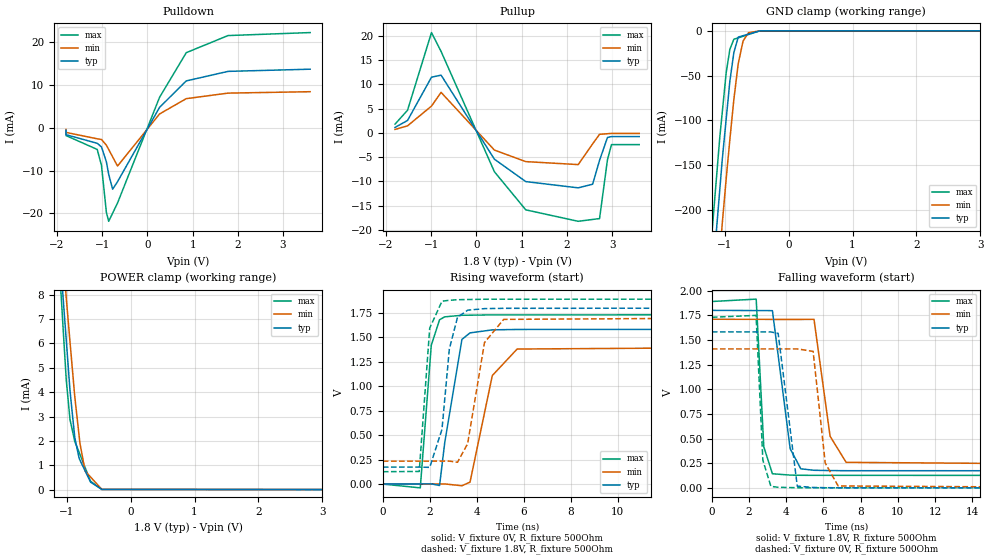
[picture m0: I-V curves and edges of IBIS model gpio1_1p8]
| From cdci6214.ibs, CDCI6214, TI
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|   gpio1_1p8 Model
[Model]   gpio1_1p8
Model_type   I/O
Polarity   Non-Inverting
Enable   Active-High
Vinl = 0.36
Vinh = 1.44
Vmeas = 0.9
Vref = 0
Cref = 2pF
Rref = 100000
|   typ   min   max
C_comp   1.252E-12   1.207E-12   1.304E-12
|  Where Nom  PVT is Nominal Process, 1.8V,   32C
|   Fast PVT is Strong Process,  1.89V, -35C
|   Slow PVT is Weak Process,   1.71V, 110C
[Model spec]
|subparameter
Vinl   0.36   0.342   0.378
Vinh   1.44   1.368   1.512
[Voltage Range]   1.8   1.71   1.89
|Junction Temperature
[Temperature Range]   32   110   -35
[Pullup Reference]   1.8   1.71   1.89
[Pulldown Reference]   0   0   0
[Power Clamp Reference]   1.8   1.71   1.89
[GND Clamp Reference]   0   0   0
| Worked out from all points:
|   slope of the pulldown table from 0 to 0.27 V, typ, clamps not added: 55.7 ohm
|   slope of the pullup table from 0 to 0.27 V, typ, clamps not added: 70.4 ohm
|   GND clamp passes 1 mA (typ) near -0.50 V on its own axis
|   POWER clamp passes 1 mA (typ) near -0.75 V on its own axis
|   falling waveform, V_fixture 1.8V, R_fixture 500Ohm: 20-80 % time 400ps typ, 631ps min, 255ps max; typ from 1.8 V to 0.173 V
|   rising waveform, V_fixture 0V, R_fixture 500Ohm: 20-80 % time 469ps typ, 763ps min, 311ps max; typ from 0 V to 1.58 V
|   rising waveform, V_fixture 1.8V, R_fixture 500Ohm: 20-80 % time 398ps typ, 588ps min, 276ps max; typ from 0.173 V to 1.8 V
|   falling waveform, V_fixture 0V, R_fixture 500Ohm: 20-80 % time 328ps typ, 464ps min, 225ps max; typ from 1.58 V to 0 V
[Pulldown]
|   Voltage   I(typ)   I(min)   I(max)
-1.8V     -534.4uA   -343.3uA   -743.5uA
-1.799V   -1.576mA   -1.043mA   -1.791mA
-1.11V    -3.594mA   -2.538mA   -5.023mA
-1.016V   -4.44mA    -2.696mA   -8.752mA
-907.8mV  -7.93mA    -4.019mA   -19.73mA
-856.5mV  -10.85mA   -5.037mA   -21.84mA
-769.6mV  -14.33mA   -6.76mA    -19.94mA
-661.2mV  -12.58mA   -8.91mA    -17.56mA
268.4mV   4.819mA    3.273mA    7.164mA
859.7mV   11.01mA    6.859mA    17.62mA
1.784V    13.24mA    8.153mA    21.62mA
3.6V      13.75mA    8.484mA    22.32mA
[GND Clamp]
|   Voltage   I(typ)   I(min)   I(max)
-1.8V     -850.2mA   -919.7mA   -794.1mA
-1.193V   -278.9mA   -350.7mA   -220.9mA
-1.076V   -177.3mA   -248.8mA   -118.9mA
-1.036V   -142.7mA   -214.1mA   -90.05mA
-975.8mV  -98.35mA   -165.2mA   -46.72mA
-918.6mV  -56.29mA   -121.4mA   -20.63mA
-855.9mV  -24.17mA   -76.52mA   -9.412mA
-787.5mV  -7.002mA   -36.62mA   -7.827mA
-711.9mV  -5.436mA   -11.36mA   -6.076mA
-626.1mV  -3.657mA   -2.091mA   -4.086mA
-449.8mV  -7.895uA   -51.08uA   -2.497uA
3.6V      0A         0A         0A
[Pullup]
|   Voltage   I(typ)   I(min)   I(max)
-1.8V     1.138mA    720.3uA    1.811mA
-1.524V   2.565mA    1.459mA    4.673mA
-994.2mV  11.48mA    5.53mA     20.67mA
-782.2mV  11.9mA     8.354mA    16.79mA
397.4mV   -5.409mA   -3.533mA   -7.995mA
1.091V    -10.02mA   -5.907mA   -15.84mA
2.251V    -11.31mA   -6.521mA   -18.2mA
2.57V     -10.56mA   -2.253mA   -17.82mA
2.723V    -5.635mA   -283.5uA   -17.64mA
2.898V    -941.7uA   -163.4uA   -5.522mA
2.987V    -754.9uA   -102.9uA   -2.403mA
3.6V      -754.9uA   -102.9uA   -2.403mA
[POWER Clamp]
|   Voltage   I(typ)   I(min)   I(max)
-1.8V     40.9mA     37.22mA    47.79mA
-1.102V   9.844mA    11.21mA    8.686mA
-1.055V   7.877mA    9.555mA    6.632mA
-1.005V   6.115mA    7.85mA     4.479mA
-947.2mV  4.068mA    6.068mA    2.877mA
-872.2mV  2.133mA    3.809mA    1.978mA
-803.1mV  1.274mA    2.173mA    1.52mA
-791.3mV  1.209mA    1.896mA    1.442mA
-710.3mV  768.4uA    759.9uA    904.6uA
-625.3mV  306.3uA    515.8uA    341uA
-449.8mV  9.837uA    11.93uA    5.418uA
3.6V      0A         0A         0A
[Ramp]
R_load = 500
|   typ   min   max
dV/dt_r   0.949422/4.66812e-10   0.845683/7.56947e-10   1.03789/3.08826e-10
dV/dt_f   0.976018/3.98838e-10   0.885426/6.29237e-10   1.05806/2.5483e-10
[Falling Waveform]
V_fixture = 1.8V
V_fixture_min = 1.71V
V_fixture_max = 1.89V
R_fixture = 500Ohm
C_fixture = 0F
|   Time   V(typ)   V(min)   V(max)
0s        1.8V       1.71V      1.89V
2.383ns   1.798V     1.709V     1.914V
2.792ns   1.798V     1.709V     416.2mV
3.255ns   1.797V     1.708V     143mV
4.21ns    396.9mV    1.708V     129.5mV
4.781ns   193.1mV    1.708V     127.6mV
5.491ns   178.3mV    1.709V     127mV
6.355ns   175.3mV    523.4mV    127mV
7.219ns   174mV      258.7mV    126.9mV
25ns      173.3mV    234.3mV    126.6mV
[Rising Waveform]
V_fixture = 0V
V_fixture_min = 0V
V_fixture_max = 0V
R_fixture = 500Ohm
C_fixture = 0F
|   Time   V(typ)   V(min)   V(max)
0s        -560nV     -3.175uV   -9.945nV
1.594ns   1.679mV    962.5uV    -38.6mV
2.063ns   2.172mV    1.247mV    1.419V
2.415ns   -14.67mV   1.46mV     1.679V
2.635ns   422.2mV    1.593mV    1.709V
3.367ns   1.478V     -17.11mV   1.725V
3.712ns   1.545V     19.72mV    1.726V
4.661ns   1.576V     1.109V     1.729V
5.718ns   1.58V      1.38V      1.729V
25ns      1.582V     1.409V     1.73V
[Rising Waveform]
V_fixture = 1.8V
V_fixture_min = 1.71V
V_fixture_max = 1.89V
R_fixture = 500Ohm
C_fixture = 0F
|   Time   V(typ)   V(min)   V(max)
0s        173.3mV    234.3mV    126.6mV
1.549ns   173.9mV    234.7mV    129.1mV
1.996ns   170.8mV    234.8mV    1.594V
2.519ns   560.1mV    235mV      1.869V
2.831ns   1.379V     235mV      1.878V
3.178ns   1.704V     222.8mV    1.884V
3.611ns   1.777V     412.6mV    1.886V
4.328ns   1.793V     1.446V     1.889V
5.144ns   1.796V     1.683V     1.889V
25ns      1.8V       1.71V      1.89V
[Falling Waveform]
|Gnd
V_fixture = 0V
V_fixture_min = 0V
V_fixture_max = 0V
R_fixture = 500Ohm
C_fixture = 0F
|   Time   V(typ)   V(min)   V(max)
0s        1.582V     1.409V     1.73V
2.377ns   1.582V     1.409V     1.749V
2.741ns   1.581V     1.409V     280.5mV
3.173ns   1.581V     1.409V     15.24mV
3.563ns   1.567V     1.409V     5.696mV
4.592ns   17.33mV    1.409V     1.272mV
5.443ns   3.899mV    1.384V     370.7uV
6.094ns   1.929mV    251.7mV    358.3uV
6.789ns   599.8uV    19.14mV    345.1uV
25ns      -2.146uV   -974.5nV   -841.8nV
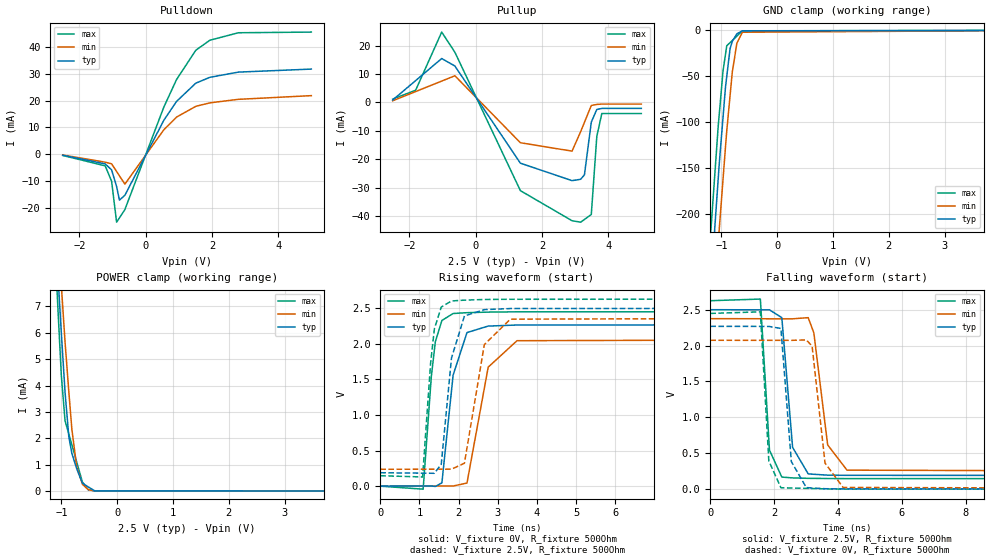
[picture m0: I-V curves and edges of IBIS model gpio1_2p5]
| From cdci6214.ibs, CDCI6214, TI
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|   gpio1_2p5 Model
[Model]   gpio1_2p5
Model_type   I/O
Polarity   Non-Inverting
Enable   Active-High
Vinl = 0.5
Vinh = 2
Vmeas = 1.25
Vref = 0
Cref = 2pF
Rref = 100000
|   typ   min   max
C_comp   1.238E-12   1.196E-12   1.283E-12
|  Where Nom  PVT is Nominal Process, 2.5V,   32C
|   Fast PVT is Strong Process,  2.625V, -35C
|   Slow PVT is Weak Process,   2.375V, 110C
[Model spec]
|subparameter
Vinl   0.5   0.475   0.525
Vinh   2   1.9   2.1
[Voltage Range]   2.5   2.375   2.625
|Junction Temperature
[Temperature Range]   32   110   -35
[Pullup Reference]   2.5   2.375   2.625
[Pulldown Reference]   0   0   0
[Power Clamp Reference]   2.5   2.375   2.625
[GND Clamp Reference]   0   0   0
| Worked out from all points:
|   slope of the pulldown table from 0 to 0.375 V, typ, clamps not added: 42.2 ohm
|   slope of the pullup table from 0 to 0.375 V, typ, clamps not added: 52.2 ohm
|   GND clamp passes 1 mA (typ) near -0.64 V on its own axis
|   POWER clamp passes 1 mA (typ) near -0.76 V on its own axis
|   falling waveform, V_fixture 2.5V, R_fixture 500Ohm: 20-80 % time 249ps typ, 353ps min, 177ps max; typ from 2.5 V to 0.189 V
|   rising waveform, V_fixture 0V, R_fixture 500Ohm: 20-80 % time 289ps typ, 418ps min, 205ps max; typ from 0 V to 2.27 V
|   rising waveform, V_fixture 2.5V, R_fixture 500Ohm: 20-80 % time 268ps typ, 372ps min, 194ps max; typ from 0.189 V to 2.5 V
|   falling waveform, V_fixture 0V, R_fixture 500Ohm: 20-80 % time 225ps typ, 304ps min, 165ps max; typ from 2.27 V to 0 V
[Pulldown]
|   Voltage   I(typ)   I(min)   I(max)
-2.5V     -377.7uA   -273.8uA   -478.9uA
-1.219V   -3.643mA   -3.006mA   -4.374mA
-1.025V   -5.883mA   -3.611mA   -10.14mA
-873.9mV  -12.11mA   -6.479mA   -25.46mA
-788.5mV  -17.2mA    -8.104mA   -23.84mA
-625mV    -15.39mA   -11.21mA   -20.75mA
551.9mV   12.71mA    9.153mA    17.66mA
934.4mV   19.76mA    13.88mA    27.94mA
1.515V    26.58mA    17.91mA    38.9mA
1.939V    28.77mA    19.21mA    42.65mA
2.799V    30.72mA    20.53mA    45.45mA
5V        31.85mA    21.91mA    45.7mA
[GND Clamp]
|   Voltage   I(typ)   I(min)   I(max)
-2.5V     -1.532A    -1.598A    -1.479A
-1.229V   -310.7mA   -383.7mA   -251.8mA
-1.058V   -161.6mA   -231.9mA   -104.4mA
-1.036V   -142.8mA   -213.9mA   -89.16mA
-971.4mV  -94.66mA   -162.1mA   -44.15mA
-927.2mV  -61.72mA   -126.6mA   -26.06mA
-904.6mV  -50.13mA   -109.4mA   -16.81mA
-845.5mV  -19.9mA    -71.15mA   -13.38mA
-806mV    -12.04mA   -45.73mA   -11.09mA
-723.5mV  -3.784mA   -13.92mA   -6.312mA
-625mV    -518.2uA   -2.081mA   -602.9uA
5V        0A         0A         0A
[Pullup]
|   Voltage   I(typ)   I(min)   I(max)
-2.5V     863.2uA    597.5uA    1.192mA
-1.808V   7.701mA    3.843mA    4.308mA
-1.022V   15.47mA    7.531mA    24.77mA
-624.5mV  12.83mA    9.398mA    17.68mA
1.352V    -21.36mA   -14.17mA   -31.03mA
2.91V     -27.51mA   -17.12mA   -41.61mA
3.17V     -27.02mA   -10.27mA   -42.13mA
3.284V    -25.47mA   -6.997mA   -41.18mA
3.491V    -6.918mA   -1.049mA   -39.42mA
3.657V    -2.462mA   -696.9uA   -11.96mA
3.808V    -2.089mA   -557.7uA   -3.894mA
5V        -2.089mA   -557.7uA   -3.894mA
[POWER Clamp]
|   Voltage   I(typ)   I(min)   I(max)
-2.5V     73.53mA    64.44mA    89.01mA
-1.085V   9.153mA    10.62mA    7.88mA
-1.055V   7.877mA    9.508mA    6.585mA
-1.002V   5.997mA    7.808mA    4.379mA
-935.4mV  3.748mA    5.651mA    2.665mA
-868mV    2.056mA    3.773mA    2.16mA
-812.7mV  1.421mA    2.33mA     1.746mA
-727.2mV  846.4uA    931.3uA    1.106mA
-624.9mV  297.1uA    253.7uA    338.8uA
-518.4mV  151.2uA    44.51uA    41.68uA
-403.7mV  2.859uA    5.5uA      1.412uA
5V        0A         0A         0A
[Ramp]
R_load = 500
|   typ   min   max
dV/dt_r   1.361/2.87747e-10   1.24438/4.1623e-10   1.46879/2.04608e-10
dV/dt_f   1.38683/2.47828e-10   1.28257/3.49891e-10   1.48709/1.76228e-10
[Falling Waveform]
V_fixture = 2.5V
V_fixture_min = 2.375V
V_fixture_max = 2.625V
R_fixture = 500Ohm
C_fixture = 0F
|   Time   V(typ)   V(min)   V(max)
0s        2.5V       2.375V     2.625V
1.568ns   2.498V     2.374V     2.648V
1.853ns   2.498V     2.373V     544mV
2.24ns    2.389V     2.373V     168.3mV
2.577ns   582.6mV    2.373V     156.8mV
3.066ns   213.2mV    2.389V     151mV
3.243ns   207.2mV    2.176V     150.2mV
3.675ns   195.3mV    616.6mV    148.3mV
4.281ns   192.7mV    264.8mV    147mV
25ns      188.6mV    237.4mV    146.5mV
[Rising Waveform]
V_fixture = 0V
V_fixture_min = 0V
V_fixture_max = 0V
R_fixture = 500Ohm
C_fixture = 0F
|   Time   V(typ)   V(min)   V(max)
0s        -1.66uV    -76.04nV   -15.21nV
1.095ns   2.18mV     1.405mV    -41.95mV
1.305ns   2.598mV    1.674mV    1.543V
1.407ns   -3.984mV   1.806mV    2.027V
1.574ns   46.33mV    2.02mV     2.325V
1.861ns   1.559V     2.388mV    2.422V
2.215ns   2.155V     43.82mV    2.434V
2.757ns   2.246V     1.67V      2.442V
3.493ns   2.261V     2.041V     2.446V
25ns      2.268V     2.074V     2.448V
[Rising Waveform]
V_fixture = 2.5V
V_fixture_min = 2.375V
V_fixture_max = 2.625V
R_fixture = 500Ohm
C_fixture = 0F
|   Time   V(typ)   V(min)   V(max)
0s        188.6mV    237.4mV    146.5mV
1.081ns   182.5mV    238mV      129.3mV
1.286ns   181.4mV    238.1mV    1.729V
1.382ns   180.8mV    238.1mV    2.207V
1.558ns   307.5mV    238.2mV    2.513V
1.819ns   1.797V     238.3mV    2.598V
2.15ns    2.388V     322mV      2.61V
2.657ns   2.477V     1.986V     2.619V
3.323ns   2.492V     2.343V     2.622V
25ns      2.5V       2.375V     2.625V
[Falling Waveform]
|Gnd
V_fixture = 0V
V_fixture_min = 0V
V_fixture_max = 0V
R_fixture = 500Ohm
C_fixture = 0F
|   Time   V(typ)   V(min)   V(max)
0s        2.268V     2.074V     2.448V
1.567ns   2.267V     2.073V     2.47V
1.833ns   2.267V     2.073V     393.2mV
2.212ns   2.238V     2.073V     19.93mV
2.537ns   385.2mV    2.073V     16.22mV
3.007ns   22.05mV    2.079V     10.98mV
3.188ns   16.29mV    1.992V     8.96mV
3.593ns   6.128mV    363.2mV    4.444mV
4.159ns   3.939mV    23.86mV    444.4uV
25ns      -1.33uV    -518.7nV   21.16nV
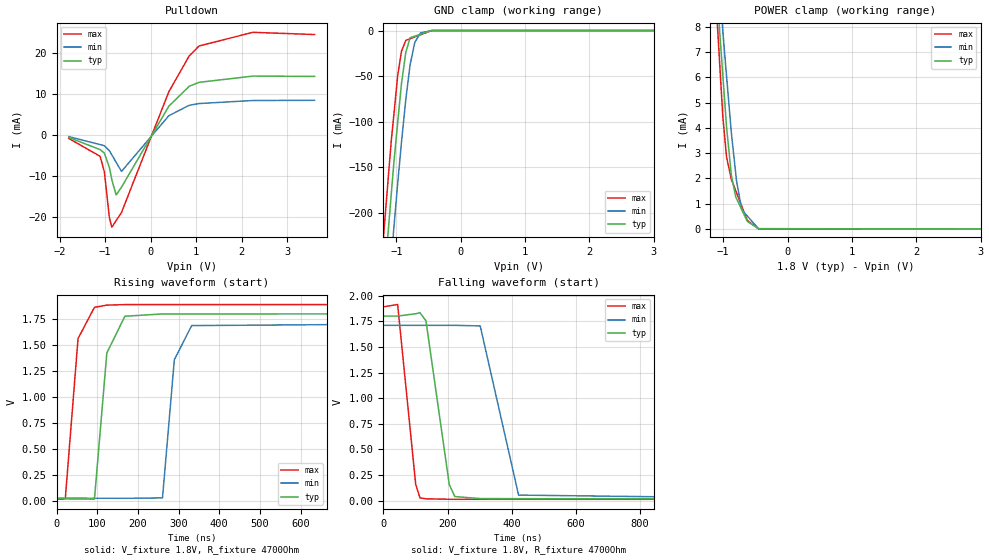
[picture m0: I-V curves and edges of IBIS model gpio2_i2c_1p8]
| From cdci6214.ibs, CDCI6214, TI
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|   gpio2_i2c_1p8 Model
[Model]   gpio2_i2c_1p8
Model_type   I/O_open_drain
Polarity   Inverting
Enable   Active-High
Vinl = 0.36
Vinh = 1.44
Vmeas = 0.9
Vref = 1.8
Cref = 1pF
Rref = 4700
|   typ   min   max
C_comp   1.654E-12   1.599E-12   1.724E-12
|  Where Nom  PVT is Nominal Process, 1.8V,   32C
|   Fast PVT is Strong Process,  1.89V, -35C
|   Slow PVT is Weak Process,   1.71V, 110C
[Model spec]
|subparameter
Vinl   0.36   0.342   0.378
Vinh   1.44   1.368   1.512
[Voltage Range]   1.8   1.71   1.89
|Junction Temperature
[Temperature Range]   32   110   -35
[Pullup Reference]   1.8   1.71   1.89
[Pulldown Reference]   0   0   -0
[Power Clamp Reference]   1.8   1.71   1.89
[GND Clamp Reference]   0   0   0
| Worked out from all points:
|   slope of the pulldown table from 0 to 0.27 V, typ, clamps not added: 53.8 ohm
|   GND clamp passes 1 mA (typ) near -0.49 V on its own axis
|   POWER clamp passes 1 mA (typ) near -0.75 V on its own axis
|   falling waveform, V_fixture 1.8V, R_fixture 4700Ohm: 20-80 % time 47ns typ, 59.8ns min, 35ns max; typ from 1.8 V to 0.019 V
|   rising waveform, V_fixture 1.8V, R_fixture 4700Ohm: 20-80 % time 23.4ns typ, 23.2ns min, 24.1ns max; typ from 0.019 V to 1.8 V
[Pulldown]
|   Voltage   I(typ)   I(min)   I(max)
-1.8V     -529.7uA   -319uA     -765.4uA
-1.113V   -3.481mA   -2.265mA   -5.111mA
-1.019V   -4.334mA   -2.531mA   -8.878mA
-907.6mV  -7.882mA   -3.763mA   -20.16mA
-853.6mV  -10.9mA    -4.789mA   -22.37mA
-759.2mV  -14.52mA   -6.582mA   -20.78mA
-642.8mV  -12.64mA   -8.795mA   -18.81mA
397.6mV   7.091mA    4.775mA    10.61mA
844.7mV   11.93mA    7.309mA    19.32mA
1.061V    12.9mA     7.735mA    21.76mA
2.247V    14.42mA    8.478mA    25.08mA
3.6V      14.34mA    8.522mA    24.54mA
[GND Clamp]
|   Voltage   I(typ)   I(min)   I(max)
-1.8V     -850.4mA   -920mA     -794.3mA
-1.195V   -281.4mA   -353.2mA   -223.4mA
-1.078V   -179.7mA   -251.2mA   -121.3mA
-1.038V   -145.7mA   -217.1mA   -93.09mA
-977.8mV  -100.9mA   -167.7mA   -49.4mA
-919.4mV  -58.33mA   -123.1mA   -22.82mA
-852.7mV  -24.16mA   -76.14mA   -10.82mA
-785.2mV  -7.96mA    -37.67mA   -9.006mA
-711.4mV  -6.211mA   -12.78mA   -7.027mA
-621.2mV  -4.073mA   -2.524mA   -4.607mA
-449.5mV  -9.741uA   -65.93uA   -3.053uA
3.6V      0A         0A         0A
[POWER Clamp]
|   Voltage   I(typ)   I(min)   I(max)
-1.8V     40.78mA    37.11mA    47.66mA
-1.102V   9.792mA    11.17mA    8.628mA
-1.055V   7.836mA    9.518mA    6.587mA
-1.005V   6.075mA    7.815mA    4.436mA
-947mV    4.034mA    6.038mA    2.843mA
-872.1mV  2.111mA    3.79mA     1.956mA
-803.5mV  1.264mA    2.173mA    1.507mA
-791.3mV  1.197mA    1.885mA    1.427mA
-710.3mV  761uA      754.3uA    896.6uA
-624.6mV  299.7uA    509.9uA    335uA
-449.6mV  9.478uA    10.99uA    5.168uA
3.6V      0A         0A         0A
[Ramp]
R_load = 4700
|   typ   min   max
dV/dt_r   1.06865/2.34279e-08   1.01076/2.31746e-08   1.12574/2.41307e-08
dV/dt_f   1.06865/4.70057e-08   1.01076/5.97479e-08   1.12574/3.50203e-08
[Falling Waveform]
V_fixture = 1.8V
V_fixture_min = 1.71V
V_fixture_max = 1.89V
R_fixture = 4700Ohm
C_fixture = 0F
|   Time   V(typ)   V(min)   V(max)
0s        1.8V       1.71V      1.89V
44.34ns   1.8V       1.71V      1.913V
100.7ns   1.823V     1.71V      158.3mV
113.9ns   1.833V     1.71V      28.66mV
132.7ns   1.754V     1.71V      18.69mV
205.3ns   157.9mV    1.71V      14.27mV
222.6ns   40.74mV    1.71V      14.26mV
301.7ns   21.25mV    1.704V     14.22mV
421.3ns   19.91mV    55.14mV    14.15mV
1.2us     18.86mV    25.33mV    13.74mV
[Rising Waveform]
V_fixture = 1.8V
V_fixture_min = 1.71V
V_fixture_max = 1.89V
R_fixture = 4700Ohm
C_fixture = 0F
|   Time   V(typ)   V(min)   V(max)
0s        18.86mV    25.33mV    13.74mV
21.56ns   18.05mV    25.12mV    19.68mV
52.9ns    16.86mV    24.82mV    1.562V
93.28ns   15.33mV    24.43mV    1.863V
123.7ns   1.423V     24.13mV    1.884V
168.1ns   1.777V     23.7mV     1.889V
260.6ns   1.799V     27.37mV    1.889V
289.7ns   1.799V     1.358V     1.889V
332.4ns   1.799V     1.687V     1.889V
1.2us     1.8V       1.71V      1.89V
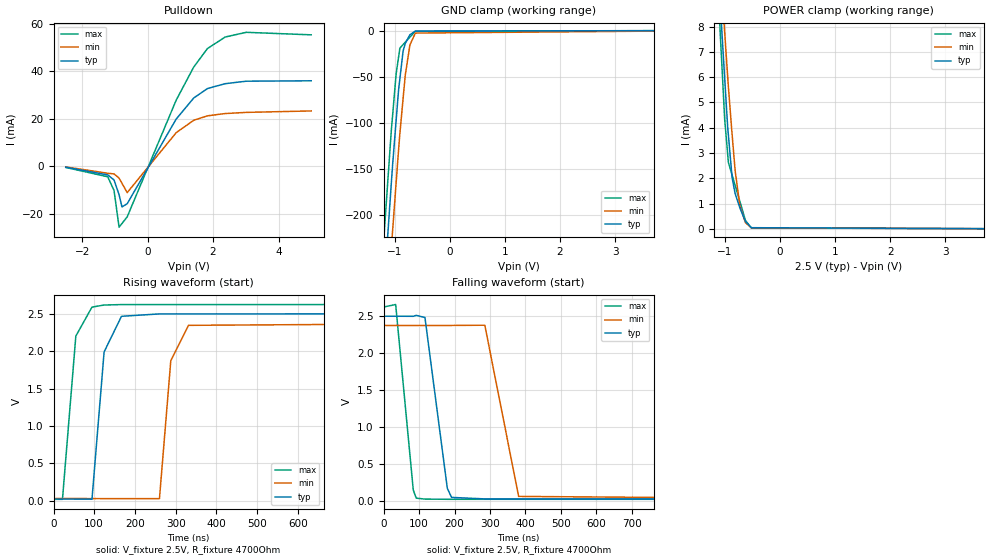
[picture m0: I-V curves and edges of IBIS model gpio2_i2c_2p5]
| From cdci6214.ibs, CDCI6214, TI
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|   gpio2_i2c_2p5 Model
[Model]   gpio2_i2c_2p5
Model_type   I/O_open_drain
Polarity   Inverting
Enable   Active-High
Vinl = 0.5
Vinh = 2
Vmeas = 1.25
Vref = 2.5
Cref = 1pF
Rref = 4700
|   typ   min   max
C_comp   1.718E-12   1.615E-12   1.829E-12
|  Where Nom  PVT is Nominal Process, 2.5V,   32C
|   Fast PVT is Strong Process,  2.625V, -35C
|   Slow PVT is Weak Process,   2.375V, 110C
[Model spec]
|subparameter
Vinl   0.5   0.475   0.525
Vinh   2   1.9   2.1
[Voltage Range]   2.5   2.375   2.625
|Junction Temperature
[Temperature Range]   32   110   -35
[Pullup Reference]   2.5   2.375   2.625
[Pulldown Reference]   0   -0   0
[Power Clamp Reference]   2.5   2.375   2.625
[GND Clamp Reference]   0   0   0
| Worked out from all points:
|   slope of the pulldown table from 0 to 0.375 V, typ, clamps not added: 41.1 ohm
|   GND clamp passes 1 mA (typ) near -0.63 V on its own axis
|   POWER clamp passes 1 mA (typ) near -0.76 V on its own axis
|   falling waveform, V_fixture 2.5V, R_fixture 4700Ohm: 20-80 % time 40.2ns typ, 49.3ns min, 31ns max; typ from 2.5 V to 0.021 V
|   rising waveform, V_fixture 2.5V, R_fixture 4700Ohm: 20-80 % time 24ns typ, 23.3ns min, 24.9ns max; typ from 0.021 V to 2.5 V
[Pulldown]
|   Voltage   I(typ)   I(min)   I(max)
-2.5V     -367.7uA   -253.3uA   -481.2uA
-1.218V   -3.636mA   -2.932mA   -4.418mA
-1.026V   -5.763mA   -3.216mA   -10.19mA
-872mV    -11.96mA   -4.964mA   -25.65mA
-783.7mV  -17.12mA   -7.15mA    -24.11mA
-624.2mV  -15.78mA   -11.1mA    -21.31mA
873mV     19.91mA    14.17mA    27.87mA
1.408V    28.78mA    19.4mA     41.81mA
1.827V    32.77mA    21.27mA    49.63mA
2.371V    34.83mA    22.24mA    54.5mA
3.013V    35.88mA    22.73mA    56.48mA
5V        36.05mA    23.34mA    55.42mA
[GND Clamp]
|   Voltage   I(typ)   I(min)   I(max)
-2.5V     -1.532A    -1.598A    -1.479A
-1.232V   -314.3mA   -387.3mA   -255.3mA
-1.061V   -165.2mA   -235.5mA   -108mA
-1.039V   -146.6mA   -217.7mA   -92.9mA
-974mV    -97.68mA   -165.1mA   -47.23mA
-930mV    -64.83mA   -129.8mA   -29.04mA
-905.7mV  -52.33mA   -111.5mA   -19.02mA
-846.7mV  -22.01mA   -73.35mA   -15.18mA
-808mV    -14.03mA   -48.41mA   -12.66mA
-724mV    -4.548mA   -15.69mA   -7.195mA
-624.7mV  -640.1uA   -2.747mA   -737.7uA
5V        0A         0A         0A
[POWER Clamp]
|   Voltage   I(typ)   I(min)   I(max)
-2.5V     73.33mA    64.26mA    88.79mA
-1.085V   9.096mA    10.57mA    7.816mA
-1.054V   7.83mA     9.466mA    6.533mA
-1.002V   5.951mA    7.767mA    4.33mA
-948mV    4.035mA    6.035mA    2.961mA
-935mV    3.711mA    5.617mA    2.63mA
-867.7mV  2.032mA    3.75mA     2.133mA
-812.5mV  1.401mA    2.313mA    1.724mA
-727mV    837.2uA    922.4uA    1.092mA
-624.2mV  292.6uA    247.7uA    333.4uA
-518mV    49.58uA    44.54uA    40.45uA
5V        0A         0A         0A
[Ramp]
R_load = 4700
|   typ   min   max
dV/dt_r   1.48749/2.39695e-08   1.40913/2.3343e-08   1.56538/2.48163e-08
dV/dt_f   1.48749/4.0161e-08   1.40913/4.93591e-08   1.56538/3.09874e-08
[Falling Waveform]
V_fixture = 2.5V
V_fixture_min = 2.375V
V_fixture_max = 2.625V
R_fixture = 4700Ohm
C_fixture = 0F
|   Time   V(typ)   V(min)   V(max)
0s        2.5V       2.375V     2.625V
33.87ns   2.5V       2.375V     2.659V
83.53ns   2.499V     2.375V     142.6mV
91.83ns   2.512V     2.375V     32.09mV
116.5ns   2.482V     2.375V     19.19mV
179.6ns   163.7mV    2.375V     16.56mV
191.7ns   42.14mV    2.375V     16.55mV
285.3ns   21.86mV    2.378V     16.5mV
380.7ns   21.75mV    55.66mV    16.45mV
1.2us     20.81mV    26.37mV    16mV
[Rising Waveform]
V_fixture = 2.5V
V_fixture_min = 2.375V
V_fixture_max = 2.625V
R_fixture = 4700Ohm
C_fixture = 0F
|   Time   V(typ)   V(min)   V(max)
0s        20.81mV    26.37mV    16mV
21.95ns   20.05mV    26.27mV    15.86mV
54.81ns   18.92mV    26.13mV    2.202V
94.5ns    17.56mV    25.95mV    2.59V
124.3ns   1.99V      25.81mV    2.618V
167ns     2.467V     25.62mV    2.624V
260.3ns   2.499V     25.19mV    2.624V
288.2ns   2.499V     1.874V     2.624V
331.7ns   2.499V     2.346V     2.624V
1.2us     2.5V       2.375V     2.625V
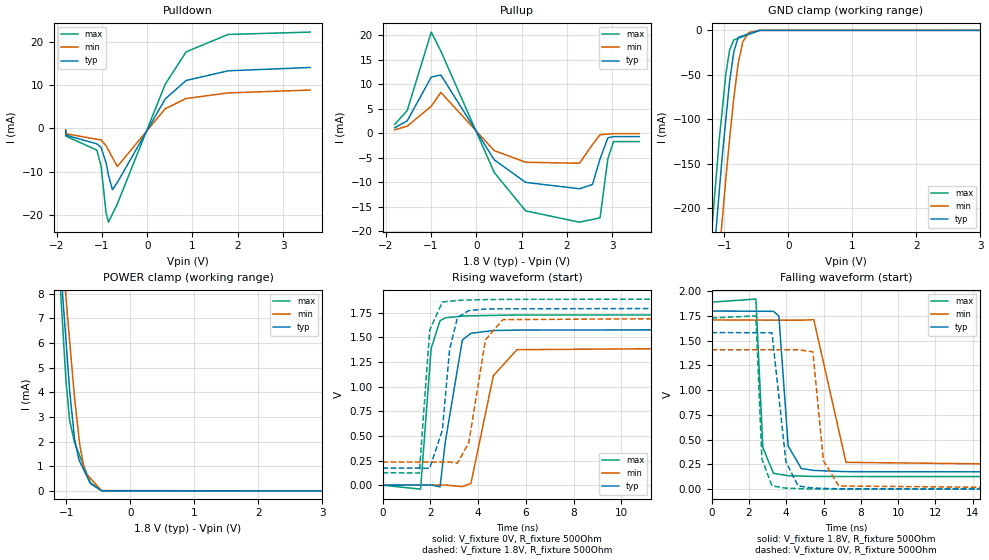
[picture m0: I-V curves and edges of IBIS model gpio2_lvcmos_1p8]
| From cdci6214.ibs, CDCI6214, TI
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|   gpio2_lvcmos_1p8 Model
[Model]   gpio2_lvcmos_1p8
Model_type   I/O
Polarity   Non-Inverting
Enable   Active-High
Vinl = 0.36
Vinh = 1.44
Vmeas = 0.9
Vref = 0
Cref = 1pF
Rref = 100000
|   typ   min   max
C_comp   1.654E-12   1.599E-12   1.724E-12
|  Where Nom  PVT is Nominal Process, 1.8V,   32C
|   Fast PVT is Strong Process,  1.89V, -35C
|   Slow PVT is Weak Process,   1.71V, 110C
[Model spec]
|subparameter
Vinl   0.36   0.342   0.378
Vinh   1.44   1.368   1.512
[Voltage Range]   1.8   1.71   1.89
|Junction Temperature
[Temperature Range]   32   110   -35
[Pullup Reference]   1.8   1.71   1.89
[Pulldown Reference]   0   0   0
[Power Clamp Reference]   1.8   1.71   1.89
[GND Clamp Reference]   0   0   0
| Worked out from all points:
|   slope of the pulldown table from 0 to 0.27 V, typ, clamps not added: 55.7 ohm
|   slope of the pullup table from 0 to 0.27 V, typ, clamps not added: 70.4 ohm
|   GND clamp passes 1 mA (typ) near -0.49 V on its own axis
|   POWER clamp passes 1 mA (typ) near -0.75 V on its own axis
|   falling waveform, V_fixture 1.8V, R_fixture 500Ohm: 20-80 % time 351ps typ, 554ps min, 225ps max; typ from 1.8 V to 0.173 V
|   rising waveform, V_fixture 0V, R_fixture 500Ohm: 20-80 % time 463ps typ, 752ps min, 307ps max; typ from 0 V to 1.58 V
|   rising waveform, V_fixture 1.8V, R_fixture 500Ohm: 20-80 % time 385ps typ, 553ps min, 272ps max; typ from 0.173 V to 1.8 V
|   falling waveform, V_fixture 0V, R_fixture 500Ohm: 20-80 % time 296ps typ, 424ps min, 204ps max; typ from 1.58 V to 0 V
[Pulldown]
|   Voltage   I(typ)   I(min)   I(max)
-1.8V     -537.8uA   -345.4uA   -748.9uA
-1.799V   -1.58mA    -1.247mA   -1.797mA
-1.114V   -3.583mA   -2.531mA   -5.014mA
-1.02V    -4.414mA   -2.689mA   -8.661mA
-909.2mV  -7.942mA   -4.03mA    -19.5mA
-856.3mV  -10.83mA   -5.049mA   -21.64mA
-768.4mV  -14.16mA   -6.738mA   -19.76mA
-660.6mV  -12.48mA   -8.812mA   -17.45mA
397.6mV   6.769mA    4.507mA    10.15mA
859.9mV   11.02mA    6.86mA     17.62mA
1.784V    13.24mA    8.153mA    21.62mA
3.6V      14.01mA    8.814mA    22.17mA
[GND Clamp]
|   Voltage   I(typ)   I(min)   I(max)
-1.8V     -850.4mA   -920mA     -794.3mA
-1.195V   -281.4mA   -353.2mA   -223.4mA
-1.078V   -179.7mA   -251.2mA   -121.3mA
-1.038V   -145.7mA   -217.1mA   -93.09mA
-977.8mV  -100.9mA   -167.7mA   -49.4mA
-919.4mV  -58.33mA   -123.1mA   -22.82mA
-852.7mV  -24.16mA   -76.14mA   -10.82mA
-785.2mV  -7.96mA    -37.67mA   -9.006mA
-711.4mV  -6.211mA   -12.78mA   -7.027mA
-621.2mV  -4.073mA   -2.524mA   -4.607mA
-449.5mV  -9.741uA   -65.94uA   -3.053uA
3.6V      0A         0A         0A
[Pullup]
|   Voltage   I(typ)   I(min)   I(max)
-1.8V     1.137mA    720.3uA    1.81mA
-1.524V   2.566mA    1.459mA    4.675mA
-994mV    11.48mA    5.533mA    20.67mA
-782.1mV  11.91mA    8.354mA    16.79mA
397.6mV   -5.411mA   -3.536mA   -7.998mA
1.091V    -10.02mA   -5.907mA   -15.84mA
2.28V     -11.32mA   -6.117mA   -18.15mA
2.567V    -10.46mA   -2.311mA   -17.59mA
2.736V    -5.206mA   -277.7uA   -17.25mA
2.908V    -916uA     -160.6uA   -5.155mA
3.033V    -667.4uA   -74.97uA   -1.7mA
3.6V      -667.4uA   -74.97uA   -1.7mA
[POWER Clamp]
|   Voltage   I(typ)   I(min)   I(max)
-1.8V     40.78mA    37.11mA    47.66mA
-1.102V   9.792mA    11.17mA    8.629mA
-1.055V   7.836mA    9.518mA    6.587mA
-1.005V   6.075mA    7.815mA    4.436mA
-947mV    4.034mA    6.038mA    2.843mA
-872.1mV  2.111mA    3.79mA     1.956mA
-803.5mV  1.264mA    2.173mA    1.507mA
-791.3mV  1.197mA    1.885mA    1.427mA
-710.3mV  761uA      754.3uA    896.6uA
-624.6mV  299.7uA    509.9uA    335uA
-449.6mV  9.478uA    11uA       5.169uA
3.6V      0A         0A         0A
[Ramp]
R_load = 500
|   typ   min   max
dV/dt_r   0.949391/4.63195e-10   0.845609/7.4815e-10   1.03788/3.06585e-10
dV/dt_f   0.975999/3.50184e-10   0.885366/5.52919e-10   1.05805/2.24752e-10
[Falling Waveform]
V_fixture = 1.8V
V_fixture_min = 1.71V
V_fixture_max = 1.89V
R_fixture = 500Ohm
C_fixture = 0F
|   Time   V(typ)   V(min)   V(max)
0s        1.8V       1.71V      1.89V
2.376ns   1.798V     1.709V     1.921V
2.748ns   1.798V     1.708V     420.8mV
3.316ns   1.797V     1.708V     160.4mV
3.608ns   1.749V     1.708V     150.9mV
4.107ns   436.4mV    1.708V     136.1mV
4.807ns   208.6mV    1.707V     132.4mV
5.479ns   189.5mV    1.713V     128.9mV
7.206ns   176.7mV    271.1mV    127.8mV
25ns      173.3mV    234.3mV    126.6mV
[Rising Waveform]
V_fixture = 0V
V_fixture_min = 0V
V_fixture_max = 0V
R_fixture = 500Ohm
C_fixture = 0F
|   Time   V(typ)   V(min)   V(max)
0s        -1.103uV   4.756uV    -245.1nV
1.592ns   1.736mV    958.5uV    -40.45mV
2.034ns   2.218mV    1.223mV    1.387V
2.407ns   -17.88mV   1.447mV    1.67V
2.63ns    444.3mV    1.58mV     1.7V
3.342ns   1.475V     -14.95mV   1.717V
3.7ns     1.542V     17.53mV    1.72V
4.64ns    1.571V     1.112V     1.724V
5.629ns   1.575V     1.376V     1.728V
25ns      1.582V     1.409V     1.73V
[Rising Waveform]
V_fixture = 1.8V
V_fixture_min = 1.71V
V_fixture_max = 1.89V
R_fixture = 500Ohm
C_fixture = 0F
|   Time   V(typ)   V(min)   V(max)
0s        173.3mV    234.3mV    126.6mV
1.539ns   173.9mV    234.7mV    123.8mV
1.974ns   171.6mV    234.8mV    1.575V
2.507ns   561.5mV    235mV      1.861V
2.806ns   1.376V     235.1mV    1.868V
3.136ns   1.702V     223.8mV    1.876V
3.61ns    1.773V     430.7mV    1.881V
4.31ns    1.789V     1.477V     1.884V
5.04ns    1.791V     1.681V     1.887V
25ns      1.8V       1.71V      1.89V
[Falling Waveform]
|Gnd
V_fixture = 0V
V_fixture_min = 0V
V_fixture_max = 0V
R_fixture = 500Ohm
C_fixture = 0F
|   Time   V(typ)   V(min)   V(max)
0s        1.582V     1.409V     1.73V
2.376ns   1.581V     1.409V     1.751V
2.698ns   1.581V     1.409V     304.5mV
3.236ns   1.581V     1.409V     33.37mV
3.987ns   275.6mV    1.409V     9.995mV
4.637ns   33.45mV    1.409V     6.084mV
5.43ns    11.74mV    1.388V     1.869mV
5.996ns   7.954mV    287.1mV    1.224mV
6.816ns   3.961mV    32.5mV     1.171mV
25ns      -958.9nV   4.906uV    -11.63nV
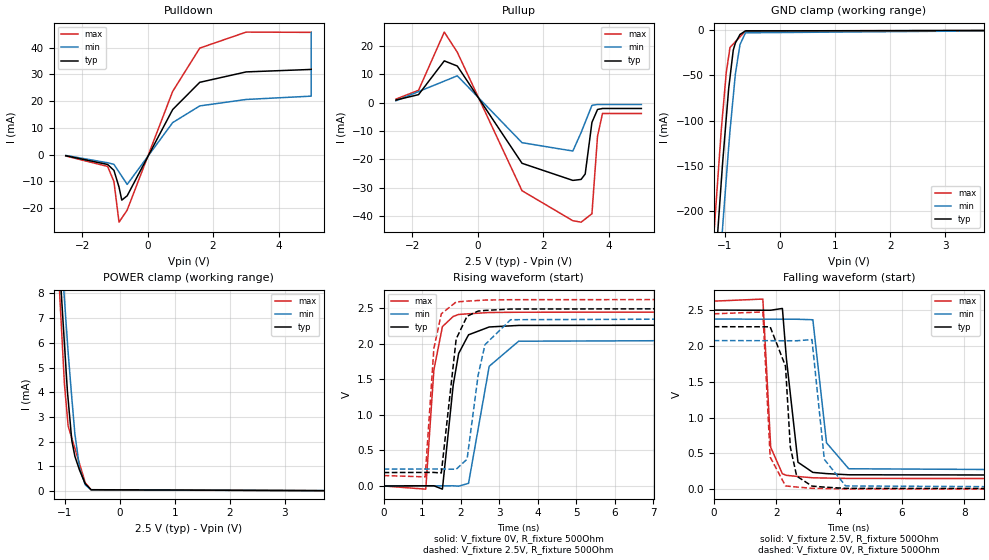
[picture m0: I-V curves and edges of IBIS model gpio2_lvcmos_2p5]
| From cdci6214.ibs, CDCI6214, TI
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|   gpio2_lvcmos_2p5 Model
[Model]   gpio2_lvcmos_2p5
Model_type   I/O
Polarity   Non-Inverting
Enable   Active-High
Vinl = 0.5
Vinh = 2
Vmeas = 1.25
Vref = 0
Cref = 1pF
Rref = 100000
|   typ   min   max
C_comp   1.718E-12   1.615E-12   1.829E-12
|  Where Nom  PVT is Nominal Process, 2.5V,   32C
|   Fast PVT is Strong Process,  2.625V, -35C
|   Slow PVT is Weak Process,   2.375V, 110C
[Model spec]
|subparameter
Vinl   0.5   0.475   0.525
Vinh   2   1.9   2.1
[Voltage Range]   2.5   2.375   2.625
|Junction Temperature
[Temperature Range]   32   110   -35
[Pullup Reference]   2.5   2.375   2.625
[Pulldown Reference]   0   0   0
[Power Clamp Reference]   2.5   2.375   2.625
[GND Clamp Reference]   0   0   0
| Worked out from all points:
|   slope of the pulldown table from 0 to 0.375 V, typ, clamps not added: 42.2 ohm
|   slope of the pullup table from 0 to 0.375 V, typ, clamps not added: 52.3 ohm
|   GND clamp passes 1 mA (typ) near -0.63 V on its own axis
|   POWER clamp passes 1 mA (typ) near -0.76 V on its own axis
|   falling waveform, V_fixture 2.5V, R_fixture 500Ohm: 20-80 % time 219ps typ, 308ps min, 157ps max; typ from 2.5 V to 0.189 V
|   rising waveform, V_fixture 0V, R_fixture 500Ohm: 20-80 % time 281ps typ, 407ps min, 199ps max; typ from 0 V to 2.27 V
|   rising waveform, V_fixture 2.5V, R_fixture 500Ohm: 20-80 % time 259ps typ, 358ps min, 188ps max; typ from 0.189 V to 2.5 V
|   falling waveform, V_fixture 0V, R_fixture 500Ohm: 20-80 % time 206ps typ, 277ps min, 152ps max; typ from 2.27 V to 0 V
[Pulldown]
|   Voltage   I(typ)   I(min)   I(max)
-2.5V     -379.2uA   -274.9uA   -481uA
-1.222V   -3.646mA   -3.005mA   -4.385mA
-1.029V   -5.848mA   -3.601mA   -10.04mA
-873.5mV  -12.11mA   -6.487mA   -25.22mA
-789mV    -16.97mA   -8.058mA   -23.68mA
-624.7mV  -15.35mA   -11.11mA   -20.7mA
766mV     16.88mA    12mA       23.66mA
1.594V    27.06mA    18.24mA    39.85mA
3.013V    30.95mA    20.65mA    45.83mA
4.999V    31.87mA    21.89mA    45.73mA
4.999V    31.87mA    45.75mA    45.73mA
5V        31.87mA    45.75mA    45.73mA
[GND Clamp]
|   Voltage   I(typ)   I(min)   I(max)
-2.5V     -1.532A    -1.598A    -1.479A
-1.232V   -314.3mA   -387.3mA   -255.3mA
-1.061V   -165.2mA   -235.5mA   -108mA
-1.039V   -146.6mA   -217.7mA   -92.9mA
-974mV    -97.68mA   -165.1mA   -47.23mA
-930mV    -64.83mA   -129.8mA   -29.04mA
-905.7mV  -52.33mA   -111.5mA   -19.02mA
-846.7mV  -22.01mA   -73.35mA   -15.18mA
-808mV    -14.03mA   -48.41mA   -12.66mA
-724mV    -4.548mA   -15.69mA   -7.195mA
-624.7mV  -640.1uA   -2.747mA   -737.7uA
5V        0A         0A         0A
[Pullup]
|   Voltage   I(typ)   I(min)   I(max)
-2.5V     863.1uA    597.5uA    1.192mA
-1.809V   2.764mA    3.84mA     4.3mA
-1.022V   14.65mA    7.53mA     24.78mA
-624.2mV  12.83mA    9.395mA    17.68mA
1.353V    -21.39mA   -14.13mA   -31.04mA
2.906V    -27.41mA   -17.08mA   -41.6mA
3.158V    -27.07mA   -10.6mA    -42.12mA
3.284V    -25.16mA   -6.969mA   -41mA
3.49V     -7.003mA   -1.014mA   -39.14mA
3.661V    -2.454mA   -681.6uA   -11.82mA
3.813V    -2.104mA   -681.6uA   -3.859mA
5V        -2.104mA   -681.6uA   -3.859mA
[POWER Clamp]
|   Voltage   I(typ)   I(min)   I(max)
-2.5V     73.33mA    64.26mA    88.79mA
-1.085V   9.096mA    10.57mA    7.816mA
-1.054V   7.83mA     9.466mA    6.534mA
-1.002V   5.951mA    7.767mA    4.33mA
-948mV    4.035mA    6.035mA    2.961mA
-935mV    3.711mA    5.617mA    2.63mA
-867.7mV  2.032mA    3.75mA     2.133mA
-812.5mV  1.402mA    2.313mA    1.724mA
-727mV    837.2uA    922.4uA    1.092mA
-624.2mV  292.6uA    247.7uA    333.4uA
-518mV    49.58uA    44.54uA    40.45uA
5V        0A         0A         0A
[Ramp]
R_load = 500
|   typ   min   max
dV/dt_r   1.36099/2.8001e-10   1.24435/4.06445e-10   1.46878/1.98834e-10
dV/dt_f   1.38681/2.18262e-10   1.28254/3.07327e-10   1.48709/1.57126e-10
[Falling Waveform]
V_fixture = 2.5V
V_fixture_min = 2.375V
V_fixture_max = 2.625V
R_fixture = 500Ohm
C_fixture = 0F
|   Time   V(typ)   V(min)   V(max)
0s        2.5V       2.375V     2.625V
1.566ns   2.498V     2.373V     2.654V
1.817ns   2.498V     2.373V     584.4mV
2.19ns    2.523V     2.373V     214.4mV
2.319ns   1.816V     2.373V     193.4mV
2.687ns   375.8mV    2.372V     176.6mV
3.162ns   234.1mV    2.365V     158.6mV
3.598ns   217.3mV    647.2mV    155.2mV
4.308ns   200.7mV    285mV      149.7mV
25ns      188.6mV    237.4mV    146.5mV
[Rising Waveform]
V_fixture = 0V
V_fixture_min = 0V
V_fixture_max = 0V
R_fixture = 500Ohm
C_fixture = 0F
|   Time   V(typ)   V(min)   V(max)
0s        137nV      825.4nV    -1.742uV
1.094ns   2.347mV    1.454mV    -44.99mV
1.305ns   2.801mV    1.735mV    1.628V
1.527ns   -44.9mV    2.03mV     2.238V
1.808ns   1.419V     2.403mV    2.381V
1.949ns   1.861V     -2.824mV   2.409V
2.206ns   2.123V     36.77mV    2.418V
2.743ns   2.233V     1.681V     2.436V
3.508ns   2.255V     2.033V     2.44V
25ns      2.268V     2.074V     2.448V
[Rising Waveform]
V_fixture = 2.5V
V_fixture_min = 2.375V
V_fixture_max = 2.625V
R_fixture = 500Ohm
C_fixture = 0F
|   Time   V(typ)   V(min)   V(max)
0s        188.6mV    237.4mV    146.5mV
1.079ns   190mV      238mV      127.8mV
1.305ns   190.3mV    238.1mV    1.931V
1.498ns   181.8mV    238.2mV    2.417V
1.885ns   2.065V     234.3mV    2.585V
2.168ns   2.384V     376.8mV    2.596V
2.455ns   2.456V     1.554V     2.605V
2.633ns   2.465V     1.984V     2.611V
3.299ns   2.485V     2.335V     2.616V
25ns      2.5V       2.375V     2.625V
[Falling Waveform]
|Gnd
V_fixture = 0V
V_fixture_min = 0V
V_fixture_max = 0V
R_fixture = 500Ohm
C_fixture = 0F
|   Time   V(typ)   V(min)   V(max)
0s        2.268V     2.074V     2.448V
1.566ns   2.267V     2.073V     2.474V
1.8ns     2.266V     2.073V     447.3mV
2.289ns   1.717V     2.072V     46.15mV
2.443ns   587.3mV    2.072V     38.52mV
2.646ns   182.1mV    2.072V     29.79mV
3.133ns   43.02mV    2.088V     11.9mV
3.528ns   28.28mV    415.9mV    8.795mV
4.208ns   11.74mV    44.76mV    3.459mV
25ns      261.2nV    547.7nV    -1.667uV
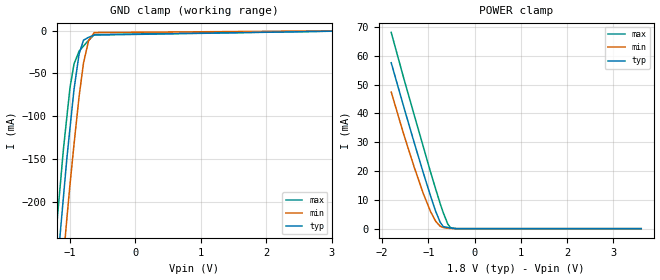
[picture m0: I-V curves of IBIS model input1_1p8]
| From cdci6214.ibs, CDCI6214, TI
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|   input1_1p8 Model
[Model]   input1_1p8
Model_type   Input
Vinl = 0.36
Vinh = 1.44
|   typ   min   max
C_comp   1.140E-12   1.127E-12   1.145E-12
|  Where Nom  PVT is Nominal Process, 1.8V,   32C
|   Fast PVT is Strong Process,  1.89V, -35C
|   Slow PVT is Weak Process,   1.71V, 110C
[Model spec]
|subparameter
Vinl   0.36   0.342   0.378
Vinh   1.44   1.368   1.512
[Voltage Range]   1.8   1.71   1.89
|Junction Temperature
[Temperature Range]   32   110   -35
[Power Clamp Reference]   1.8   1.71   1.89
[GND Clamp Reference]   0   0   0
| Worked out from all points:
|   GND clamp passes 1 mA (typ) near -0.48 V on its own axis
|   POWER clamp passes 1 mA (typ) near -0.69 V on its own axis
[GND Clamp]
|   Voltage   I(typ)   I(min)   I(max)
-1.8V     -850.6mA   -919.8mA   -794.9mA
-1.211V   -295.9mA   -368.1mA   -239.8mA
-1.194V   -281.1mA   -352.1mA   -225mA
-1.094V   -194.4mA   -265.2mA   -138.3mA
-1.042V   -149.3mA   -219.9mA   -100.9mA
-994.2mV  -114mA     -179.9mA   -66.73mA
-932.8mV  -68.64mA   -132.9mA   -39.03mA
-855.1mV  -27.32mA   -77mA      -24.04mA
-788.7mV  -11.29mA   -38.18mA   -18.21mA
-711.5mV  -7.93mA    -12.17mA   -11.43mA
-622.9mV  -5.252mA   -2.282mA   -4.702mA
3.6V      0A         0A         0A
[POWER Clamp]
|   Voltage   I(typ)   I(min)   I(max)
-1.8V     57.63mA    47.47mA    68.17mA
-1.53V    42.35mA    32.77mA    52.28mA
-1.304V   29.9mA     21.38mA    39.51mA
-1.107V   19.39mA    12.18mA    28.44mA
-950.2mV  11.34mA    5.937mA    19.65mA
-841.1mV  6.087mA    2.594mA    13.84mA
-742.8mV  2.214mA    832.3uA    8.709mA
-676.4mV  713.4uA    407.8uA    5.548mA
-579.1mV  409.4uA    146uA      1.625mA
-522.4mV  232.3uA    85.77uA    383.9uA
-397.1mV  3.3uA      2.805uA    3.026uA
3.6V      0A         0A         0A
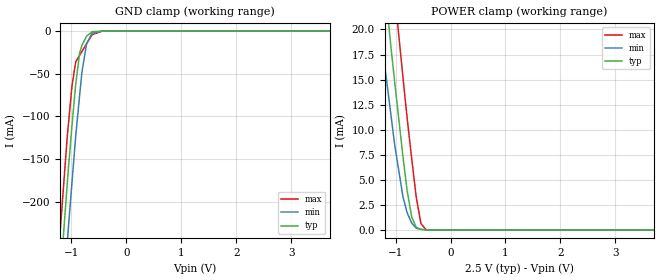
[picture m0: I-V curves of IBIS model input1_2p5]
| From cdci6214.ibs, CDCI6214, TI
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|   input1_2p5 Model
[Model]   input1_2p5
Model_type   Input
Vinl = 0.5
Vinh = 2
|   typ   min   max
C_comp   1.121E-12   1.110E-12   1.122E-12
|  Where Nom  PVT is Nominal Process, 2.5V,   32C
|   Fast PVT is Strong Process,  2.625V, -35C
|   Slow PVT is Weak Process,   2.375V, 110C
[Model spec]
|subparameter
Vinl   0.5   0.475   0.525
Vinh   2   1.9   2.1
[Voltage Range]   2.5   2.375   2.625
|Junction Temperature
[Temperature Range]   32   110   -35
[Power Clamp Reference]   2.5   2.375   2.625
[GND Clamp Reference]   0   0   0
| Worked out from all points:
|   GND clamp passes 1 mA (typ) near -0.63 V on its own axis
|   POWER clamp passes 1 mA (typ) near -0.68 V on its own axis
[GND Clamp]
|   Voltage   I(typ)   I(min)   I(max)
-2.5V     -1.532A    -1.598A    -1.479A
-1.239V   -321.1mA   -393.5mA   -264.1mA
-1.077V   -179.6mA   -249.4mA   -124.6mA
-1.054V   -159.9mA   -229.3mA   -108.8mA
-992.2mV  -112.3mA   -179.4mA   -65.54mA
-922.4mV  -62.71mA   -123.4mA   -36.03mA
-850.7mV  -25.69mA   -75.36mA   -28.38mA
-807.5mV  -16.42mA   -47.53mA   -23.78mA
-724.3mV  -6.007mA   -15.09mA   -14.9mA
-625mV    -777.4uA   -2.413mA   -4.32mA
-439.8mV  -8.3uA     -66.34uA   -28.2uA
5V        0A         0A         0A
[POWER Clamp]
|   Voltage   I(typ)   I(min)   I(max)
-2.5V     100mA      87.72mA    113.8mA
-1.434V   37.46mA    28.05mA    47.66mA
-1.195V   24.29mA    16.24mA    33.82mA
-1.086V   18.29mA    11.5mA     27.51mA
-1.016V   14.7mA     8.452mA    23.44mA
-866.8mV  7.343mA    3.322mA    15.26mA
-790mV    3.911mA    1.707mA    11.14mA
-706.7mV  1.283mA    686uA      7.096mA
-624.5mV  263.3uA    175.1uA    3.262mA
-538.8mV  74.48uA    52.1uA     635.2uA
-445mV    8.928uA    14.83uA    21.05uA
5V        0A         0A         0A
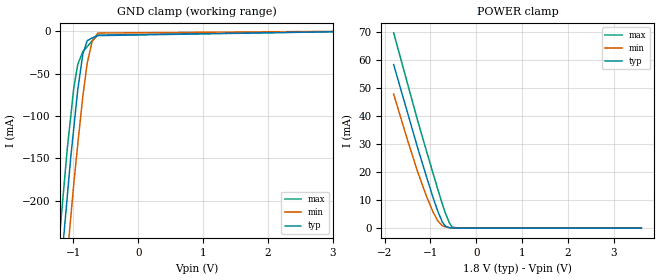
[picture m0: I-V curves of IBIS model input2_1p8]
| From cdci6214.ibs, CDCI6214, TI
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|   input2_1p8 Model
[Model]   input2_1p8
Model_type   Input
Vinl = 0.36
Vinh = 1.44
|   typ   min   max
C_comp   1.144E-12   1.136E-12   1.156E-12
|  Where Nom  PVT is Nominal Process, 1.8V,   32C
|   Fast PVT is Strong Process,  1.89V, -35C
|   Slow PVT is Weak Process,   1.71V, 110C
[Model spec]
|subparameter
Vinl   0.36   0.342   0.378
Vinh   1.44   1.368   1.512
[Voltage Range]   1.8   1.71   1.89
|Junction Temperature
[Temperature Range]   32   110   -35
[Power Clamp Reference]   1.8   1.71   1.89
[GND Clamp Reference]   0   0   0
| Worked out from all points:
|   GND clamp passes 1 mA (typ) near -0.48 V on its own axis
|   POWER clamp passes 1 mA (typ) near -0.69 V on its own axis
[GND Clamp]
|   Voltage   I(typ)   I(min)   I(max)
-1.8V     -850.6mA   -919.9mA   -794.9mA
-1.211V   -295.8mA   -368mA     -239.6mA
-1.194V   -280.9mA   -351.9mA   -224.8mA
-1.095V   -194.8mA   -265.6mA   -138.6mA
-1.042V   -149.5mA   -220.2mA   -101mA
-994.5mV  -114.3mA   -180.2mA   -66.94mA
-933mV    -68.82mA   -133.1mA   -39.2mA
-855.2mV  -27.45mA   -77.08mA   -24.26mA
-788.5mV  -11.34mA   -38.12mA   -18.34mA
-711.3mV  -8.021mA   -12.18mA   -11.5mA
-622.7mV  -5.309mA   -2.299mA   -4.735mA
3.6V      0A         0A         0A
[POWER Clamp]
|   Voltage   I(typ)   I(min)   I(max)
-1.8V     58.22mA    47.72mA    69.52mA
-1.492V   40.75mA    31.03mA    51.09mA
-1.28V    28.76mA    20.19mA    38.45mA
-1.091V   18.66mA    11.62mA    27.81mA
-949.4mV  11.31mA    6.012mA    19.97mA
-840.9mV  6.152mA    2.669mA    13.97mA
-743.4mV  2.298mA    892.5uA    8.824mA
-676.5mV  756.2uA    456.1uA    5.564mA
-583.1mV  153.4uA    168.1uA    1.762mA
-524.2mV  88.37uA    98.54uA    412.1uA
-397.8mV  2.505uA    3.408uA    3.145uA
3.6V      0A         0A         0A
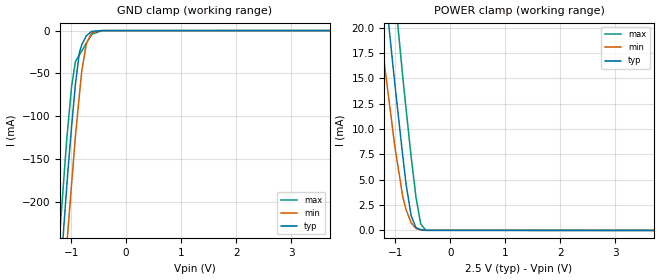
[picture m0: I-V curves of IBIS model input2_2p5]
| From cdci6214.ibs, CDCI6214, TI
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|   input2_2p5 Model
[Model]   input2_2p5
Model_type   Input
Vinl = 0.5
Vinh = 2
|   typ   min   max
C_comp   1.126E-12   1.120E-12   1.135E-12
|  Where Nom  PVT is Nominal Process, 2.5V,   32C
|   Fast PVT is Strong Process,  2.625V, -35C
|   Slow PVT is Weak Process,   2.375V, 110C
[Model spec]
|subparameter
Vinl   0.5   0.475   0.525
Vinh   2   1.9   2.1
[Voltage Range]   2.5   2.375   2.625
|Junction Temperature
[Temperature Range]   32   110   -35
[Power Clamp Reference]   2.5   2.375   2.625
[GND Clamp Reference]   0   0   0
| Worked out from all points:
|   GND clamp passes 1 mA (typ) near -0.63 V on its own axis
|   POWER clamp passes 1 mA (typ) near -0.68 V on its own axis
[GND Clamp]
|   Voltage   I(typ)   I(min)   I(max)
-2.5V     -1.532A    -1.598A    -1.479A
-1.239V   -321.3mA   -393.7mA   -264.3mA
-1.077V   -179.6mA   -249.3mA   -124.6mA
-1.054V   -160mA     -229.4mA   -108.9mA
-992.2mV  -112.3mA   -179.4mA   -65.56mA
-922.4mV  -62.83mA   -123.4mA   -36.15mA
-851.5mV  -26.07mA   -75.91mA   -28.57mA
-807.3mV  -16.5mA    -47.49mA   -23.85mA
-724.1mV  -6.114mA   -15.1mA    -14.95mA
-625mV    -806uA     -2.46mA    -4.354mA
-440.2mV  -9.242uA   -68.69uA   -28.71uA
5V        0A         0A         0A
[POWER Clamp]
|   Voltage   I(typ)   I(min)   I(max)
-2.5V     100mA      87.67mA    113.9mA
-1.408V   36.25mA    26.79mA    46.42mA
-1.241V   26.82mA    18.52mA    36.33mA
-1.195V   24.24mA    16.25mA    33.76mA
-1.009V   14.44mA    8.272mA    23.29mA
-865.1mV  7.358mA    3.332mA    15.16mA
-804.2mV  4.543mA    2.056mA    11.95mA
-712mV    1.443mA    750.5uA    7.242mA
-624.3mV  282.1uA    192.7uA    3.273mA
-539.2mV  83.31uA    59.41uA    647.8uA
-444.7mV  10.98uA    19.71uA    21.27uA
5V        0A         0A         0A
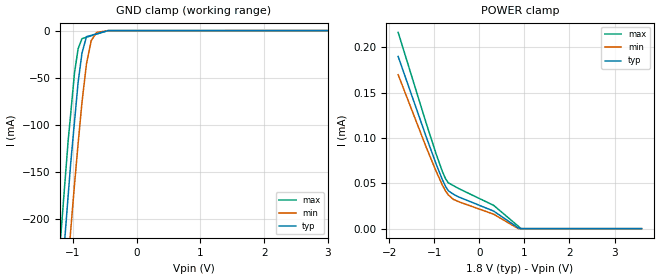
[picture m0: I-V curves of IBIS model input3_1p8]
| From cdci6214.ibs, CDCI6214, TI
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|   input3_1p8 Model
[Model]   input3_1p8
Model_type   Input
Vinl = 0.36
Vinh = 1.44
|   typ   min   max
C_comp   7.077E-13   6.859E-13   7.315E-13
|  Where Nom  PVT is Nominal Process, 1.8V,   32C
|   Fast PVT is Strong Process,  1.89V, -35C
|   Slow PVT is Weak Process,   1.71V, 110C
[Model spec]
|subparameter
Vinl   0.36   0.342   0.378
Vinh   1.44   1.368   1.512
[Voltage Range]   1.8   1.71   1.89
|Junction Temperature
[Temperature Range]   32   110   -35
[Power Clamp Reference]   1.8   1.71   1.89
[GND Clamp Reference]   0   0   0
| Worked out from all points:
|   GND clamp passes 1 mA (typ) near -0.50 V on its own axis
[GND Clamp]
|   Voltage   I(typ)   I(min)   I(max)
-1.8V     -850mA     -919.4mA   -793.9mA
-1.191V   -277.1mA   -348.8mA   -219mA
-1.074V   -175.3mA   -246.8mA   -116.9mA
-1.035V   -141.6mA   -213.1mA   -88.81mA
-974.7mV  -96.79mA   -163.6mA   -45.02mA
-918.6mV  -55.32mA   -120.6mA   -19.39mA
-857.6mV  -23.95mA   -76.41mA   -8.572mA
-787mV    -6.496mA   -35.31mA   -7.097mA
-712.5mV  -5.069mA   -10.66mA   -5.539mA
-628.3mV  -3.457mA   -1.946mA   -3.777mA
-449.9mV  -41.88uA   -73.76uA   -47.05uA
3.6V      0A         0A         0A
[POWER Clamp]
|   Voltage   I(typ)   I(min)   I(max)
-1.8V     190uA      169.9uA    216.6uA
-1.177V   101.2uA    89.74uA    116.2uA
-953.1mV  70.74uA    62.77uA    81.77uA
-821.9mV  54.38uA    48.37uA    63.4uA
-749.6mV  46.71uA    41.55uA    55.18uA
-688mV    41.83uA    37.28uA    50.6uA
-578mV    38.07uA    32.39uA    47.58uA
-449.5mV  34.79uA    29.57uA    44.06uA
318mV     19.42uA    15.97uA    25.72uA
865.4mV   806.9nA    0A         2.677uA
925.8mV   9.721nA    0A         0A
3.6V      0A         0A         0A
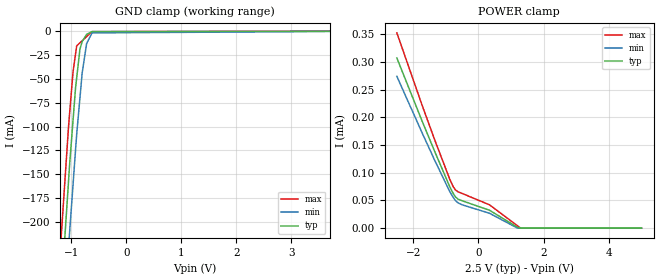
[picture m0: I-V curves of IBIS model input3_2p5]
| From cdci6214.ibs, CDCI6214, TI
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|   input3_2p5 Model
[Model]   input3_2p5
Model_type   Input
Vinl = 0.5
Vinh = 2
|   typ   min   max
C_comp   7.012E-13   6.818E-13   7.189E-13
|  Where Nom  PVT is Nominal Process, 2.5V,   32C
|   Fast PVT is Strong Process,  2.625V, -35C
|   Slow PVT is Weak Process,   2.375V, 110C
[Model spec]
|subparameter
Vinl   0.5   0.475   0.525
Vinh   2   1.9   2.1
[Voltage Range]   2.5   2.375   2.625
|Junction Temperature
[Temperature Range]   32   110   -35
[Power Clamp Reference]   2.5   2.375   2.625
[GND Clamp Reference]   0   0   0
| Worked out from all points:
|   GND clamp passes 1 mA (typ) near -0.64 V on its own axis
[GND Clamp]
|   Voltage   I(typ)   I(min)   I(max)
-2.5V     -1.532A    -1.598A    -1.479A
-1.226V   -308.3mA   -381.2mA   -249.3mA
-1.055V   -159.2mA   -229.4mA   -101.9mA
-1.034V   -140.4mA   -211.4mA   -86.68mA
-969.9mV  -92.79mA   -160.2mA   -42.22mA
-925.7mV  -59.87mA   -124.7mA   -24.3mA
-903.9mV  -48.73mA   -107.9mA   -15.44mA
-845.5mV  -18.94mA   -70.23mA   -12.33mA
-804.5mV  -10.92mA   -43.91mA   -10.15mA
-723.5mV  -3.448mA   -13.06mA   -5.833mA
-625mV    -502.3uA   -1.866mA   -589.3uA
5V        0A         0A         0A
[POWER Clamp]
|   Voltage   I(typ)   I(min)   I(max)
-2.5V     307.1uA    274uA      352.5uA
-1.724V   192.9uA    171.8uA    221.5uA
-1.337V   138uA      122.1uA    158.9uA
-880.6mV  75.19uA    66.32uA    88.67uA
-779.4mV  63.26uA    55.97uA    75.65uA
-705.1mV  56.51uA    49.87uA    68.96uA
-625mV    52.32uA    45.64uA    65.63uA
-485mV    49.14uA    41.89uA    62.3uA
336.4mV   32.43uA    26.98uA    42.26uA
1.2V      1.483uA    6.202nA    4.244uA
1.293V    5.759nA    459.9pA    19.82nA
5V        0A         0A         0A
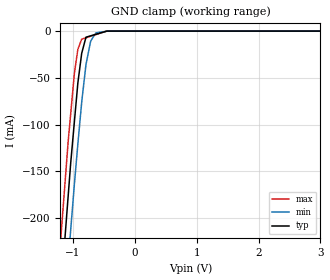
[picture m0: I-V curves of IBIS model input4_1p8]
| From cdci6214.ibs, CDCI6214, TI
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|   input4_1p8 Model
[Model]   input4_1p8
Model_type   Input
Vinl = 0.36
Vinh = 1.44
|   typ   min   max
C_comp   7.810E-13   7.465E-13   8.216E-13
|  Where Nom  PVT is Nominal Process, 1.8V,   32C
|   Fast PVT is Strong Process,  1.89V, -35C
|   Slow PVT is Weak Process,   1.71V, 110C
[Model spec]
|subparameter
Vinl   0.36   0.342   0.378
Vinh   1.44   1.368   1.512
[Voltage Range]   1.8   1.71   1.89
|Junction Temperature
[Temperature Range]   32   110   -35
[Power Clamp Reference]   1.8   1.71   1.89
[GND Clamp Reference]   0   0   0
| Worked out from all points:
|   GND clamp passes 1 mA (typ) near -0.50 V on its own axis
[GND Clamp]
|   Voltage   I(typ)   I(min)   I(max)
-1.8V     -850mA     -919.5mA   -793.9mA
-1.192V   -277.6mA   -349.3mA   -219.5mA
-1.074V   -175.4mA   -246.9mA   -117mA
-1.035V   -141.7mA   -213.2mA   -88.9mA
-974.7mV  -96.89mA   -163.7mA   -45.15mA
-918.6mV  -55.44mA   -120.7mA   -19.54mA
-857mV    -23.87mA   -76.24mA   -8.629mA
-787.6mV  -6.536mA   -35.7mA    -7.157mA
-712.5mV  -5.084mA   -10.78mA   -5.567mA
-627.7mV  -3.445mA   -1.949mA   -3.771mA
-449.9mV  -6.983uA   -45.43uA   -2.207uA
3.6V      0A         0A         0A
[POWER Clamp]
|   Voltage   I(typ)   I(min)   I(max)
-1.8V     0A         0A         0A
0V        0A         0A         0A
3.6V      0A         0A         0A
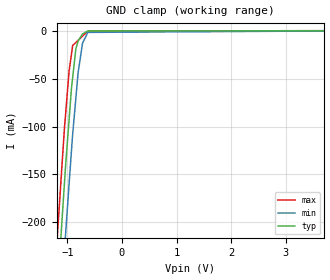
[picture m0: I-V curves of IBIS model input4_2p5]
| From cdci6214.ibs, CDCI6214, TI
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|   input4_2p5 Model
[Model]   input4_2p5
Model_type   Input
Vinl = 0.5
Vinh = 2
|   typ   min   max
C_comp   7.692E-13   7.376E-13   8.107E-13
|  Where Nom  PVT is Nominal Process, 2.5V,   32C
|   Fast PVT is Strong Process,  2.625V, -35C
|   Slow PVT is Weak Process,   2.375V, 110C
[Model spec]
|subparameter
Vinl   0.5   0.475   0.525
Vinh   2   1.9   2.1
[Voltage Range]   2.5   2.375   2.625
|Junction Temperature
[Temperature Range]   32   110   -35
[Power Clamp Reference]   2.5   2.375   2.625
[GND Clamp Reference]   0   0   0
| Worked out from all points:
|   GND clamp passes 1 mA (typ) near -0.64 V on its own axis
[GND Clamp]
|   Voltage   I(typ)   I(min)   I(max)
-2.5V     -1.532A    -1.598A    -1.479A
-1.226V   -308.3mA   -381.3mA   -249.4mA
-1.055V   -159.2mA   -229.4mA   -102mA
-1.034V   -141.1mA   -212.1mA   -87.29mA
-969.9mV  -92.91mA   -160.3mA   -42.34mA
-925.7mV  -59.98mA   -124.8mA   -24.42mA
-903.9mV  -48.84mA   -108mA     -15.57mA
-845.5mV  -19.06mA   -70.35mA   -12.42mA
-804.5mV  -11mA      -44.05mA   -10.21mA
-723.5mV  -3.469mA   -13.18mA   -5.844mA
-625mV    -460.6uA   -1.877mA   -535.5uA
5V        0A         0A         0A
[POWER Clamp]
|   Voltage   I(typ)   I(min)   I(max)
-2.5V     0A         0A         0A
0V        0A         0A         0A
5V        0A         0A         0A
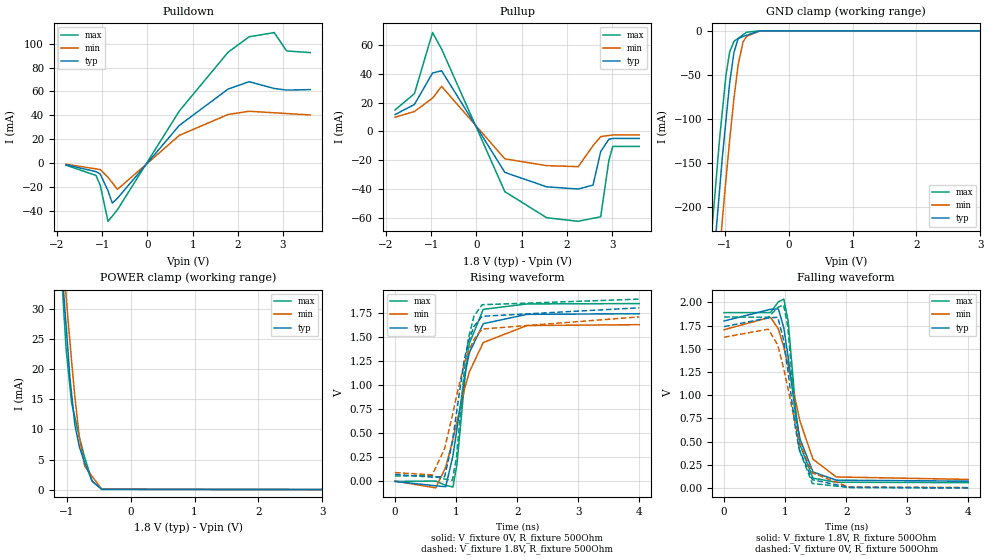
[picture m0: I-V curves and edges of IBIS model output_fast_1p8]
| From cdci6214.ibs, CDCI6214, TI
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|   output_fast_1p8 Model
[Model]   output_fast_1p8
Model_type   3-state
Polarity   Non-Inverting
Vmeas = 0.9
Vref = 0
Cref = 1pF
Rref = 100000
|   typ   min   max
C_comp   5.378E-12   5.266E-12   5.486E-12
|  Where Nom  PVT is Nominal Process, 1.8V,   32C
|   Fast PVT is Strong Process,  1.89V, -35C
|   Slow PVT is Weak Process,   1.71V, 110C
[Voltage Range]   1.8   1.71   1.89
|Junction Temperature
[Temperature Range]   32   110   -35
[Pullup Reference]   1.8   1.71   1.89
[Pulldown Reference]   0   0   0
[Power Clamp Reference]   1.8   1.71   1.89
[GND Clamp Reference]   0   0   0
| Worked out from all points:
|   slope of the pulldown table from 0 to 0.27 V, typ, clamps not added: 21.2 ohm
|   slope of the pullup table from 0 to 0.27 V, typ, clamps not added: 18.8 ohm
|   GND clamp passes 1 mA (typ) near -0.49 V on its own axis
|   POWER clamp passes 1 mA (typ) near -0.56 V on its own axis
|   falling waveform, V_fixture 1.8V, R_fixture 500Ohm: 20-80 % time 243ps typ, 353ps min, 166ps max; typ from 1.8 V to 0.072 V
|   rising waveform, V_fixture 0V, R_fixture 500Ohm: 20-80 % time 274ps typ, 408ps min, 185ps max; typ from 0 V to 1.74 V
|   rising waveform, V_fixture 1.8V, R_fixture 500Ohm: 20-80 % time 263ps typ, 382ps min, 180ps max; typ from 0.072 V to 1.8 V
|   falling waveform, V_fixture 0V, R_fixture 500Ohm: 20-80 % time 237ps typ, 345ps min, 164ps max; typ from 1.74 V to 0 V
[Pulldown]
|   Voltage   I(typ)   I(min)   I(max)
-1.8V     -1.429mA   -1.041mA   -1.873mA
-1.138V   -7.255mA   -4.932mA   -10.39mA
-1.043V   -9.203mA   -5.49mA    -18.75mA
-871.6mV  -23.26mA   -11.94mA   -48.89mA
-777.3mV  -33.66mA   -16.58mA   -44.53mA
-663.8mV  -29.58mA   -22.16mA   -39.27mA
705.6mV   31.53mA    23.17mA    43.61mA
1.784V    62.02mA    40.69mA    92.92mA
2.251V    68.2mA     43.4mA     105.9mA
2.806V    62.47mA    42.12mA    109.4mA
3.078V    61.16mA    41.49mA    93.99mA
3.6V      61.56mA    40.29mA    92.62mA
[GND Clamp]
|   Voltage   I(typ)   I(min)   I(max)
-1.8V     -850.3mA   -919.8mA   -794.3mA
-1.195V   -280.7mA   -352.5mA   -222.8mA
-1.078V   -180mA     -251.5mA   -121.9mA
-1.038V   -145.2mA   -216.6mA   -92.87mA
-979mV    -101.5mA   -168.3mA   -50.25mA
-921.2mV  -58.95mA   -124.1mA   -23.93mA
-854mV    -24.43mA   -76.46mA   -11.96mA
-789.1mV  -8.774mA   -38.54mA   -8.56mA
-711.9mV  -6.435mA   -12.56mA   -4.516mA
-656.6mV  -5.082mA   -6.334mA   -1.622mA
-449.5mV  -11.58uA   -68.88uA   -5.057uA
3.6V      0A         0A         0A
[Pullup]
|   Voltage   I(typ)   I(min)   I(max)
-1.8V     11.74mA    9.975mA    15.03mA
-1.371V   18.85mA    13.88mA    26.38mA
-970.4mV  40.76mA    23.23mA    68.93mA
-770.8mV  42.29mA    31.43mA    57.46mA
628.6mV   -28.53mA   -19.08mA   -41.94mA
1.553V    -38.57mA   -23.8mA    -60.12mA
2.251V    -40.11mA   -24.52mA   -62.6mA
2.579V    -37.37mA   -9.875mA   -60.52mA
2.748V    -14.06mA   -3.582mA   -59.46mA
2.928V    -5.429mA   -2.807mA   -20.34mA
3.014V    -4.849mA   -2.438mA   -10.45mA
3.6V      -4.849mA   -2.438mA   -10.45mA
[POWER Clamp]
|   Voltage   I(typ)   I(min)   I(max)
-1.8V     167.4mA    150.6mA    195.5mA
-1.068V   35.93mA    40.34mA    33.91mA
-1.024V   29.53mA    34.06mA    26.15mA
-1.007V   27.08mA    31.95mA    23.21mA
-948mV    18.56mA    24.56mA    17.08mA
-922.3mV  15.94mA    21.35mA    14.43mA
-871.8mV  10.83mA    15.52mA    12.06mA
-799.4mV  7.041mA    8.597mA    8.654mA
-715.7mV  4.424mA    3.843mA    5.27mA
-599.9mV  1.388mA    2.202mA    1.381mA
-449.3mV  60.13uA    68.13uA    32.65uA
3.6V      0A         0A         0A
[Ramp]
R_load = 500
|   typ   min   max
dV/dt_r   1.04327/2.7072e-10   0.972875/4.04951e-10   1.10651/1.8406e-10
dV/dt_f   1.03673/2.40063e-10   0.968624/3.50605e-10   1.10012/1.6435e-10
[Falling Waveform]
V_fixture = 1.8V
V_fixture_min = 1.71V
V_fixture_max = 1.89V
R_fixture = 500Ohm
C_fixture = 0F
|   Time   V(typ)   V(min)   V(max)
0s        1.8V       1.706V     1.89V
758.6ps   1.926V     1.841V     1.891V
889.6ps   1.931V     1.715V     2.007V
978.8ps   1.725V     1.519V     2.036V
1.049ns   1.414V     1.321V     1.803V
1.177ns   774.8mV    921.5mV    822.5mV
1.243ns   529.2mV    720.1mV    465mV
1.457ns   170.9mV    308.4mV    104.4mV
1.838ns   83.32mV    117.7mV    60.95mV
4ns       71.96mV    91.16mV    56.37mV
[Rising Waveform]
V_fixture = 0V
V_fixture_min = 0V
V_fixture_max = 0V
R_fixture = 500Ohm
C_fixture = 0F
|   Time   V(typ)   V(min)   V(max)
0s        67.37uV    3.546mV    45.41uV
666.6ps   -45.58mV   -66.82mV   3.956mV
829.6ps   -54.62mV   146.5mV    -40.81mV
947.8ps   263.9mV    435.2mV    -57.82mV
1.013ns   540.4mV    614.1mV    170.2mV
1.147ns   1.121V     979.9mV    1.091V
1.216ns   1.332V     1.134V     1.429V
1.445ns   1.635V     1.44V      1.784V
2.16ns    1.732V     1.616V     1.84V
4ns       1.739V     1.625V     1.844V
[Rising Waveform]
V_fixture = 1.8V
V_fixture_min = 1.71V
V_fixture_max = 1.89V
R_fixture = 500Ohm
C_fixture = 0F
|   Time   V(typ)   V(min)   V(max)
0s        71.96mV    91.16mV    56.37mV
610.6ps   44.48mV    67.63mV    59.83mV
811.6ps   48.32mV    339.5mV    24.76mV
938.8ps   404.9mV    684mV      11.25mV
1.006ns   708.7mV    881.5mV    246.3mV
1.133ns   1.26V      1.219V     1.142V
1.201ns   1.446V     1.346V     1.482V
1.293ns   1.608V     1.471V     1.714V
1.426ns   1.712V     1.58V      1.832V
4ns       1.8V       1.706V     1.89V
[Falling Waveform]
|Gnd
V_fixture = 0V
V_fixture_min = 0V
V_fixture_max = 0V
R_fixture = 500Ohm
C_fixture = 0F
|   Time   V(typ)   V(min)   V(max)
0s        1.739V     1.625V     1.844V
725.6ps   1.834V     1.712V     1.84V
880.6ps   1.84V      1.539V     1.947V
975.8ps   1.594V     1.29V      1.974V
1.044ns   1.268V     1.081V     1.74V
1.167ns   651.1mV    686.3mV    775mV
1.233ns   410.4mV    500.3mV    409.9mV
1.446ns   87.74mV    161.3mV    47.27mV
2.047ns   5.618mV    7.862mV    4.06mV
4ns       67.31uV    3.545mV    45.35uV
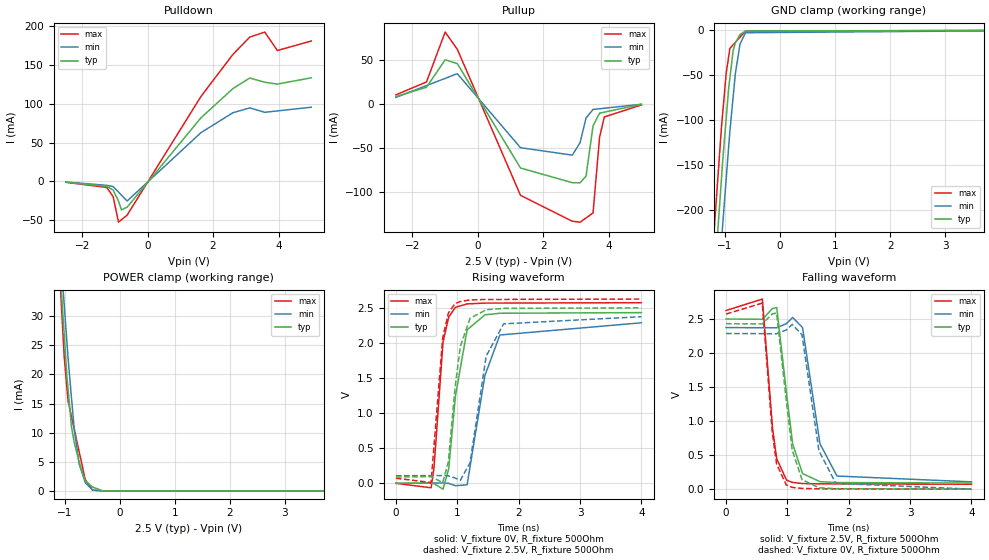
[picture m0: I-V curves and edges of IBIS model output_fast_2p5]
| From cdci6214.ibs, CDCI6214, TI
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|   output_fast_2p5 Model
[Model]   output_fast_2p5
Model_type   3-state
Polarity   Non-Inverting
Vmeas = 1.25
Vref = 1.25
Cref = 1pF
Rref = 100000
|   typ   min   max
C_comp   5.356E-12   5.258E-12   5.446E-12
|  Where Nom  PVT is Nominal Process, 2.5V,   32C
|   Fast PVT is Strong Process,  2.625V, -35C
|   Slow PVT is Weak Process,   2.375V, 110C
[Voltage Range]   2.5   2.375   2.625
|Junction Temperature
[Temperature Range]   32   110   -35
[Pullup Reference]   2.5   2.375   2.625
[Pulldown Reference]   0   0   0
[Power Clamp Reference]   2.5   2.375   2.625
[GND Clamp Reference]   0   0   0
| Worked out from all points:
|   slope of the pulldown table from 0 to 0.375 V, typ, clamps not added: 18.8 ohm
|   slope of the pullup table from 0 to 0.375 V, typ, clamps not added: 14.6 ohm
|   GND clamp passes 1 mA (typ) near -0.63 V on its own axis
|   POWER clamp passes 1 mA (typ) near -0.53 V on its own axis
|   falling waveform, V_fixture 2.5V, R_fixture 500Ohm: 20-80 % time 178ps typ, 236ps min, 131ps max; typ from 2.5 V to 0.09 V
|   rising waveform, V_fixture 0V, R_fixture 500Ohm: 20-80 % time 185ps typ, 260ps min, 131ps max; typ from 0 V to 2.43 V
|   rising waveform, V_fixture 2.5V, R_fixture 500Ohm: 20-80 % time 181ps typ, 251ps min, 129ps max; typ from 0.09 V to 2.5 V
|   falling waveform, V_fixture 0V, R_fixture 500Ohm: 20-80 % time 176ps typ, 232ps min, 130ps max; typ from 2.43 V to 0 V
[Pulldown]
|   Voltage   I(typ)   I(min)   I(max)
-2.5V     -895.1uA   -709uA     -1.088mA
-1.25V    -6.261mA   -5.001mA   -7.751mA
-1.054V   -11.08mA   -6.58mA    -19.46mA
-889.5mV  -25.19mA   -13.67mA   -52.41mA
-798.9mV  -36.66mA   -17.58mA   -49.29mA
-624.4mV  -33.04mA   -25.12mA   -43.25mA
1.631V    81.88mA    62.78mA    109.4mA
2.609V    119.5mA    88.42mA    163.5mA
3.12V     133mA      94.58mA    185.6mA
3.58V     127.6mA    88.95mA    192.1mA
3.965V    125.2mA    90.71mA    168.4mA
5V        133.3mA    95.46mA    180.6mA
[GND Clamp]
|   Voltage   I(typ)   I(min)   I(max)
-2.5V     -1.532A    -1.598A    -1.479A
-1.232V   -314.3mA   -387.3mA   -255.5mA
-1.061V   -165.3mA   -235.5mA   -108.2mA
-1.039V   -145.8mA   -216.9mA   -92.46mA
-975mV    -98.18mA   -165.6mA   -47.95mA
-929.4mV  -64.13mA   -129mA     -29.15mA
-907.5mV  -52.89mA   -112.1mA   -20.14mA
-847.7mV  -22.11mA   -73.5mA    -16.05mA
-807.4mV  -13.78mA   -47.61mA   -13.31mA
-724.1mV  -4.732mA   -15.34mA   -7.629mA
-624.9mV  -740.7uA   -2.664mA   -860.4uA
5V        0A         0A         0A
[Pullup]
|   Voltage   I(typ)   I(min)   I(max)
-2.5V     8.218mA    7.3mA      10.19mA
-1.566V   18.82mA    20.68mA    24.8mA
-995.3mV  49.93mA    28.85mA    81.37mA
-624.4mV  45.59mA    34.17mA    61.85mA
1.307V    -72.83mA   -49.79mA   -103.8mA
2.889V    -89.47mA   -58.24mA   -133.2mA
3.127V    -89.61mA   -44.13mA   -134.3mA
3.309V    -82.03mA   -16.11mA   -129.5mA
3.524V    -24.9mA    -6.412mA   -123.8mA
3.724V    -10.62mA   -5.61mA    -37.71mA
3.869V    -9.468mA   -5.024mA   -14.9mA
5V        -510.5uA   -478.4uA   -1.307mA
[POWER Clamp]
|   Voltage   I(typ)   I(min)   I(max)
-2.5V     298.9mA    261.5mA    358.6mA
-1.068V   35.89mA    40.1mA     33.64mA
-1.006V   26.8mA     31.93mA    23.03mA
-957.2mV  19.71mA    25.56mA    17.7mA
-936.8mV  17.58mA    22.89mA    15.47mA
-873.2mV  10.93mA    15.88mA    12.71mA
-821.6mV  8.215mA    10.42mA    10.49mA
-733.9mV  4.912mA    4.612mA    6.692mA
-624.8mV  1.737mA    1.418mA    1.975mA
-492mV    674.7uA    169.6uA    123.9uA
-303.9mV  867.5nA    9.329uA    5.86uA
5V        0A         0A         0A
[Ramp]
R_load = 500
|   typ   min   max
dV/dt_r   1.45904/1.82989e-10   1.37164/2.56905e-10   1.54371/1.30987e-10
dV/dt_f   1.4459/1.7538e-10   1.3599/2.33199e-10   1.53154/1.30508e-10
[Falling Waveform]
V_fixture = 2.5V
V_fixture_min = 2.375V
V_fixture_max = 2.625V
R_fixture = 500Ohm
C_fixture = 0F
|   Time   V(typ)   V(min)   V(max)
0s        2.5V       2.374V     2.625V
591.7ps   2.496V     2.372V     2.793V
757.9ps   2.655V     2.371V     893mV
825.9ps   2.667V     2.371V     445.4mV
986.9ps   1.397V     2.433V     132.2mV
1.086ns   659.4mV    2.523V     98.15mV
1.247ns   229.6mV    2.373V     82.9mV
1.531ns   109.9mV    667mV      77.67mV
1.808ns   96.92mV    193mV      77.08mV
4ns       89.92mV    107.5mV    72.4mV
[Rising Waveform]
V_fixture = 0V
V_fixture_min = 0V
V_fixture_max = 0V
R_fixture = 500Ohm
C_fixture = 0F
|   Time   V(typ)   V(min)   V(max)
0s        153.7uV    741.7uV    20.04uV
573.7ps   5.562mV    3.714mV    -63.49mV
620.7ps   -4.247mV   3.958mV    222.5mV
767.9ps   -83.28mV   4.72mV     2.014V
860.9ps   209.2mV    -646.1uV   2.37V
968.9ps   1.238V     -33.92mV   2.507V
1.16ns    2.186V     -21.6mV    2.556V
1.45ns    2.4V       1.535V     2.568V
1.694ns   2.423V     2.113V     2.568V
4ns       2.432V     2.287V     2.573V
[Rising Waveform]
V_fixture = 2.5V
V_fixture_min = 2.375V
V_fixture_max = 2.625V
R_fixture = 500Ohm
C_fixture = 0F
|   Time   V(typ)   V(min)   V(max)
0s        89.92mV    107.5mV    72.4mV
572.7ps   95.16mV    110.3mV    11.76mV
761.9ps   9.865mV    111.2mV    2.07V
853.9ps   299.7mV    106.7mV    2.424V
961.9ps   1.346V     76.22mV    2.56V
1.049ns   1.95V      41.8mV     2.59V
1.208ns   2.35V      293.4mV    2.612V
1.471ns   2.473V     1.813V     2.62V
1.755ns   2.492V     2.272V     2.62V
4ns       2.5V       2.374V     2.625V
[Falling Waveform]
|Gnd
V_fixture = 0V
V_fixture_min = 0V
V_fixture_max = 0V
R_fixture = 500Ohm
C_fixture = 0F
|   Time   V(typ)   V(min)   V(max)
0s        2.432V     2.287V     2.573V
590.7ps   2.428V     2.285V     2.734V
753.9ps   2.576V     2.284V     831.5mV
823.9ps   2.587V     2.284V     369.5mV
982.9ps   1.291V     2.339V     59.89mV
1.078ns   575.4mV    2.42V      26.82mV
1.238ns   140.8mV    2.268V     10.55mV
1.514ns   20.5mV     564.3mV    5.191mV
1.789ns   6.971mV    85.64mV    4.619mV
4ns       153.5uV    741.5uV    20.07uV
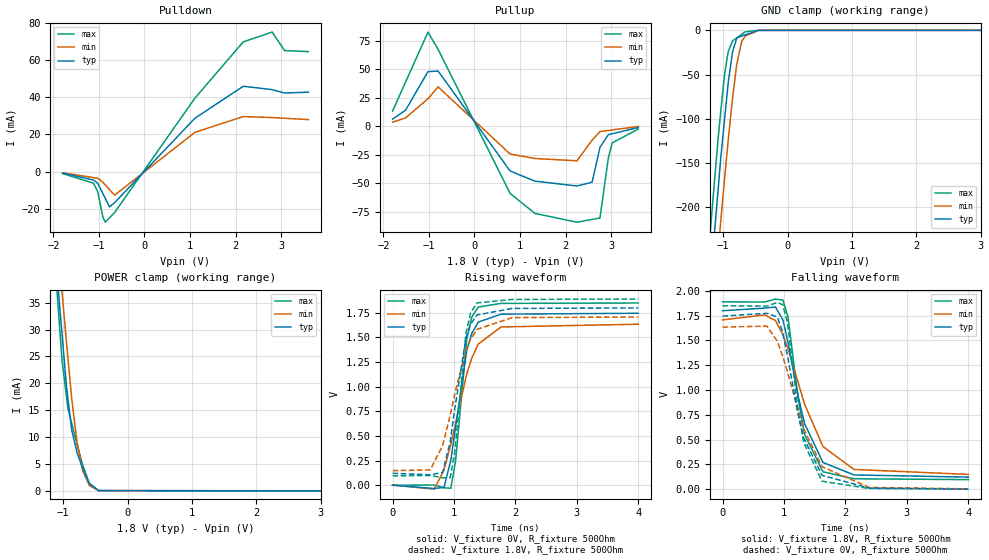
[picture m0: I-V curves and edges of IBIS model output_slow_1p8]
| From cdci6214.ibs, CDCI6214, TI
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|   output_slow_1p8 Model
[Model]   output_slow_1p8
Model_type   3-state
Polarity   Non-Inverting
Vmeas = 0.9
Vref = 0
Cref = 1pF
Rref = 100000
|   typ   min   max
C_comp   5.423E-12   5.344E-12   5.509E-12
|  Where Nom  PVT is Nominal Process, 1.8V,   32C
|   Fast PVT is Strong Process,  1.89V, -35C
|   Slow PVT is Weak Process,   1.71V, 110C
[Voltage Range]   1.8   1.71   1.89
|Junction Temperature
[Temperature Range]   32   110   -35
[Pullup Reference]   1.8   1.71   1.89
[Pulldown Reference]   0   0   0
[Power Clamp Reference]   1.8   1.71   1.89
[GND Clamp Reference]   0   0   0
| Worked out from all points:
|   slope of the pulldown table from 0 to 0.27 V, typ, clamps not added: 36.4 ohm
|   slope of the pullup table from 0 to 0.27 V, typ, clamps not added: 16.4 ohm
|   GND clamp passes 1 mA (typ) near -0.49 V on its own axis
|   POWER clamp passes 1 mA (typ) near -0.55 V on its own axis
|   falling waveform, V_fixture 1.8V, R_fixture 500Ohm: 20-80 % time 374ps typ, 527ps min, 267ps max; typ from 1.8 V to 0.122 V
|   rising waveform, V_fixture 0V, R_fixture 500Ohm: 20-80 % time 247ps typ, 385ps min, 163ps max; typ from 0 V to 1.75 V
|   rising waveform, V_fixture 1.8V, R_fixture 500Ohm: 20-80 % time 240ps typ, 368ps min, 159ps max; typ from 0.122 V to 1.8 V
|   falling waveform, V_fixture 0V, R_fixture 500Ohm: 20-80 % time 368ps typ, 512ps min, 264ps max; typ from 1.75 V to 0 V
[Pulldown]
|   Voltage   I(typ)   I(min)   I(max)
-1.8V     -798.5uA   -598.9uA   -1.02mA
-1.122V   -4.493mA   -3.197mA   -6.184mA
-1.027V   -6.266mA   -3.561mA   -10.8mA
-914.2mV  -11.79mA   -5.684mA   -24.5mA
-860.8mV  -14.43mA   -7.136mA   -27.17mA
-769mV    -18.94mA   -9.628mA   -24.85mA
-657.9mV  -16.72mA   -12.65mA   -22.04mA
1.107V    28.68mA    21.1mA     39.49mA
2.169V    45.9mA     29.61mA    69.73mA
2.805V    44.09mA    29.08mA    75.02mA
3.077V    42.25mA    28.7mA     65.07mA
3.6V      42.75mA    27.98mA    64.52mA
[GND Clamp]
|   Voltage   I(typ)   I(min)   I(max)
-1.8V     -850.3mA   -919.8mA   -794.3mA
-1.195V   -280.7mA   -352.5mA   -222.8mA
-1.078V   -180mA     -251.5mA   -121.9mA
-1.038V   -145mA     -216.4mA   -92.72mA
-979mV    -101.5mA   -168.3mA   -50.25mA
-921.2mV  -58.93mA   -124.1mA   -23.93mA
-853.8mV  -24.35mA   -76.34mA   -11.95mA
-789.1mV  -8.796mA   -38.54mA   -8.56mA
-711.9mV  -6.416mA   -12.56mA   -4.516mA
-656.6mV  -5.066mA   -6.335mA   -1.622mA
-449.5mV  -11.66uA   -68.88uA   -3.663uA
3.6V      0A         0A         0A
[Pullup]
|   Voltage   I(typ)   I(min)   I(max)
-1.8V     6.344mA    3.636mA    13.35mA
-1.515V   14.15mA    7.33mA     38.85mA
-1.022V   48.07mA    24.23mA    82.87mA
-798.3mV  48.6mA     34.69mA    67.58mA
782.5mV   -39.32mA   -24.38mA   -59.01mA
1.327V    -48.23mA   -28.31mA   -76.6mA
2.25V     -52.48mA   -30.35mA   -84.34mA
2.584V    -49.19mA   -12.25mA   -81.9mA
2.757V    -18.48mA   -4.627mA   -80.64mA
2.942V    -7.341mA   -3.641mA   -27.64mA
3.026V    -6.541mA   -3.196mA   -14.62mA
3.6V      -1.069mA   -154.4uA   -2.333mA
[POWER Clamp]
|   Voltage   I(typ)   I(min)   I(max)
-1.8V     164.6mA    152mA      188.4mA
-1.122V   45.18mA    50.88mA    41.63mA
-1.064V   35.72mA    43.16mA    31.98mA
-1.019V   29.39mA    37.15mA    24.5mA
-948.3mV  19.43mA    27.69mA    17.48mA
-927.2mV  17.32mA    24.86mA    15.38mA
-866.8mV  11.34mA    17.14mA    12.57mA
-783.2mV  7.085mA    8.98mA     8.668mA
-697.3mV  4.254mA    3.781mA    4.834mA
-593.6mV  1.368mA    1.009mA    1.43mA
-449.8mV  61.34uA    71.23uA    33.34uA
3.6V      0A         0A         0A
[Ramp]
R_load = 500
|   typ   min   max
dV/dt_r   1.04729/2.45673e-10   0.978992/3.81781e-10   1.10983/1.62638e-10
dV/dt_f   1.00694/3.725e-10   0.935443/5.23127e-10   1.07604/2.64801e-10
[Falling Waveform]
V_fixture = 1.8V
V_fixture_min = 1.71V
V_fixture_max = 1.89V
R_fixture = 500Ohm
C_fixture = 0F
|   Time   V(typ)   V(min)   V(max)
0s        1.8V       1.708V     1.89V
686.1ps   1.827V     1.758V     1.888V
861ps     1.838V     1.701V     1.918V
983.3ps   1.705V     1.558V     1.907V
1.067ns   1.477V     1.411V     1.73V
1.232ns   933.2mV    1.073V     909.8mV
1.334ns   662.7mV    858.7mV    552.6mV
1.634ns   269.1mV    429.8mV    175.3mV
2.14ns    143.6mV    198.8mV    104.8mV
4ns       121.6mV    149mV      96.52mV
[Rising Waveform]
V_fixture = 0V
V_fixture_min = 0V
V_fixture_max = 0V
R_fixture = 500Ohm
C_fixture = 0F
|   Time   V(typ)   V(min)   V(max)
0s        361.2uV    3.365mV    111.5uV
677.1ps   -32.61mV   -39.36mV   3.246mV
837ps     -21.55mV   154.1mV    -25.86mV
948.8ps   256.1mV    417.1mV    -29.85mV
1.025ns   590.2mV    628mV      246.5mV
1.208ns   1.369V     1.133V     1.483V
1.287ns   1.537V     1.287V     1.705V
1.394ns   1.656V     1.433V     1.809V
1.766ns   1.737V     1.607V     1.846V
4ns       1.746V     1.635V     1.85V
[Rising Waveform]
V_fixture = 1.8V
V_fixture_min = 1.71V
V_fixture_max = 1.89V
R_fixture = 500Ohm
C_fixture = 0F
|   Time   V(typ)   V(min)   V(max)
0s        121.6mV    149mV      96.52mV
612.1ps   106.3mV    155.9mV    98.98mV
815ps     130.5mV    402.6mV    76.36mV
937.4ps   439.6mV    708.8mV    76.98mV
1.015ns   787.4mV    933.4mV    347.5mV
1.194ns   1.492V     1.371V     1.541V
1.271ns   1.636V     1.483V     1.752V
1.376ns   1.729V     1.583V     1.851V
1.945ns   1.795V     1.702V     1.886V
4ns       1.8V       1.708V     1.89V
[Falling Waveform]
|Gnd
V_fixture = 0V
V_fixture_min = 0V
V_fixture_max = 0V
R_fixture = 500Ohm
C_fixture = 0F
|   Time   V(typ)   V(min)   V(max)
0s        1.746V     1.635V     1.85V
721.8ps   1.774V     1.645V     1.848V
892ps     1.737V     1.492V     1.883V
977.3ps   1.585V     1.344V     1.861V
1.056ns   1.349V     1.184V     1.685V
1.22ns    779.6mV    819.5mV    836.5mV
1.32ns    517.3mV    610.4mV    471.4mV
1.619ns   139.3mV    226.7mV    80.24mV
2.384ns   11.51mV    17.84mV    7.279mV
4ns       361.1uV    3.365mV    112.3uV
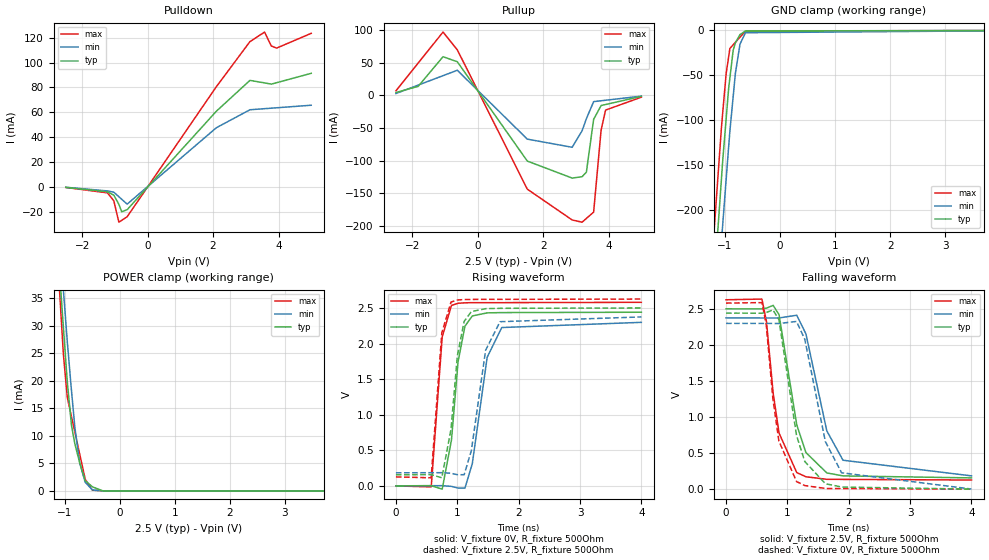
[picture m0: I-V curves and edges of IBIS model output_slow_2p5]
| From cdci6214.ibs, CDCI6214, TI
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|   output_slow_2p5 Model
[Model]   output_slow_2p5
Model_type   3-state
Polarity   Non-Inverting
Vmeas = 1.25
Vref = 0
Cref = 1pF
Rref = 100000
|   typ   min   max
C_comp   5.393E-12   5.319E-12   5.466E-12
|  Where Nom  PVT is Nominal Process, 2.5V,   32C
|   Fast PVT is Strong Process,  2.625V, -35C
|   Slow PVT is Weak Process,   2.375V, 110C
[Voltage Range]   2.5   2.375   2.625
|Junction Temperature
[Temperature Range]   32   110   -35
[Pullup Reference]   2.5   2.375   2.625
[Pulldown Reference]   0   0   0
[Power Clamp Reference]   2.5   2.375   2.625
[GND Clamp Reference]   0   0   0
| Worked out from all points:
|   slope of the pulldown table from 0 to 0.375 V, typ, clamps not added: 33.4 ohm
|   slope of the pullup table from 0 to 0.375 V, typ, clamps not added: 12.6 ohm
|   GND clamp passes 1 mA (typ) near -0.63 V on its own axis
|   POWER clamp passes 1 mA (typ) near -0.52 V on its own axis
|   falling waveform, V_fixture 2.5V, R_fixture 500Ohm: 20-80 % time 295ps typ, 380ps min, 225ps max; typ from 2.5 V to 0.156 V
|   rising waveform, V_fixture 0V, R_fixture 500Ohm: 20-80 % time 156ps typ, 228ps min, 111ps max; typ from 0 V to 2.44 V
|   rising waveform, V_fixture 2.5V, R_fixture 500Ohm: 20-80 % time 154ps typ, 221ps min, 109ps max; typ from 0.156 V to 2.5 V
|   falling waveform, V_fixture 0V, R_fixture 500Ohm: 20-80 % time 292ps typ, 374ps min, 224ps max; typ from 2.44 V to 0 V
[Pulldown]
|   Voltage   I(typ)   I(min)   I(max)
-2.5V     -488uA     -394.6uA   -583.2uA
-1.226V   -4.075mA   -3.352mA   -4.901mA
-1.032V   -6.799mA   -4.398mA   -11.4mA
-878.3mV  -14.13mA   -8.021mA   -28.54mA
-790.7mV  -20.13mA   -10.09mA   -27.02mA
-624.9mV  -18.46mA   -13.99mA   -24.14mA
2.102V    60.88mA    47.57mA    80.65mA
3.127V    85.68mA    62.03mA    116.9mA
3.574V    83.69mA    62.9mA     124.6mA
3.78V     82.67mA    63.3mA     113.4mA
3.942V    83.83mA    63.62mA    111.7mA
5V        91.39mA    65.68mA    123.6mA
[GND Clamp]
|   Voltage   I(typ)   I(min)   I(max)
-2.5V     -1.532A    -1.598A    -1.479A
-1.232V   -314.3mA   -387.3mA   -255.5mA
-1.061V   -165.3mA   -235.5mA   -108.2mA
-1.039V   -145.8mA   -216.9mA   -92.46mA
-975.1mV  -98.18mA   -165.6mA   -47.95mA
-929.4mV  -64.13mA   -129mA     -29.15mA
-907.6mV  -52.89mA   -112.1mA   -20.14mA
-847.7mV  -22.11mA   -73.5mA    -16.05mA
-807.4mV  -13.78mA   -47.61mA   -13.31mA
-724.1mV  -4.732mA   -15.34mA   -7.629mA
-624.9mV  -740.7uA   -2.664mA   -860.2uA
5V        0A         0A         0A
[Pullup]
|   Voltage   I(typ)   I(min)   I(max)
-2.5V     4.567mA    2.964mA    7.103mA
-1.82V    13.94mA    15.92mA    49.75mA
-1.061V   59.47mA    30.37mA    97.28mA
-624.4mV  51.77mA    38.69mA    70.07mA
1.515V    -100.7mA   -67.02mA   -143.8mA
2.886V    -126.8mA   -79.54mA   -191.1mA
3.189V    -124.7mA   -54.25mA   -194.5mA
3.32V     -117.7mA   -35.68mA   -188.7mA
3.542V    -36.57mA   -9.457mA   -179mA
3.77V     -15.45mA   -8.133mA   -53.23mA
3.907V    -13.88mA   -7.335mA   -22.42mA
5V        -1.374mA   -998.4uA   -2.598mA
[POWER Clamp]
|   Voltage   I(typ)   I(min)   I(max)
-2.5V     293.6mA    261.2mA    348.1mA
-1.112V   43.55mA    49.08mA    39.77mA
-1.07V    36.74mA    43mA       32.95mA
-1.022V   29.83mA    36.62mA    24.97mA
-949.6mV  19.77mA    27.06mA    16.95mA
-873.9mV  11.88mA    18.18mA    13.49mA
-812.6mV  8.542mA    11.52mA    10.7mA
-724.1mV  5.082mA    5.054mA    6.655mA
-624.8mV  1.867mA    1.572mA    2.12mA
-495.1mV  749.9uA    184.3uA    136.7uA
-303.9mV  867.6nA    10.12uA    5.866uA
5V        0A         0A         0A
[Ramp]
R_load = 500
|   typ   min   max
dV/dt_r   1.46405/1.56024e-10   1.37759/2.24938e-10   1.54754/1.09999e-10
dV/dt_f   1.40616/2.94488e-10   1.31391/3.77975e-10   1.49896/2.23098e-10
[Falling Waveform]
V_fixture = 2.5V
V_fixture_min = 2.375V
V_fixture_max = 2.625V
R_fixture = 500Ohm
C_fixture = 0F
|   Time   V(typ)   V(min)   V(max)
0s        2.5V       2.374V     2.625V
584.2ps   2.498V     2.373V     2.635V
658.2ps   2.509V     2.373V     2.326V
768.2ps   2.547V     2.373V     1.33V
864.1ps   2.418V     2.373V     776.9mV
1.152ns   892.6mV    2.411V     230.1mV
1.302ns   507.4mV    2.152V     172.1mV
1.642ns   225.5mV    808.4mV    136.5mV
1.906ns   183.9mV    401.1mV    135.4mV
4ns       156.2mV    184.4mV    126.7mV
[Rising Waveform]
V_fixture = 0V
V_fixture_min = 0V
V_fixture_max = 0V
R_fixture = 500Ohm
C_fixture = 0F
|   Time   V(typ)   V(min)   V(max)
0s        372.8uV    1.696mV    49.63uV
575.2ps   3.478mV    3.049mV    -13.78mV
754.2ps   -45.58mV   3.47mV     2.093V
905.2ps   645.9mV    -6.292mV   2.535V
1.013ns   1.746V     -30.47mV   2.566V
1.125ns   2.244V     -30.06mV   2.572V
1.245ns   2.388V     314.1mV    2.575V
1.487ns   2.431V     1.807V     2.575V
1.725ns   2.435V     2.225V     2.575V
4ns       2.44V      2.298V     2.579V
[Rising Waveform]
V_fixture = 2.5V
V_fixture_min = 2.375V
V_fixture_max = 2.625V
R_fixture = 500Ohm
C_fixture = 0F
|   Time   V(typ)   V(min)   V(max)
0s        156.2mV    184.4mV    126.7mV
574.2ps   159.2mV    185.6mV    114.3mV
748.2ps   114.3mV    186mV      2.152V
898.2ps   799.1mV    177.8mV    2.583V
1.001ns   1.827V     157.5mV    2.612V
1.112ns   2.311V     157.4mV    2.618V
1.229ns   2.449V     494.8mV    2.62V
1.462ns   2.49V      1.907V     2.621V
1.697ns   2.495V     2.307V     2.621V
4ns       2.5V       2.374V     2.625V
[Falling Waveform]
|Gnd
V_fixture = 0V
V_fixture_min = 0V
V_fixture_max = 0V
R_fixture = 500Ohm
C_fixture = 0F
|   Time   V(typ)   V(min)   V(max)
0s        2.44V      2.298V     2.579V
584.2ps   2.439V     2.297V     2.586V
654.2ps   2.448V     2.297V     2.285V
764.2ps   2.485V     2.297V     1.247V
861.1ps   2.351V     2.296V     667.4mV
1.149ns   743.2mV    2.325V     105.5mV
1.283ns   384mV      2.077V     50.27mV
1.619ns   75.34mV    659.1mV    10.02mV
1.883ns   29.79mV    227.3mV    8.911mV
4ns       372.1uV    1.696mV    49.63uV
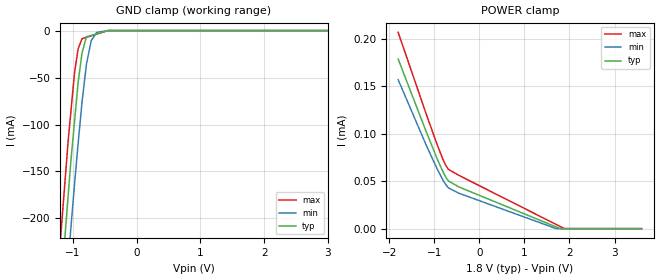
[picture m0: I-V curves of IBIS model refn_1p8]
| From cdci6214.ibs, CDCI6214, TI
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|   refn_1p8 Model
[Model]   refn_1p8
Model_type   Input
Vinl = 0.36
Vinh = 1.44
|   typ   min   max
C_comp   7.622E-13   7.126E-13   8.185E-13
|  Where Nom  PVT is Nominal Process, 1.8V,   32C
|   Fast PVT is Strong Process,  1.89V, -35C
|   Slow PVT is Weak Process,   1.71V, 110C
[Model spec]
|subparameter
Vinl   0.36   0.342   0.378
Vinh   1.44   1.368   1.512
[Voltage Range]   1.8   1.71   1.89
|Junction Temperature
[Temperature Range]   32   110   -35
[Power Clamp Reference]   1.8   1.71   1.89
[GND Clamp Reference]   0   0   0
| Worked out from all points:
|   GND clamp passes 1 mA (typ) near -0.50 V on its own axis
[GND Clamp]
|   Voltage   I(typ)   I(min)   I(max)
-1.8V     -850mA     -919.5mA   -793.9mA
-1.192V   -277.7mA   -349.4mA   -219.6mA
-1.074V   -175.5mA   -247mA     -117.1mA
-1.035V   -141.5mA   -213mA     -88.77mA
-974.7mV  -96.89mA   -163.7mA   -45.17mA
-918.9mV  -55.72mA   -120.9mA   -19.68mA
-857.2mV  -23.92mA   -76.38mA   -8.687mA
-787.8mV  -6.567mA   -35.79mA   -7.209mA
-712.8mV  -5.114mA   -10.83mA   -5.612mA
-628.1mV  -3.47mA    -1.964mA   -3.807mA
-450mV    -15.78uA   -50.43uA   -13.01uA
3.6V      0A         0A         0A
[POWER Clamp]
|   Voltage   I(typ)   I(min)   I(max)
-1.8V     178.7uA    156.9uA    206.8uA
-1.178V   102.2uA    88uA       120.8uA
-941.9mV  74.39uA    63.61uA    89.42uA
-807.3mV  60.02uA    51.26uA    73.05uA
-738.3mV  53.81uA    46.05uA    66.14uA
-681.7mV  50.14uA    42.87uA    62.37uA
-450mV    43.88uA    37.28uA    56.09uA
1.71V     1.76uA     31.69pA    4.323uA
1.8V      845.5pA    13.21pA    2.163uA
1.89V     0A         0A         1.147nA
3.6V      0A         0A         0A
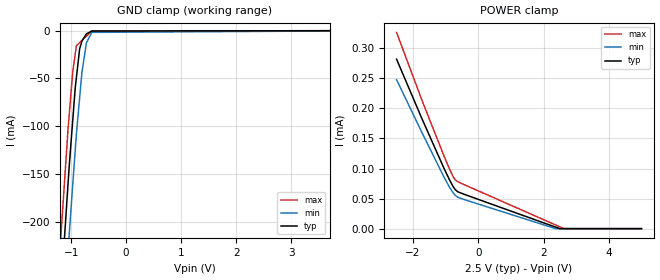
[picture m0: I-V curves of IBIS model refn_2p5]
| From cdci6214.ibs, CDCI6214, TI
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|   refn_2p5 Model
[Model]   refn_2p5
Model_type   Input
Vinl = 0.5
Vinh = 2
|   typ   min   max
C_comp   7.555E-13   7.087E-13   8.040E-13
|  Where Nom  PVT is Nominal Process, 2.5V,   32C
|   Fast PVT is Strong Process,  2.625, -35C
|   Slow PVT is Weak Process,   2.375V, 110C
[Model spec]
|subparameter
Vinl   0.5   0.475   0.525
Vinh   2   1.9   2.1
[Voltage Range]   2.5   2.375   2.625
|Junction Temperature
[Temperature Range]   32   110   -35
[Power Clamp Reference]   2.5   2.375   2.625
[GND Clamp Reference]   0   0   0
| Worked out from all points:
|   GND clamp passes 1 mA (typ) near -0.64 V on its own axis
[GND Clamp]
|   Voltage   I(typ)   I(min)   I(max)
-2.5V     -1.532A    -1.598A    -1.479A
-1.227V   -309mA     -381.9mA   -250.1mA
-1.056V   -159.9mA   -230.1mA   -102.6mA
-1.034V   -141.1mA   -212.1mA   -87.34mA
-970.6mV  -93.47mA   -160.9mA   -42.8mA
-925.7mV  -59.98mA   -124.8mA   -24.41mA
-904.6mV  -49.24mA   -108.4mA   -15.78mA
-845.5mV  -19.07mA   -70.33mA   -12.56mA
-804.5mV  -11.02mA   -44.03mA   -10.33mA
-723.5mV  -3.484mA   -13.16mA   -5.916mA
-625mV    -472.4uA   -1.879mA   -549.8uA
5V        0A         0A         0A
[POWER Clamp]
|   Voltage   I(typ)   I(min)   I(max)
-2.5V     281.7uA    247.7uA    326.3uA
-1.738V   184.6uA    161.4uA    215.5uA
-1.049V   100.4uA    85.77uA    121uA
-881.4mV  81.33uA    69.15uA    99.39uA
-773.4mV  70.42uA    59.95uA    87.01uA
-702.1mV  64.78uA    55.25uA    81.06uA
-625mV    61.26uA    52.17uA    77.96uA
-410.5mV  56.72uA    48.02uA    72.73uA
2.374V    2.451uA    5.962nA    6.013uA
2.499V    13.2nA     3.623nA    3.019uA
2.624V    0A         1.273nA    10.91nA
5V        0A         0A         0A
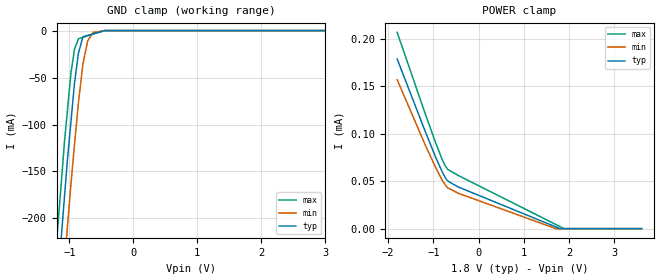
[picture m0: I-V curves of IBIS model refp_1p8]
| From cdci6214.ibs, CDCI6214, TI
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|   refp_1p8 Model
[Model]   refp_1p8
Model_type   Input
Vinl = 0.36
Vinh = 1.44
|   typ   min   max
C_comp   7.548E-13   7.100E-13   8.069E-13
|  Where Nom  PVT is Nominal Process, 1.8V,   32C
|   Fast PVT is Strong Process,  1.89V, -35C
|   Slow PVT is Weak Process,   1.71V, 110C
[Model spec]
|subparameter
Vinl   0.36   0.342   0.378
Vinh   1.44   1.368   1.512
[Voltage Range]   1.8   1.71   1.89
|Junction Temperature
[Temperature Range]   32   110   -35
[Power Clamp Reference]   1.8   1.71   1.89
[GND Clamp Reference]   0   0   0
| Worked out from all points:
|   GND clamp passes 1 mA (typ) near -0.50 V on its own axis
[GND Clamp]
|   Voltage   I(typ)   I(min)   I(max)
-1.8V     -850mA     -919.5mA   -793.9mA
-1.192V   -277.6mA   -349.3mA   -219.5mA
-1.074V   -175.4mA   -246.9mA   -117mA
-1.035V   -141.7mA   -213.2mA   -88.92mA
-974.7mV  -96.89mA   -163.7mA   -45.17mA
-918.6mV  -55.48mA   -120.7mA   -19.61mA
-857mV    -23.88mA   -76.23mA   -8.674mA
-787.6mV  -6.555mA   -35.68mA   -7.196mA
-713mV    -5.112mA   -10.88mA   -5.611mA
-628.3mV  -3.47mA    -1.974mA   -3.808mA
-449.9mV  -15.77uA   -53.14uA   -13uA
3.6V      0A         0A         0A
[POWER Clamp]
|   Voltage   I(typ)   I(min)   I(max)
-1.8V     178.7uA    156.9uA    206.8uA
-1.178V   102.2uA    87.98uA    120.8uA
-941.8mV  74.41uA    63.62uA    89.41uA
-806.3mV  59.95uA    51.19uA    72.94uA
-738.2mV  53.81uA    46.07uA    66.12uA
-681.5mV  50.14uA    42.87uA    62.36uA
-449.9mV  43.9uA     37.3uA     56.09uA
1.709V    1.763uA    2.033nA    4.326uA
1.799V    7.689nA    1.236nA    2.172uA
1.889V    0A         434.5pA    5.717nA
3.6V      0A         0A         0A
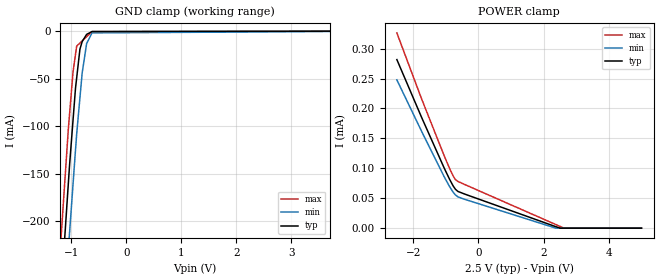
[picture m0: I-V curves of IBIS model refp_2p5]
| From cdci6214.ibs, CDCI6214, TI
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|   refp_2p5 Model
[Model]   refp_2p5
Model_type   Input
Vinl = 0.5
Vinh = 2
|   typ   min   max
C_comp   7.475E-13   7.057E-13   7.918E-13
|  Where Nom  PVT is Nominal Process, 2.5V,   32C
|   Fast PVT is Strong Process,  2.625, -35C
|   Slow PVT is Weak Process,   2.375V, 110C
[Model spec]
|subparameter
Vinl   0.5   0.475   0.525
Vinh   2   1.9   2.1
[Voltage Range]   2.5   2.375   2.625
|Junction Temperature
[Temperature Range]   32   110   -35
[Power Clamp Reference]   2.5   2.375   2.625
[GND Clamp Reference]   0   0   0
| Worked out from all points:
|   GND clamp passes 1 mA (typ) near -0.64 V on its own axis
[GND Clamp]
|   Voltage   I(typ)   I(min)   I(max)
-2.5V     -1.532A    -1.598A    -1.479A
-1.227V   -309mA     -381.9mA   -250.1mA
-1.056V   -159.9mA   -230.1mA   -102.6mA
-1.034V   -141.1mA   -212.1mA   -87.34mA
-970.6mV  -93.47mA   -160.9mA   -42.8mA
-925.7mV  -59.99mA   -124.8mA   -24.41mA
-904.6mV  -49.24mA   -108.4mA   -15.79mA
-845.5mV  -19.08mA   -70.33mA   -12.56mA
-804.5mV  -11.02mA   -44.03mA   -10.33mA
-723.5mV  -3.485mA   -13.16mA   -5.917mA
-625mV    -472.5uA   -1.881mA   -549.8uA
5V        0A         0A         0A
[POWER Clamp]
|   Voltage   I(typ)   I(min)   I(max)
-2.5V     281.7uA    247.8uA    326.3uA
-1.738V   184.6uA    161.4uA    215.5uA
-1.049V   100.4uA    85.81uA    121uA
-881.4mV  81.36uA    69.19uA    99.39uA
-773.4mV  70.45uA    59.99uA    87.01uA
-702.1mV  64.81uA    55.29uA    81.05uA
-625mV    61.28uA    52.2uA     77.96uA
-410.5mV  56.75uA    48.04uA    72.73uA
2.374V    2.451uA    5.211nA    6.012uA
2.499V    12.42nA    3.167nA    3.018uA
2.624V    0A         1.113nA    10.07nA
5V        0A         0A         0A
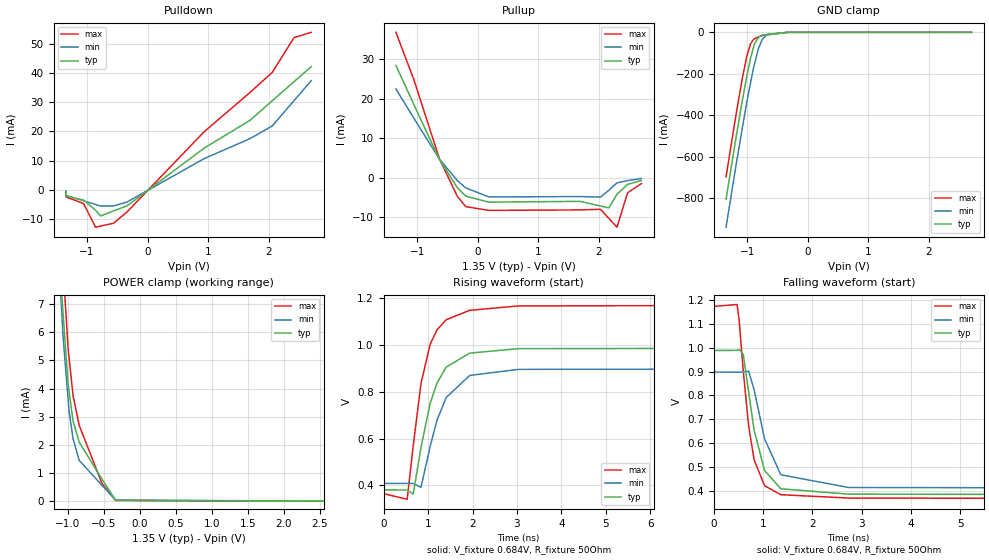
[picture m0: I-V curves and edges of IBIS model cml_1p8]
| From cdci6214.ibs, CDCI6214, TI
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|   cml_1p8 Model
[Model]   cml_1p8
Model_type   3-state
Polarity   Non-Inverting
Vmeas = 0.7
Vref = 0.684
Cref = 2pF
Rref = 50
|   typ   min   max
C_comp   7.009E-12   6.881E-12   7.205E-12
|  Where Nom  PVT is Nominal Process, 1.35V,   32C
|   Fast PVT is Strong Process,  1.4V,   -35C
|   Slow PVT is Weak Process,   1.35V,  110C
[Voltage Range]   1.35   1.35   1.4
|Junction Temperature
[Temperature Range]   32   110   -35
[Pullup Reference]   1.35   1.33   1.4
[Pulldown Reference]   0   0   -0
[Power Clamp Reference]   1.35   1.33   1.4
[GND Clamp Reference]   0   0   0
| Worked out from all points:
|   slope of the pulldown table from 0 to 0.203 V, typ, clamps not added: 62.5 ohm
|   slope of the pullup table from 0 to 0.203 V, typ, clamps not added: 2.24 kohm
|   falling waveform, V_fixture 0.684V, R_fixture 50Ohm: 20-80 % time 325ps typ, 386ps min, 268ps max; typ from 0.988 V to 0.381 V
|   rising waveform, V_fixture 0.684V, R_fixture 50Ohm: 20-80 % time 485ps typ, 508ps min, 421ps max; typ from 0.381 V to 0.988 V
[Pulldown]
|   Voltage   I(typ)   I(min)   I(max)
-1.35V    -746.9uA   -528.8uA   -1.016mA
-1.349V   -2.248mA   -2.023mA   -2.525mA
-1.057V   -3.627mA   -3.883mA   -4.83mA
-859.4mV  -7.115mA   -5.145mA   -12.96mA
-776.8mV  -9.097mA   -5.671mA   -12.59mA
-563.8mV  -7.395mA   -5.675mA   -11.63mA
-337.4mV  -5.586mA   -4.273mA   -7.67mA
933.5mV   14.27mA    10.65mA    19.91mA
1.688V    23.82mA    17.52mA    33.42mA
2.057V    30.58mA    21.91mA    40.36mA
2.416V    37.15mA    30.63mA    52.33mA
2.7V      42.32mA    37.5mA     54.16mA
[GND Clamp]
|   Voltage   I(typ)   I(min)   I(max)
-1.35V    -805.3mA   -939mA     -696.6mA
-1.196V   -525mA     -659.8mA   -415mA
-1.085V   -334.4mA   -467.2mA   -226.8mA
-1.008V   -212.7mA   -337mA     -115.6mA
-946.9mV  -126.2mA   -245.9mA   -55.95mA
-901.2mV  -77.35mA   -177.3mA   -36.05mA
-881.7mV  -56.78mA   -154.7mA   -31.18mA
-816.1mV  -24.58mA   -78.69mA   -22.09mA
-753.7mV  -13.1mA    -34.67mA   -16.49mA
-681.2mV  -10.83mA   -12.6mA    -11.02mA
-337mV    -75.55uA   -89.34uA   -56.62uA
2.7V      0A         0A         0A
[Pullup]
|   Voltage   I(typ)   I(min)   I(max)
-1.35V    28.42mA    22.45mA    36.78mA
-1.051V   18.41mA    14.99mA    24.68mA
-633.4mV  4.662mA    4.76mA     4.871mA
-337.4mV  -2.494mA   -700.4uA   -4.673mA
-199.3mV  -4.637mA   -2.538mA   -7.277mA
182.6mV   -6.153mA   -4.83mA    -8.24mA
1.688V    -5.96mA    -4.748mA   -8.122mA
2.025V    -7.128mA   -4.876mA   -7.964mA
2.162V    -7.598mA   -3.195mA   -10.23mA
2.298V    -4.175mA   -1.273mA   -12.48mA
2.473V    -1.672mA   -714uA     -3.803mA
2.7V      -667.3uA   -195.3uA   -1.463mA
[POWER Clamp]
|   Voltage   I(typ)   I(min)   I(max)
-1.35V    26.61mA    23.72mA    33.56mA
-1.154V   11.24mA    10.04mA    13.89mA
-1.089V   7.631mA    6.861mA    9.282mA
-1.078V   7.053mA    6.352mA    8.808mA
-1.068V   6.69mA     5.863mA    8.352mA
-997.5mV  4.156mA    3.62mA     5.426mA
-983.8mV  3.89mA     3.186mA    5.092mA
-928.3mV  2.839mA    2.21mA     3.746mA
-842.8mV  2.093mA    1.447mA    2.691mA
-528.1mV  786.7uA    566.6uA    635.4uA
-337.4mV  29.85uA    33.16uA    23.02uA
2.7V      0A         0A         0A
[Ramp]
R_load = 50
|   typ   min   max
dV/dt_r   0.364449/4.85101e-10   0.293625/5.08422e-10   0.485208/4.21703e-10
dV/dt_f   0.364418/3.24288e-10   0.293609/3.85955e-10   0.485196/2.67319e-10
[Falling Waveform]
V_fixture = 0.684V
V_fixture_min = 0.653V
V_fixture_max = 0.768V
R_fixture = 50Ohm
C_fixture = 0F
|   Time   V(typ)   V(min)   V(max)
0s        988.4mV    898.1mV    1.173V
472.6ps   988.8mV    897.8mV    1.181V
514.1ps   992.2mV    897.7mV    1.116V
598.2ps   971.7mV    898.3mV    902.1mV
707ps     813.1mV    901.7mV    672mV
819ps     653.9mV    823.7mV    530.2mV
1.03ns    485.8mV    618.1mV    421.9mV
1.36ns    409mV      467.6mV    384.2mV
2.738ns   386.5mV    414.3mV    370.1mV
20ns      381.1mV    408.7mV    364.8mV
[Rising Waveform]
V_fixture = 0.684V
V_fixture_min = 0.653V
V_fixture_max = 0.768V
R_fixture = 50Ohm
C_fixture = 0F
|   Time   V(typ)   V(min)   V(max)
0s        381.1mV    408.7mV    364.8mV
529.4ps   380.3mV    408.5mV    340.5mV
665.1ps   362.8mV    408.4mV    568.6mV
840.4ps   561.9mV    391.7mV    835.3mV
1.046ns   750.4mV    566mV      1.003V
1.203ns   838.5mV    680mV      1.065V
1.409ns   905.5mV    775.8mV    1.108V
1.936ns   965.2mV    869.8mV    1.148V
3.038ns   984.4mV    895.9mV    1.167V
20ns      988.5mV    898.1mV    1.173V
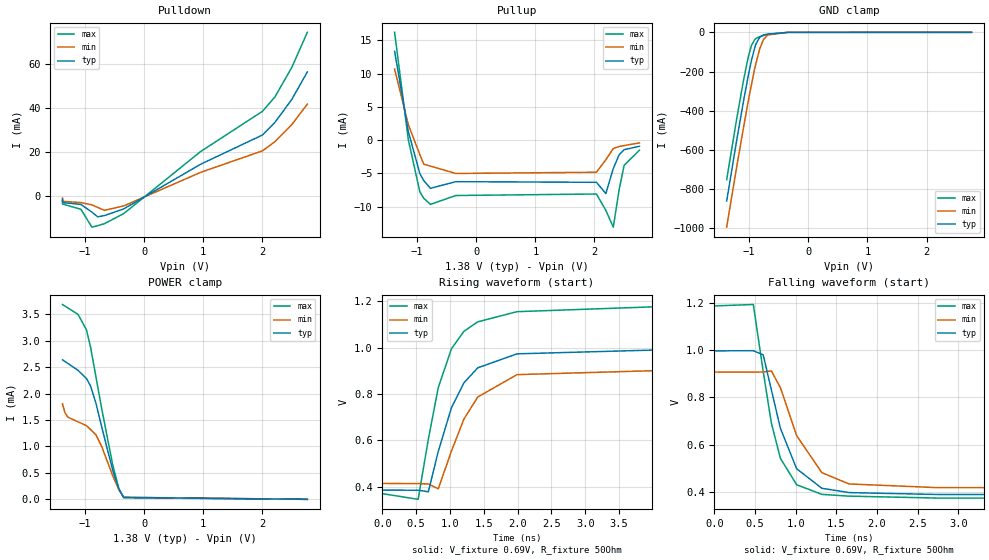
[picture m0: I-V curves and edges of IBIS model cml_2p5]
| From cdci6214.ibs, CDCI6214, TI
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|   cml_2p5 Model
[Model]   cml_2p5
Model_type   3-state
Polarity   Non-Inverting
Vmeas = 0.7
Vref = 0.69
Cref = 2pF
Rref = 50
|   typ   min   max
C_comp   7.009E-12   6.881E-12   7.139E-12
|  Where Nom  PVT is Nominal Process, 1.38V,   32C
|   Fast PVT is Strong Process,  1.42V,   -35C
|   Slow PVT is Weak Process,   1.34V,   110C
[Voltage Range]   1.38   1.34   1.42
|Junction Temperature
[Temperature Range]   32   110   -35
[Pullup Reference]   1.38   1.34   1.42
[Pulldown Reference]   0   -0   0
[Power Clamp Reference]   1.38   1.34   1.42
[GND Clamp Reference]   0   0   0
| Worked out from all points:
|   slope of the pulldown table from 0 to 0.207 V, typ, clamps not added: 62.5 ohm
|   POWER clamp passes 1 mA (typ) near -0.64 V on its own axis
|   falling waveform, V_fixture 0.69V, R_fixture 50Ohm: 20-80 % time 323ps typ, 384ps min, 266ps max; typ from 0.997 V to 0.384 V
|   rising waveform, V_fixture 0.69V, R_fixture 50Ohm: 20-80 % time 483ps typ, 501ps min, 433ps max; typ from 0.384 V to 0.997 V
[Pulldown]
|   Voltage   I(typ)   I(min)   I(max)
-1.38V    -1.296mA   -762.1uA   -1.952mA
-1.379V   -2.838mA   -2.296mA   -3.503mA
-1.069V   -3.676mA   -2.835mA   -5.899mA
-883.1mV  -7.185mA   -3.884mA   -14.02mA
-786.2mV  -9.302mA   -5.023mA   -13.36mA
-672.4mV  -8.785mA   -6.363mA   -12.45mA
-344.9mV  -5.715mA   -4.37mA    -7.849mA
953mV     14.54mA    10.86mA    20.3mA
2.002V    27.89mA    20.68mA    38.65mA
2.212V    33.58mA    24.83mA    45.17mA
2.499V    44.13mA    32.65mA    58.7mA
2.76V     56.55mA    41.91mA    74.54mA
[GND Clamp]
|   Voltage   I(typ)   I(min)   I(max)
-1.38V    -861mA     -994.4mA   -752.6mA
-1.214V   -556.7mA   -692.4mA   -447.5mA
-1.095V   -350.3mA   -485.8mA   -244.2mA
-1.013V   -218.3mA   -347.1mA   -123mA
-960.9mV  -142.9mA   -267mA     -66.49mA
-909.2mV  -82.98mA   -188.2mA   -38.9mA
-886.8mV  -60.9mA    -161.5mA   -31.22mA
-821.4mV  -24.79mA   -83.65mA   -22.01mA
-757.6mV  -13.4mA    -36.64mA   -16.21mA
-685.2mV  -9mA       -13.27mA   -10.92mA
-344.5mV  -93.17uA   -106.8uA   -73.37uA
2.76V     0A         0A         0A
[Pullup]
|   Voltage   I(typ)   I(min)   I(max)
-1.38V    13.38mA    10.71mA    16.22mA
-1.148V   1.297mA    2.339mA    81.32uA
-953mV    -5.013mA   -2.167mA   -7.76mA
-886.8mV  -6.069mA   -3.602mA   -8.735mA
-774.2mV  -7.229mA   -3.892mA   -9.648mA
-344.9mV  -6.232mA   -5mA       -8.314mA
2.033V    -6.328mA   -4.814mA   -8.084mA
2.192V    -8.023mA   -2.932mA   -10.54mA
2.318V    -4.247mA   -1.246mA   -13.07mA
2.418V    -2.169mA   -933.5uA   -7.383mA
2.501V    -1.424mA   -806.2uA   -3.785mA
2.76V     -905.9uA   -406.5uA   -1.494mA
[POWER Clamp]
|   Voltage   I(typ)   I(min)   I(max)
-1.38V    2.636mA    1.805mA    3.682mA
-1.341V   2.606mA    1.643mA    3.653mA
-1.289V   2.568mA    1.552mA    3.617mA
-1.117V   2.437mA    1.464mA    3.494mA
-975.8mV  2.284mA    1.393mA    3.206mA
-905.8mV  2.142mA    1.319mA    2.876mA
-814.4mV  1.814mA    1.218mA    2.311mA
-715.4mV  1.359mA    993uA      1.702mA
-530.7mV  547.5uA    445.3uA    648.6uA
-428.5mV  194.3uA    183uA      209.3uA
-344.9mV  36.49uA    38.56uA    29.5uA
2.76V     0A         0A         0A
[Ramp]
R_load = 50
|   typ   min   max
dV/dt_r   0.367476/4.82815e-10   0.296611/5.0133e-10   0.49087/4.33908e-10
dV/dt_f   0.367468/3.22344e-10   0.296599/3.83213e-10   0.490868/2.65582e-10
[Falling Waveform]
V_fixture = 0.69V
V_fixture_min = 0.66V
V_fixture_max = 0.777V
R_fixture = 50Ohm
C_fixture = 0F
|   Time   V(typ)   V(min)   V(max)
0s        996.9mV    907.5mV    1.187V
478.5ps   997.7mV    907.1mV    1.193V
600.3ps   979.9mV    907.7mV    909.1mV
701.1ps   831.3mV    912.1mV    690.3mV
812.3ps   668.5mV    840.6mV    542.1mV
1.012ns   498.3mV    638.3mV    430.8mV
1.322ns   415.9mV    481.8mV    390.1mV
1.657ns   397.7mV    434.2mV    382.7mV
2.74ns    389.7mV    418.7mV    374.6mV
20ns      384.5mV    413.1mV    369.2mV
[Rising Waveform]
V_fixture = 0.69V
V_fixture_min = 0.66V
V_fixture_max = 0.777V
R_fixture = 50Ohm
C_fixture = 0F
|   Time   V(typ)   V(min)   V(max)
0s        384.5mV    413.1mV    369.2mV
529.3ps   383.9mV    412.9mV    344.6mV
679.9ps   377.4mV    411.1mV    604.4mV
826.7ps   551.7mV    390.1mV    827.9mV
1.022ns   741.2mV    553.8mV    995.7mV
1.206ns   848.4mV    691.7mV    1.071V
1.41ns    913.1mV    786.9mV    1.112V
1.991ns   973.7mV    883.8mV    1.156V
4.791ns   996.3mV    907.4mV    1.185V
20ns      996.9mV    907.5mV    1.187V
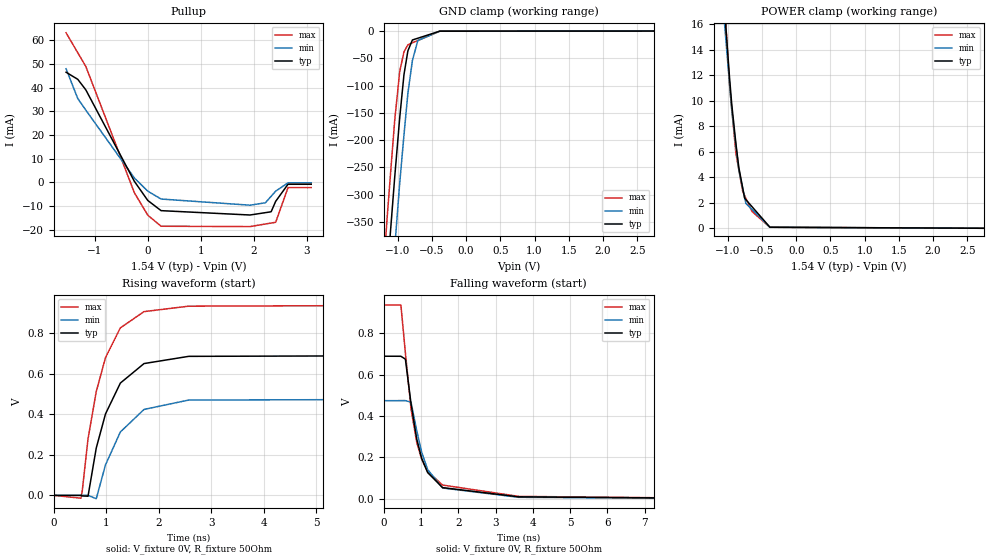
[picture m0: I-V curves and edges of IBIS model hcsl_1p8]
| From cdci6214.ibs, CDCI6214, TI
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|   hcsl_1p8 Model
[Model]   hcsl_1p8
Model_type   Open_source
Polarity   Non-Inverting
Vmeas = 0.3
Vref = 0
Cref = 2pF
Rref = 50
|   typ   min   max
C_comp   7.009E-12   6.881E-12   7.172E-12
|  Where Nom  PVT is Nominal Process, 1.54V,  32C
|   Fast PVT is Strong Process,  1.55V, -35C
|   Slow PVT is Weak Process,   1.53V, 110C
[Voltage Range]   1.54   1.53   1.55
|Junction Temperature
[Temperature Range]   32   110   -35
[Pullup Reference]   1.54   1.53   1.55
[Pulldown Reference]   0   0   0
[Power Clamp Reference]   1.54   1.53   1.55
[GND Clamp Reference]   0   0   0
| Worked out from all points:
|   slope of the pullup table from 0 to 0.231 V, typ, clamps not added: 56.8 ohm
|   GND clamp passes 1 mA (typ) near -0.40 V on its own axis
|   falling waveform, V_fixture 0V, R_fixture 50Ohm: 20-80 % time 474ps typ, 489ps min, 465ps max; typ from 0.69 V to 0 V
|   rising waveform, V_fixture 0V, R_fixture 50Ohm: 20-80 % time 524ps typ, 563ps min, 485ps max; typ from 0 V to 0.69 V
[GND Clamp]
|   Voltage   I(typ)   I(min)   I(max)
-1.54V    -1.162A    -1.294A    -1.055A
-1.283V   -682.4mA   -815.9mA   -573.9mA
-1.151V   -447.9mA   -582.5mA   -337.8mA
-1.119V   -390.7mA   -525.5mA   -286mA
-1.044V   -269.7mA   -399.5mA   -165.2mA
-969.3mV  -158.3mA   -278.2mA   -73.82mA
-907.2mV  -79.57mA   -190.1mA   -38.17mA
-850.3mV  -36.36mA   -114.1mA   -25.32mA
-784.3mV  -16.41mA   -54.09mA   -21.59mA
-705.4mV  -13.23mA   -17.46mA   -17.38mA
-384.3mV  -261.4uA   -258.6uA   -244.1uA
3.08V     0A         0A         0A
[Pullup]
|   Voltage   I(typ)   I(min)   I(max)
-1.54V    46.54mA    48.01mA    63.19mA
-1.32V    43.56mA    35.45mA    54.79mA
-1.168V   39.11mA    30.56mA    48.98mA
-252.8mV  472uA      1.893mA    -4.324mA
-38.19uV  -7.598mA   -3.681mA   -13.82mA
250.4mV   -11.89mA   -6.988mA   -18.47mA
1.926V    -13.73mA   -9.587mA   -18.62mA
2.215V    -12.74mA   -8.571mA   -17.53mA
2.324V    -12.36mA   -5.83mA    -17.13mA
2.41V     -7.95mA    -3.648mA   -16.8mA
2.642V    -747.5uA   -171.5uA   -2.161mA
3.08V     -747.5uA   -171.5uA   -2.161mA
[POWER Clamp]
|   Voltage   I(typ)   I(min)   I(max)
-1.54V    71.06mA    62.69mA    83.36mA
-1.075V   19.21mA    17.86mA    20.1mA
-975.3mV  11.9mA     11.4mA     11.33mA
-941.5mV  9.704mA    9.226mA    9.364mA
-880.6mV  6.626mA    6.485mA    5.855mA
-838.4mV  4.77mA     4.586mA    4.598mA
-781.3mV  3.154mA    3.126mA    2.892mA
-753.3mV  2.363mA    2.411mA    2.567mA
-735.9mV  2.256mA    1.966mA    2.364mA
-647.8mV  1.713mA    1.494mA    1.338mA
-384.3mV  91.96uA    83.98uA    88.65uA
3.08V     0A         0A         0A
[Ramp]
R_load = 50
|   typ   min   max
dV/dt_r   0.413785/5.22858e-10   0.284564/5.58493e-10   0.562613/4.85057e-10
dV/dt_f   0.413719/4.74251e-10   0.284558/4.89098e-10   0.562561/4.65081e-10
[Falling Waveform]
V_fixture = 0V
V_fixture_min = 0V
V_fixture_max = 0V
R_fixture = 50Ohm
C_fixture = 0F
|   Time   V(typ)   V(min)   V(max)
0s        689.9mV    474.7mV    937.8mV
455.1ps   689.6mV    475mV      938.2mV
575.8ps   675.8mV    475.1mV    706mV
727.2ps   460.7mV    467.3mV    434.7mV
880.8ps   288.8mV    329.4mV    272.9mV
1.013ns   195.5mV    225.7mV    191.2mV
1.173ns   126.9mV    141.2mV    131.7mV
1.575ns   53.77mV    51.93mV    66.21mV
3.622ns   9.114mV    6.804mV    11.39mV
10ns      321.5uV    401.1uV    205.9uV
[Rising Waveform]
V_fixture = 0V
V_fixture_min = 0V
V_fixture_max = 0V
R_fixture = 50Ohm
C_fixture = 0F
|   Time   V(typ)   V(min)   V(max)
0s        331.7uV    416.6uV    213.4uV
516.7ps   223.7uV    294.2uV    -13.72mV
543.1ps   -2.382mV   288uV      25.04mV
651.4ps   -3.867mV   262.3uV    278.4mV
807.9ps   233.3mV    -16.08mV   511mV
984ps     401.1mV    150.5mV    678.5mV
1.267ns   553.1mV    312.4mV    824.9mV
1.718ns   649.2mV    423.4mV    904.9mV
2.568ns   684.7mV    469.5mV    931.8mV
10ns      690mV      474.7mV    937.9mV
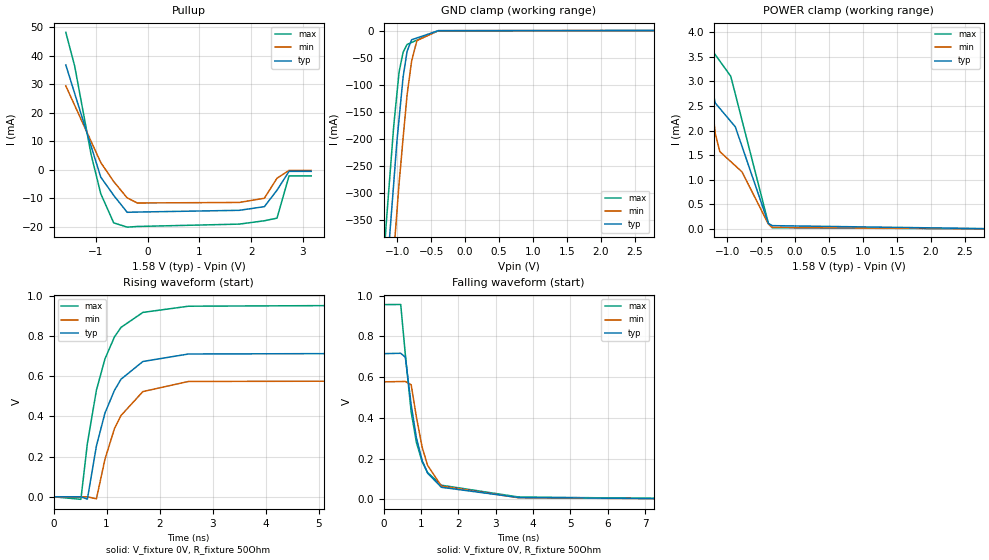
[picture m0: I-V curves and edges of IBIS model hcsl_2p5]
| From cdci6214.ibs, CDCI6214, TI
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|   hcsl_2p5 Model
[Model]   hcsl_2p5
Model_type   Open_source
Polarity   Non-Inverting
Vmeas = 0.3
Vref = 0
Cref = 2pF
Rref = 50
|   typ   min   max
C_comp   7.009E-12   6.874E-12   7.139E-12
|  Where Nom  PVT is Nominal Process, 1.58V,   32C
|   Fast PVT is Strong Process,  1.64V,  -35C
|   Slow PVT is Weak Process,   1.57V,  110C
[Voltage Range]   1.58   1.57   1.64
|Junction Temperature
[Temperature Range]   32   110   -35
[Pullup Reference]   1.58   1.57   1.64
[Pulldown Reference]   0   0   0
[Power Clamp Reference]   1.58   1.57   1.64
[GND Clamp Reference]   0   0   0
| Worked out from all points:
|   GND clamp passes 1 mA (typ) near -0.41 V on its own axis
|   falling waveform, V_fixture 0V, R_fixture 50Ohm: 20-80 % time 469ps typ, 483ps min, 460ps max; typ from 0.715 V to 0 V
|   rising waveform, V_fixture 0V, R_fixture 50Ohm: 20-80 % time 506ps typ, 511ps min, 483ps max; typ from 0 V to 0.716 V
[GND Clamp]
|   Voltage   I(typ)   I(min)   I(max)
-1.58V    -1.238A    -1.369A    -1.132A
-1.165V   -471.8mA   -606.7mA   -361.6mA
-1.108V   -373.6mA   -504.6mA   -268.2mA
-1.051V   -281.2mA   -411.7mA   -175.7mA
-1.005V   -205.5mA   -335.6mA   -117.4mA
-972.2mV  -162.7mA   -281.9mA   -76.47mA
-913mV    -85.55mA   -198.3mA   -40mA
-854.2mV  -38.44mA   -118.4mA   -25.71mA
-788.3mV  -17.06mA   -56.84mA   -22.07mA
-709.9mV  -13.72mA   -18.59mA   -17.74mA
-394.7mV  -329.2uA   -318.6uA   -327.2uA
3.16V     0A         0A         0A
[Pullup]
|   Voltage   I(typ)   I(min)   I(max)
-1.58V    36.83mA    29.47mA    48.3mA
-1.409V   26.83mA    22.64mA    36.46mA
-1.093V   8.351mA    10.01mA    5.469mA
-904.9mV  -2.617mA   2.519mA    -8.453mA
-655.2mV  -9.042mA   -4.174mA   -18.69mA
-394.9mV  -15mA      -9.92mA    -20.22mA
-198.9mV  -14.91mA   -11.72mA   -19.98mA
1.77V     -14.3mA    -11.53mA   -19.15mA
2.255V    -13.01mA   -10.05mA   -17.97mA
2.499V    -7.22mA    -3.01mA    -17.05mA
2.732V    -583.6uA   -262uA     -2.181mA
3.16V     -583.6uA   -262uA     -2.181mA
[POWER Clamp]
|   Voltage   I(typ)   I(min)   I(max)
-1.58V    17.59mA    19.03mA    18.24mA
-1.311V   4.083mA    4.344mA    4.199mA
-1.273V   3.241mA    3.483mA    3.897mA
-1.236V   2.936mA    2.655mA    3.652mA
-1.178V   2.558mA    1.938mA    3.539mA
-1.111V   2.449mA    1.572mA    3.412mA
-949.4mV  2.184mA    1.368mA    3.101mA
-882.2mV  2.074mA    1.284mA    2.739mA
-784.3mV  1.68mA     1.16mA     2.211mA
-394.5mV  112uA      98.83uA    111.5uA
-339.5mV  67.47uA    34.25uA    24.71uA
3.16V     0A         0A         0A
[Ramp]
R_load = 50
|   typ   min   max
dV/dt_r   0.429148/5.04853e-10   0.346032/5.08238e-10   0.573793/4.8258e-10
dV/dt_f   0.429086/4.6898e-10   0.345945/4.80774e-10   0.57375/4.60777e-10
[Falling Waveform]
V_fixture = 0V
V_fixture_min = 0V
V_fixture_max = 0V
R_fixture = 50Ohm
C_fixture = 0F
|   Time   V(typ)   V(min)   V(max)
0s        715.5mV    577mV      956.4mV
457.1ps   717.4mV    578.6mV    956.9mV
580.2ps   698.4mV    579mV      711.7mV
736.7ps   464.8mV    562.6mV    429.7mV
875.9ps   302.7mV    405.6mV    280.5mV
1.031ns   191mV      255.8mV    184.4mV
1.176ns   129mV      167.3mV    132.1mV
1.545ns   59.41mV    65.28mV    69.6mV
3.614ns   9.116mV    7.8mV      11.58mV
10ns      326.7uV    459.2uV    197.1uV
[Rising Waveform]
V_fixture = 0V
V_fixture_min = 0V
V_fixture_max = 0V
R_fixture = 50Ohm
C_fixture = 0F
|   Time   V(typ)   V(min)   V(max)
0s        335.9uV    471.8uV    203.6uV
515.5ps   231.9uV    360.7uV    -12.35mV
637.9ps   -11.49mV   334.4uV    265.8mV
807.9ps   253mV      -9.845mV   530.4mV
968.7ps   416.5mV    186.9mV    685.9mV
1.148ns   529.8mV    339.6mV    795.4mV
1.272ns   585.1mV    404.8mV    842.8mV
1.684ns   673.2mV    523.6mV    917.2mV
2.543ns   710.4mV    573.8mV    948mV
10ns      715.6mV    577.2mV    956.5mV
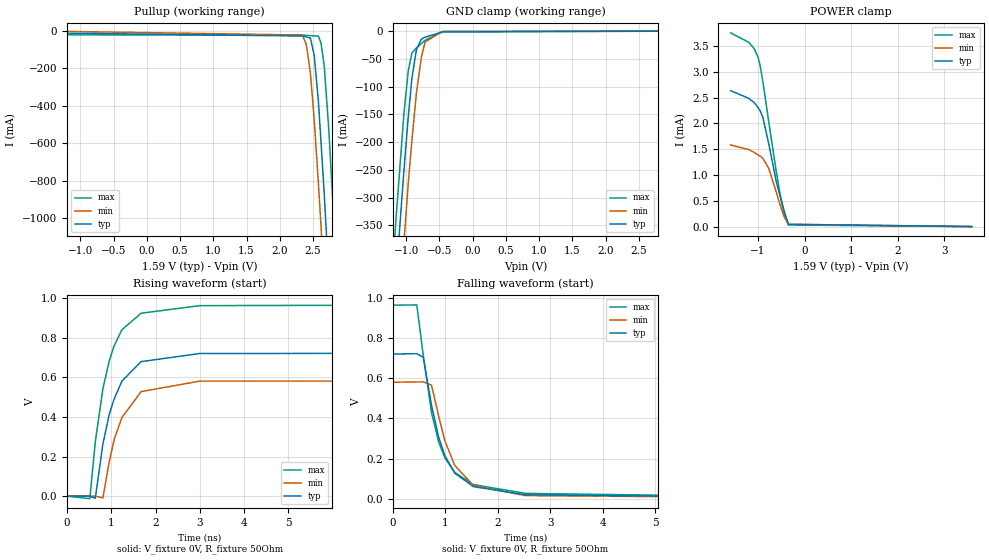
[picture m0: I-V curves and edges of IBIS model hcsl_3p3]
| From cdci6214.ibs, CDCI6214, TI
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|   hcsl_2p5 Model
[Model]   hcsl_3p3
Model_type   Open_source
Polarity   Non-Inverting
Vmeas = 0.3
Vref = 0
Cref = 2pF
Rref = 50
|   typ   min   max
C_comp   6.977E-12   6.849E-12   7.106E-12
|  Where Nom  PVT is Nominal Process, 1.59V,   32C
|   Fast PVT is Strong Process,  1.66V,  -35C
|   Slow PVT is Weak Process,   1.58V,  110C
[Voltage Range]   1.59   1.58   1.66
|Junction Temperature
[Temperature Range]   32   110   -35
[Pullup Reference]   1.59   1.58   1.66
[Pulldown Reference]   0   0   0
[Power Clamp Reference]   1.59   1.58   1.66
[GND Clamp Reference]   0   0   0
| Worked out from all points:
|   GND clamp passes 1 mA (typ) near -0.41 V on its own axis
|   POWER clamp passes 1 mA (typ) near -0.64 V on its own axis
|   falling waveform, V_fixture 0V, R_fixture 50Ohm: 20-80 % time 466ps typ, 479ps min, 458ps max; typ from 0.721 V to 0 V
|   rising waveform, V_fixture 0V, R_fixture 50Ohm: 20-80 % time 499ps typ, 499ps min, 482ps max; typ from 0 V to 0.721 V
[GND Clamp]
|   Voltage   I(typ)   I(min)   I(max)
-2V       -2.046A    -2.173A    -1.945A
-1.329V   -766.8mA   -901.2mA   -658.2mA
-1.15V    -445.2mA   -579mA     -335.6mA
-1.13V    -409.6mA   -543.3mA   -304.1mA
-1.031V   -249.1mA   -378.3mA   -146.5mA
-966.7mV  -154.2mA   -273.3mA   -71.47mA
-912.8mV  -85.3mA    -197.1mA   -39.7mA
-845.1mV  -33.79mA   -112.4mA   -30.36mA
-770.2mV  -14.49mA   -47.33mA   -22.58mA
-714.5mV  -11.07mA   -19.83mA   -16.79mA
-453.5mV  -1.68mA    -863uA     -1.022mA
3.59V     0A         0A         0A
[Pullup]
|   Voltage   I(typ)   I(min)   I(max)
-1.59V    -9.946mA   75.29uA    -20.27mA
2.339V    -26.68mA   -21.34mA   -21.96mA
2.399V    -31.89mA   -72.42mA   -23.28mA
2.46V     -37.19mA   -224.4mA   -24.62mA
2.517V    -129mA     -471.6mA   -25.88mA
2.58V     -374.2mA   -811.5mA   -27.25mA
2.621V    -601.4mA   -1.049A    -65.88mA
2.668V    -868.7mA   -1.354A    -186.1mA
2.736V    -1.316A    -1.802A    -522.2mA
2.772V    -1.548A    -2.052A    -749.2mA
2.834V    -1.999A    -2.496A    -1.145A
3.18V     -4.523A    -4.982A    -3.684A
[POWER Clamp]
|   Voltage   I(typ)   I(min)   I(max)
-1.59V    2.635mA    1.583mA    3.755mA
-1.198V   2.485mA    1.491mA    3.571mA
-1.083V   2.403mA    1.438mA    3.449mA
-1.001V   2.31mA     1.392mA    3.285mA
-956.1mV  2.249mA    1.366mA    3.13mA
-894.9mV  2.111mA    1.321mA    2.805mA
-768.8mV  1.601mA    1.127mA    2.025mA
-602mV    845uA      650uA      1.03mA
-522.3mV  583uA      410.9uA    606.4uA
-436.2mV  299.8uA    184.8uA    235.7uA
-346.8mV  44.85uA    43.55uA    31.34uA
3.59V     0A         0A         0A
[Ramp]
R_load = 50
|   typ   min   max
dV/dt_r   0.432515/4.98189e-10   0.348265/4.98019e-10   0.578872/4.81645e-10
dV/dt_f   0.432456/4.65505e-10   0.348183/4.76953e-10   0.578836/4.5751e-10
[Falling Waveform]
V_fixture = 0V
V_fixture_min = 0V
V_fixture_max = 0V
R_fixture = 50Ohm
C_fixture = 0F
|   Time   V(typ)   V(min)   V(max)
0s        721.1mV    580.8mV    964.9mV
457.5ps   723mV      582.3mV    966.1mV
580.5ps   705.1mV    582.7mV    716.3mV
738.7ps   466.1mV    566.1mV    429mV
874.7ps   305.9mV    411.4mV    282.5mV
991.7ps   215.2mV    290.1mV    205mV
1.181ns   127.6mV    165.8mV    131.4mV
1.537ns   60.21mV    66.17mV    70.5mV
2.528ns   19.82mV    15.6mV     26.63mV
10ns      323.7uV    458.8uV    187.2uV
[Rising Waveform]
V_fixture = 0V
V_fixture_min = 0V
V_fixture_max = 0V
R_fixture = 50Ohm
C_fixture = 0F
|   Time   V(typ)   V(min)   V(max)
0s        331.6uV    469.1uV    192.8uV
513.6ps   252.5uV    350.4uV    -12.63mV
637.9ps   -10.85mV   321.7uV    273.3mV
809.3ps   262.7mV    -8.599mV   541.4mV
953.5ps   413mV      174.2mV    682.7mV
1.062ns   489.3mV    284.5mV    757.7mV
1.239ns   580.4mV    396.8mV    839.7mV
1.674ns   678.9mV    527.7mV    923.1mV
2.998ns   719.8mV    580.5mV    961.4mV
10ns      721.2mV    580.9mV    965mV
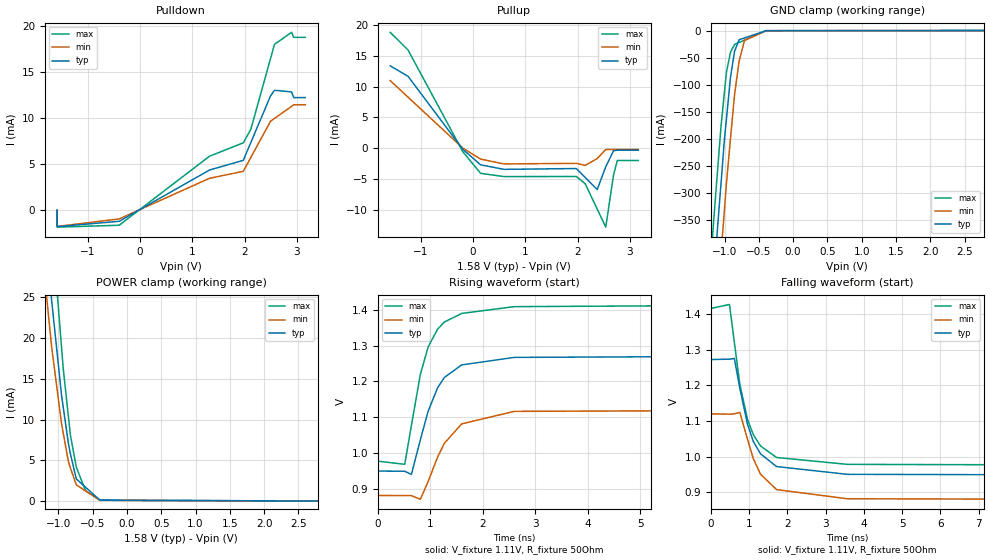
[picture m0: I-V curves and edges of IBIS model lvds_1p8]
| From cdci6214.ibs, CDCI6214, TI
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|   lvds_1p8 Model
[Model]   lvds_1p8
Model_type   3-state
Polarity   Non-Inverting
Vmeas = 1.11
Vref = 1.11
Cref = 2pF
Rref = 50
|   typ   min   max
C_comp   7.009E-12   6.881E-12   7.039E-12
|  Where Nom  PVT is Nominal Process, 1.58V,  32C
|   Fast PVT is Strong Process,  1.66V, -35C
|   Slow PVT is Weak Process,   1.52V, 110C
[Voltage Range]   1.58   1.52   1.66
|Junction Temperature
[Temperature Range]   32   110   -35
[Pullup Reference]   1.58   1.52   1.66
[Pulldown Reference]   0   0   -0
[Power Clamp Reference]   1.58   1.52   1.66
[GND Clamp Reference]   0   0   0
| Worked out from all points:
|   slope of the pulldown table from 0 to 0.237 V, typ, clamps not added: 287 ohm
|   slope of the pullup table from 0 to 0.237 V, typ, clamps not added: 203 ohm
|   GND clamp passes 1 mA (typ) near -0.41 V on its own axis
|   POWER clamp passes 1 mA (typ) near -0.51 V on its own axis
|   falling waveform, V_fixture 1.11V, R_fixture 50Ohm: 20-80 % time 523ps typ, 557ps min, 494ps max; typ from 1.27 V to 0.949 V
|   rising waveform, V_fixture 1.11V, R_fixture 50Ohm: 20-80 % time 481ps typ, 532ps min, 429ps max; typ from 0.949 V to 1.27 V
[Pulldown]
|   Voltage   I(typ)   I(min)   I(max)
-1.58V    -61.1uA    -46.93uA   -102.6uA
-1.58V    -1.865mA   -1.091mA   -958uA
-1.579V   -1.864mA   -1.839mA   -1.918mA
-394.9mV  -1.28mA    -1.019mA   -1.71mA
1.331V    4.314mA    3.412mA    5.823mA
1.976V    5.365mA    4.168mA    7.278mA
2.121V    7.329mA    5.693mA    8.768mA
2.497V    12.4mA     9.633mA    16.48mA
2.572V    13.01mA    9.937mA    18.02mA
2.899V    12.83mA    11.26mA    19.33mA
2.94V     12.21mA    11.43mA    18.78mA
3.16V     12.21mA    11.43mA    18.78mA
[GND Clamp]
|   Voltage   I(typ)   I(min)   I(max)
-1.58V    -1.238A    -1.369A    -1.132A
-1.165V   -472mA     -606.8mA   -361.7mA
-1.108V   -372.9mA   -503.9mA   -267.5mA
-1.051V   -281.2mA   -411.8mA   -175.8mA
-1.005V   -205.5mA   -335.8mA   -117.5mA
-972.2mV  -162.8mA   -282mA     -76.56mA
-913.1mV  -85.61mA   -198.4mA   -40.05mA
-854.3mV  -38.47mA   -118.4mA   -25.74mA
-788.4mV  -17.07mA   -56.9mA    -22.08mA
-709.8mV  -13.73mA   -18.57mA   -17.74mA
-394.8mV  -328.7uA   -319uA     -318uA
3.16V     0A         0A         0A
[Pullup]
|   Voltage   I(typ)   I(min)   I(max)
-1.58V    13.38mA    10.99mA    18.83mA
-1.24V    11.68mA    8.294mA    15.96mA
-192.2mV  -186uA     15.01uA    -578.2uA
146.8mV   -2.7mA     -1.775mA   -4.084mA
593.9mV   -3.438mA   -2.557mA   -4.612mA
1.976V    -3.306mA   -2.463mA   -4.601mA
2.144V    -4.745mA   -2.799mA   -5.758mA
2.375V    -6.723mA   -1.681mA   -9.895mA
2.538V    -3.016mA   -217.1uA   -12.83mA
2.686V    -425.4uA   -208.6uA   -4.394mA
2.759V    -320.5uA   -208.6uA   -2.004mA
3.16V     -320.5uA   -208.6uA   -2.004mA
[POWER Clamp]
|   Voltage   I(typ)   I(min)   I(max)
-1.58V    82.27mA    66.27mA    109.8mA
-1.232V   38.06mA    30.01mA    52.41mA
-1.1V     24.62mA    18.94mA    34.8mA
-1.079V   22.94mA    17.54mA    32.02mA
-954.3mV  12.9mA     9.431mA    18.72mA
-932mV    11.58mA    8.396mA    16.35mA
-854.9mV  7.051mA    4.831mA    10.34mA
-826.3mV  5.79mA     4.077mA    8.104mA
-739.6mV  2.717mA    1.994mA    4.152mA
-604.4mV  1.696mA    1.251mA    1.271mA
-394.8mV  112.7uA    100.2uA    112.6uA
3.16V     0A         0A         0A
[Ramp]
R_load = 50
|   typ   min   max
dV/dt_r   0.193988/4.77301e-10   0.14331/5.27231e-10   0.26281/4.27865e-10
dV/dt_f   0.193965/5.2288e-10   0.143306/5.54526e-10   0.262774/4.93693e-10
[Falling Waveform]
V_fixture = 1.11V
V_fixture_min = 1V
V_fixture_max = 1.196V
R_fixture = 50Ohm
C_fixture = 0F
|   Time   V(typ)   V(min)   V(max)
0s        1.272V     1.12V      1.415V
487.4ps   1.273V     1.119V     1.426V
613.6ps   1.275V     1.12V      1.32V
756.8ps   1.192V     1.124V     1.203V
957.1ps   1.091V     1.049V     1.105V
1.108ns   1.043V     995mV      1.062V
1.298ns   1.008V     951mV      1.03V
1.717ns   972.4mV    908mV      997.8mV
3.566ns   950.7mV    882.3mV    978.6mV
10ns      949mV      880.7mV    976.7mV
[Rising Waveform]
V_fixture = 1.11V
V_fixture_min = 1V
V_fixture_max = 1.196V
R_fixture = 50Ohm
C_fixture = 0F
|   Time   V(typ)   V(min)   V(max)
0s        949mV      880.7mV    976.7mV
512.7ps   948.5mV    880.4mV    967.8mV
638.7ps   939.5mV    880.3mV    1.076V
809.3ps   1.036V     869.9mV    1.219V
957.1ps   1.116V     919.3mV    1.296V
1.138ns   1.182V     988mV      1.346V
1.268ns   1.211V     1.027V     1.366V
1.597ns   1.246V     1.081V     1.39V
2.598ns   1.267V     1.116V     1.409V
10ns      1.272V     1.12V      1.415V
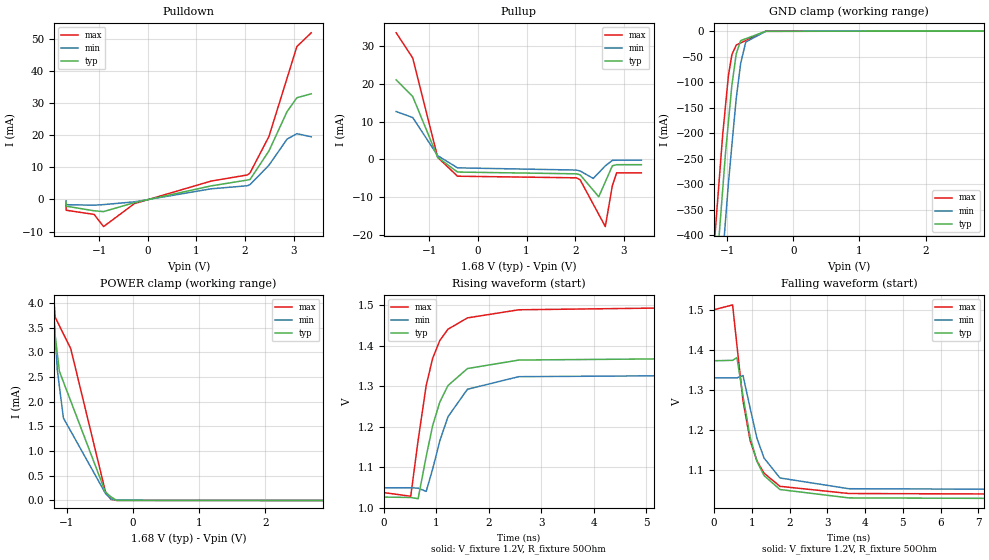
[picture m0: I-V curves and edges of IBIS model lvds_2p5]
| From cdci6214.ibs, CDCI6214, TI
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|   lvds_2p5 Model
[Model]   lvds_2p5
Model_type   3-state
Polarity   Non-Inverting
Vmeas = 1.2
Vref = 1.2
Cref = 2pF
Rref = 50
|   typ   min   max
C_comp   7.009E-12   6.881E-12   7.139E-12
|  Where Nom  PVT is Nominal Process, 1.68V,   32C
|   Fast PVT is Strong Process,  1.73V,  -35C
|   Slow PVT is Weak Process,   1.66V,  110C
[Voltage Range]   1.68   1.66   1.73
|Junction Temperature
[Temperature Range]   32   110   -35
[Pullup Reference]   1.68   1.66   1.73
[Pulldown Reference]   0   0   -0
[Power Clamp Reference]   1.68   1.66   1.73
[GND Clamp Reference]   0   0   0
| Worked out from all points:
|   slope of the pulldown table from 0 to 0.252 V, typ, clamps not added: 293 ohm
|   GND clamp passes 1 mA (typ) near -0.43 V on its own axis
|   falling waveform, V_fixture 1.2V, R_fixture 50Ohm: 20-80 % time 516ps typ, 544ps min, 488ps max; typ from 1.37 V to 1.03 V
|   rising waveform, V_fixture 1.2V, R_fixture 50Ohm: 20-80 % time 468ps typ, 493ps min, 430ps max; typ from 1.03 V to 1.37 V
[Pulldown]
|   Voltage   I(typ)   I(min)   I(max)
-1.68V    -858.6uA   -426.3uA   -1.423mA
-1.679V   -2.095mA   -1.635mA   -3.367mA
-1.104V   -3.538mA   -1.797mA   -4.662mA
-909.8mV  -3.791mA   -1.611mA   -8.458mA
-275.7mV  -1mA       -751.4uA   -1.298mA
1.305V    4.225mA    3.311mA    5.726mA
2.047V    6.037mA    4.261mA    7.621mA
2.101V    6.196mA    4.605mA    8.242mA
2.49V     15.08mA    10.64mA    19.6mA
2.863V    27.35mA    18.78mA    37.75mA
3.065V    31.67mA    20.48mA    47.62mA
3.36V     32.9mA     19.5mA     51.89mA
[GND Clamp]
|   Voltage   I(typ)   I(min)   I(max)
-1.68V    -1.429A    -1.559A    -1.324A
-1.2V     -533.4mA   -668.4mA   -423mA
-1.152V   -448.6mA   -581mA     -341.8mA
-1.07V    -311.4mA   -443.4mA   -204mA
-1.027V   -239.3mA   -371.2mA   -146.4mA
-982.3mV  -177.5mA   -297.6mA   -86.57mA
-930.4mV  -105.9mA   -223.2mA   -46.18mA
-863.8mV  -44.08mA   -131mA     -27.26mA
-797.8mV  -18.75mA   -63.47mA   -23.29mA
-720.4mV  -15.03mA   -21.55mA   -18.64mA
-419.5mV  -539.4uA   -503.6uA   -556.8uA
3.36V     0A         0A         0A
[Pullup]
|   Voltage   I(typ)   I(min)   I(max)
-1.68V    21.05mA    12.66mA    33.49mA
-1.341V   16.65mA    11.09mA    26.84mA
-826.6mV  537.7uA    986.3uA    528uA
-419.4mV  -3.344mA   -2.231mA   -4.443mA
2.026V    -3.812mA   -2.817mA   -4.869mA
2.101V    -4.064mA   -3.057mA   -5.402mA
2.371V    -8.159mA   -5.031mA   -11.84mA
2.484V    -9.882mA   -3.513mA   -14.54mA
2.619V    -5.927mA   -1.698mA   -17.77mA
2.764V    -1.681mA   -253uA     -6.914mA
2.851V    -1.397mA   -208.2uA   -3.547mA
3.36V     -1.397mA   -208.2uA   -3.547mA
[POWER Clamp]
|   Voltage   I(typ)   I(min)   I(max)
-1.68V    38.36mA    37.63mA    41.81mA
-1.233V   4.52mA     4.582mA    4.722mA
-1.187V   3.414mA    3.528mA    3.854mA
-1.179V   3.325mA    3.348mA    3.711mA
-1.148V   2.982mA    2.656mA    3.629mA
-1.116V   2.619mA    2.314mA    3.541mA
-1.055V   2.403mA    1.67mA     3.375mA
-944mV    2.014mA    1.405mA    3.076mA
-419.4mV  170.4uA    144.2uA    180uA
-337.7mV  76.17uA    32.69uA    23.27uA
-250.9mV  1.93uA     5.113uA    1.159uA
3.36V     0A         0A         0A
[Ramp]
R_load = 50
|   typ   min   max
dV/dt_r   0.207981/4.65329e-10   0.168063/4.91265e-10   0.278114/4.29467e-10
dV/dt_f   0.207911/5.16051e-10   0.167994/5.452e-10   0.27806/4.87759e-10
[Falling Waveform]
V_fixture = 1.2V
V_fixture_min = 1.19V
V_fixture_max = 1.27V
R_fixture = 50Ohm
C_fixture = 0F
|   Time   V(typ)   V(min)   V(max)
0s        1.373V     1.33V      1.501V
490.5ps   1.374V     1.33V      1.513V
606ps     1.381V     1.33V      1.411V
766.5ps   1.284V     1.336V     1.272V
955.5ps   1.181V     1.254V     1.173V
1.134ns   1.121V     1.179V     1.122V
1.323ns   1.085V     1.129V     1.091V
1.745ns   1.05V      1.079V     1.058V
3.571ns   1.029V     1.052V     1.04V
10ns      1.027V     1.05V      1.038V
[Rising Waveform]
V_fixture = 1.2V
V_fixture_min = 1.19V
V_fixture_max = 1.27V
R_fixture = 50Ohm
C_fixture = 0F
|   Time   V(typ)   V(min)   V(max)
0s        1.027V     1.05V      1.038V
510.5ps   1.026V     1.05V      1.029V
651.6ps   1.023V     1.049V     1.167V
805.1ps   1.127V     1.041V     1.302V
928.1ps   1.203V     1.096V     1.369V
1.064ns   1.261V     1.165V     1.413V
1.22ns    1.302V     1.225V     1.441V
1.592ns   1.344V     1.293V     1.469V
2.571ns   1.365V     1.324V     1.489V
10ns      1.373V     1.33V      1.501V
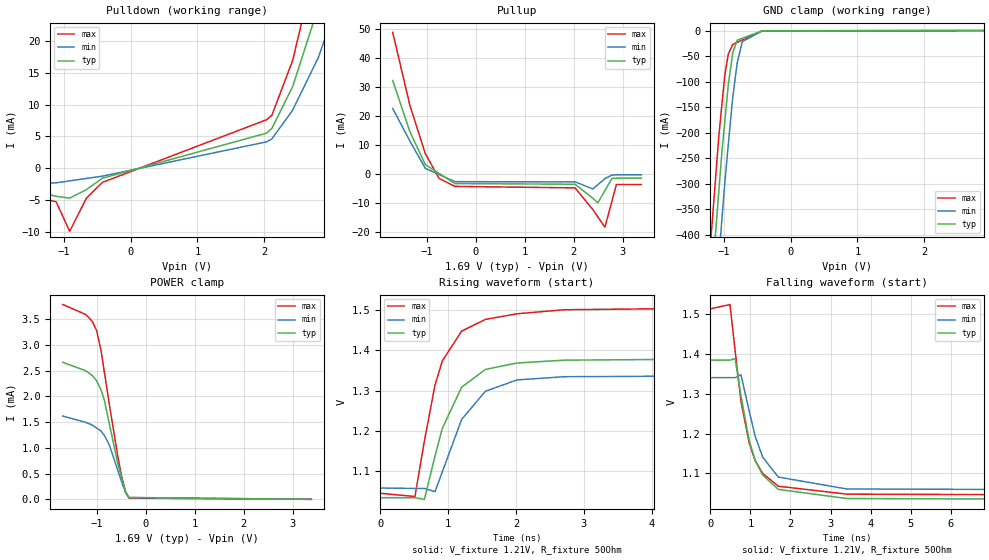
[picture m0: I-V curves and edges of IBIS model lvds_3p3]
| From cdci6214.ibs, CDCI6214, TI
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|   lvds_3p3 Model
[Model]   lvds_3p3
Model_type   3-state
Polarity   Non-Inverting
Vmeas = 1.21
Vref = 1.21
Cref = 2pF
Rref = 50
|   typ   min   max
C_comp   6.977E-12   6.849E-12   7.205E-12
|  Where Nom  PVT is Nominal Process, 1.69V,   32C
|   Fast PVT is Strong Process,  1.75V,   -35C
|   Slow PVT is Weak Process,   1.68V,   110C
[Voltage Range]   1.69   1.68   1.75
|Junction Temperature
[Temperature Range]   32   110   -35
[Pullup Reference]   1.69   1.68   1.75
[Pulldown Reference]   0   0   -0
[Power Clamp Reference]   1.69   1.68   1.75
[GND Clamp Reference]   0   0   0
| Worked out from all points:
|   slope of the pulldown table from 0 to 0.254 V, typ, clamps not added: 287 ohm
|   GND clamp passes 1 mA (typ) near -0.43 V on its own axis
|   POWER clamp passes 1 mA (typ) near -0.63 V on its own axis
|   falling waveform, V_fixture 1.21V, R_fixture 50Ohm: 20-80 % time 515ps typ, 544ps min, 486ps max; typ from 1.39 V to 1.03 V
|   rising waveform, V_fixture 1.21V, R_fixture 50Ohm: 20-80 % time 466ps typ, 489ps min, 435ps max; typ from 1.03 V to 1.39 V
[Pulldown]
|   Voltage   I(typ)   I(min)   I(max)
-1.69V    -1.652mA   -1.244mA   -2.148mA
-1.689V   -2.925mA   -2.538mA   -4.103mA
-1.113V   -4.419mA   -2.303mA   -5.265mA
-910.1mV  -4.71mA    -1.994mA   -9.921mA
-660.2mV  -3.376mA   -1.615mA   -4.73mA
-421.9mV  -1.583mA   -1.254mA   -2.241mA
2.035V    5.51mA     4.141mA    7.62mA
2.114V    6.252mA    4.604mA    8.317mA
2.425V    12.83mA    9.123mA    16.93mA
2.809V    25.32mA    17.4mA     33.91mA
3.101V    37.77mA    26.2mA     51.34mA
3.38V     53.14mA    37.31mA    72.58mA
[GND Clamp]
|   Voltage   I(typ)   I(min)   I(max)
-1.69V    -1.448A    -1.578A    -1.343A
-1.203V   -539mA     -673.9mA   -428.5mA
-1.155V   -454.5mA   -587mA     -347.6mA
-1.072V   -314.3mA   -446.5mA   -206.8mA
-1.029V   -242.2mA   -374.2mA   -148.9mA
-983.1mV  -178.7mA   -299mA     -87.41mA
-930.9mV  -106.3mA   -223.9mA   -46.43mA
-864.7mV  -44.64mA   -132.1mA   -27.37mA
-798.8mV  -18.95mA   -64.33mA   -23.38mA
-721.2mV  -15.17mA   -21.8mA    -18.69mA
-421.6mV  -558.9uA   -522uA     -573.7uA
3.38V     0A         0A         0A
[Pullup]
|   Voltage   I(typ)   I(min)   I(max)
-1.69V    32.2mA     22.55mA    48.84mA
-1.34V    14.54mA    11.28mA    23.62mA
-1.026V   3.165mA    1.864mA    6.95mA
-742.8mV  80.99uA    -304uA     -1.649mA
-422.1mV  -3.407mA   -2.756mA   -4.386mA
2.029V    -3.647mA   -2.823mA   -4.905mA
2.391V    -8.489mA   -5.265mA   -12.4mA
2.493V    -10.08mA   -3.809mA   -14.9mA
2.638V    -5.831mA   -1.724mA   -18.47mA
2.781V    -1.655mA   -493.2uA   -9.482mA
2.871V    -1.543mA   -375.1uA   -3.747mA
3.38V     -1.543mA   -375.1uA   -3.747mA
[POWER Clamp]
|   Voltage   I(typ)   I(min)   I(max)
-1.69V    2.661mA    1.617mA    3.783mA
-1.219V   2.496mA    1.495mA    3.588mA
-1.088V   2.405mA    1.443mA    3.456mA
-998.9mV  2.305mA    1.384mA    3.279mA
-910.6mV  2.131mA    1.327mA    2.903mA
-842.4mV  1.933mA    1.244mA    2.482mA
-741mV    1.478mA    1.06mA     1.856mA
-564.6mV  685.2uA    556.7uA    824.4uA
-486.8mV  407.8uA    334.7uA    439uA
-405.2mV  135.2uA    120.2uA    138.7uA
-338.8mV  35.97uA    33.67uA    24.08uA
3.38V     0A         0A         0A
[Ramp]
R_load = 50
|   typ   min   max
dV/dt_r   0.209734/4.65435e-10   0.169312/4.88026e-10   0.280635/4.35795e-10
dV/dt_f   0.209675/5.12073e-10   0.169238/5.41112e-10   0.280592/4.83961e-10
[Falling Waveform]
V_fixture = 1.21V
V_fixture_min = 1.2V
V_fixture_max = 1.28V
R_fixture = 50Ohm
C_fixture = 0F
|   Time   V(typ)   V(min)   V(max)
0s        1.385V     1.341V     1.514V
492ps     1.385V     1.341V     1.525V
618.8ps   1.389V     1.341V     1.41V
766.2ps   1.295V     1.348V     1.282V
969.1ps   1.184V     1.258V     1.177V
1.122ns   1.132V     1.193V     1.132V
1.309ns   1.096V     1.141V     1.1V
1.697ns   1.06V      1.091V     1.068V
3.412ns   1.037V     1.061V     1.048V
10ns      1.035V     1.059V     1.046V
[Rising Waveform]
V_fixture = 1.21V
V_fixture_min = 1.2V
V_fixture_max = 1.28V
R_fixture = 50Ohm
C_fixture = 0F
|   Time   V(typ)   V(min)   V(max)
0s        1.035V     1.059V     1.046V
511.2ps   1.035V     1.058V     1.038V
650.7ps   1.031V     1.058V     1.176V
806.5ps   1.138V     1.05V      1.314V
914.7ps   1.207V     1.099V     1.374V
1.199ns   1.309V     1.229V     1.448V
1.55ns    1.353V     1.299V     1.477V
2.016ns   1.369V     1.327V     1.491V
2.714ns   1.376V     1.335V     1.501V
10ns      1.385V     1.341V     1.514V
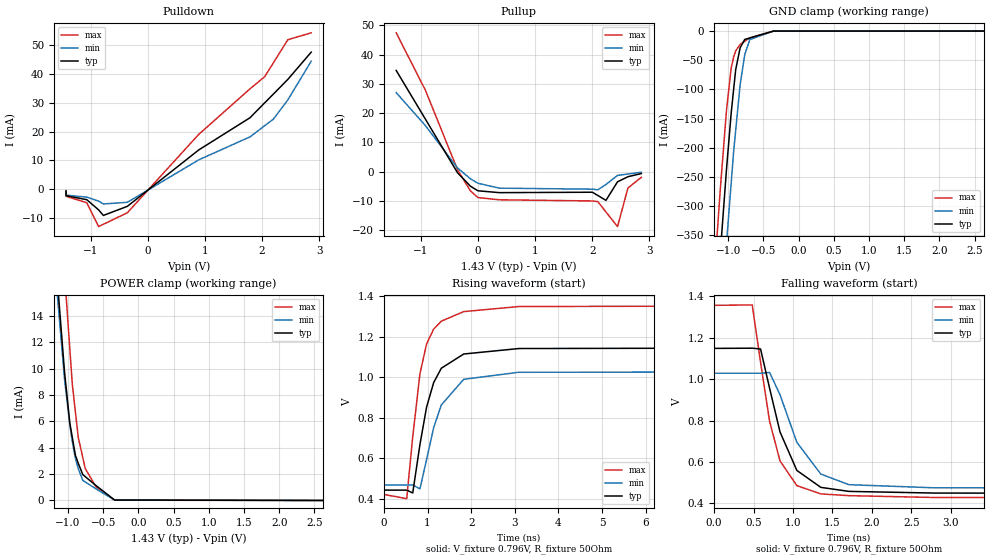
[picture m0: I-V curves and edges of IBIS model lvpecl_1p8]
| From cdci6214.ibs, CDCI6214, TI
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|   lvpecl_1p8 Model
[Model]   lvpecl_1p8
Model_type   3-state
Polarity   Non-Inverting
Vmeas = 0.8
Vref = 0.769
Cref = 2pF
Rref = 50
|   typ   min   max
C_comp   7.009E-12   6.881E-12   7.205E-12
|  Where Nom  PVT is Nominal Process, 1.43V,  32C
|   Fast PVT is Strong Process,  1.55V, -35C
|   Slow PVT is Weak Process,   1.42V, 110C
[Voltage Range]   1.43   1.42   1.55
|Junction Temperature
[Temperature Range]   32   110   -35
[Pullup Reference]   1.43   1.42   1.55
[Pulldown Reference]   0   0   0
[Power Clamp Reference]   1.43   1.42   1.55
[GND Clamp Reference]   0   0   0
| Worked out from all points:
|   slope of the pulldown table from 0 to 0.214 V, typ, clamps not added: 62.6 ohm
|   slope of the pullup table from 0 to 0.214 V, typ, clamps not added: 353 ohm
|   POWER clamp passes 1 mA (typ) near -0.57 V on its own axis
|   falling waveform, V_fixture 0.796V, R_fixture 50Ohm: 20-80 % time 330ps typ, 392ps min, 272ps max; typ from 1.15 V to 0.444 V
|   rising waveform, V_fixture 0.796V, R_fixture 50Ohm: 20-80 % time 440ps typ, 483ps min, 366ps max; typ from 0.444 V to 1.15 V
[Pulldown]
|   Voltage   I(typ)   I(min)   I(max)
-1.43V    -633.7uA   -459.1uA   -847.1uA
-1.429V   -2.243mA   -2.059mA   -2.466mA
-1.068V   -3.616mA   -2.734mA   -4.678mA
-860.6mV  -7.168mA   -4.131mA   -12.97mA
-777.8mV  -9.099mA   -5.108mA   -12.17mA
-357.4mV  -5.928mA   -4.534mA   -8.145mA
890.6mV   13.65mA    10.21mA    19.06mA
1.788V    24.84mA    18.2mA     34.88mA
2.045V    30.02mA    22.07mA    39.11mA
2.196V    33.04mA    24.32mA    43.88mA
2.45V     38.16mA    31.03mA    51.95mA
2.86V     47.65mA    44.5mA     54.35mA
[GND Clamp]
|   Voltage   I(typ)   I(min)   I(max)
-1.43V    -954.4mA   -1.087A    -846.6mA
-1.245V   -612.7mA   -747.5mA   -502.7mA
-1.113V   -382.6mA   -516.4mA   -273.4mA
-1.024V   -237.4mA   -364.4mA   -136.3mA
-956.7mV  -140.1mA   -260.1mA   -63.09mA
-922.4mV  -100.2mA   -206.7mA   -44.81mA
-892.8mV  -66.03mA   -169.9mA   -34.04mA
-830.1mV  -28.86mA   -92.26mA   -22.9mA
-764.5mV  -14.41mA   -40.35mA   -17.61mA
-692mV    -11.86mA   -14.54mA   -11.76mA
-357mV    -132uA     -142.8uA   -110.6uA
2.86V     0A         0A         0A
[Pullup]
|   Voltage   I(typ)   I(min)   I(max)
-1.43V    34.56mA    26.98mA    47.42mA
-918.9mV  17.92mA    15.72mA    27.81mA
-357.4mV  -363.1uA   1.258mA    661.3uA
-132.1mV  -4.959mA   -2.429mA   -6.562mA
-425.2uV  -6.54mA    -3.973mA   -8.859mA
377.1mV   -7.177mA   -5.643mA   -9.623mA
2.003V    -7.032mA   -5.994mA   -10.01mA
2.097V    -8.128mA   -6.194mA   -10.23mA
2.24V     -9.808mA   -4.39mA    -13.76mA
2.443V    -3.469mA   -1.28mA    -18.77mA
2.625V    -1.74mA    -811.6uA   -5.581mA
2.86V     -638.9uA   -208.8uA   -1.93mA
[POWER Clamp]
|   Voltage   I(typ)   I(min)   I(max)
-1.43V    43.24mA    39.09mA    65.58mA
-1.165V   17.69mA    16.5mA     29.34mA
-1.048V   9.747mA    9.204mA    17.21mA
-973mV    5.88mA     5.742mA    11.51mA
-937.4mV  4.775mA    4.448mA    8.809mA
-893.2mV  3.414mA    3.197mA    6.702mA
-852.8mV  2.817mA    2.411mA    4.777mA
-788.1mV  1.961mA    1.521mA    3.238mA
-753.7mV  1.808mA    1.404mA    2.422mA
-602.3mV  1.137mA    887uA      1.044mA
-336.8mV  36.22uA    32.32uA    22.55uA
2.86V     0A         0A         0A
[Ramp]
R_load = 50
|   typ   min   max
dV/dt_r   0.422941/4.3998e-10   0.335725/4.82687e-10   0.560455/3.66485e-10
dV/dt_f   0.422916/3.2927e-10   0.33571/3.91115e-10   0.560447/2.7184e-10
[Falling Waveform]
V_fixture = 0.796V
V_fixture_min = 0.749V
V_fixture_max = 0.889V
R_fixture = 50Ohm
C_fixture = 0F
|   Time   V(typ)   V(min)   V(max)
0s        1.149V     1.029V     1.357V
483.5ps   1.15V      1.029V     1.359V
589.3ps   1.146V     1.029V     1.082V
703.6ps   956.6mV    1.033V     796.9mV
835.6ps   745.6mV    925.2mV    605.6mV
1.049ns   559.5mV    695.3mV    486.1mV
1.353ns   477.6mV    541.9mV    446mV
1.709ns   458.2mV    490.6mV    437.6mV
2.79ns    450.1mV    475.5mV    428.7mV
20ns      444.2mV    469.5mV    422.9mV
[Rising Waveform]
V_fixture = 0.796V
V_fixture_min = 0.749V
V_fixture_max = 0.889V
R_fixture = 50Ohm
C_fixture = 0F
|   Time   V(typ)   V(min)   V(max)
0s        444.2mV    469.5mV    422.9mV
521.8ps   444mV      469.4mV    401.8mV
659.6ps   430.1mV    469.3mV    706.7mV
825.4ps   669.5mV    450.4mV    1.019V
977.8ps   854.1mV    595.8mV    1.165V
1.139ns   974mV      751.9mV    1.238V
1.315ns   1.045V     864mV      1.277V
1.828ns   1.115V     990.4mV    1.324V
3.09ns    1.142V     1.025V     1.349V
20ns      1.149V     1.029V     1.357V
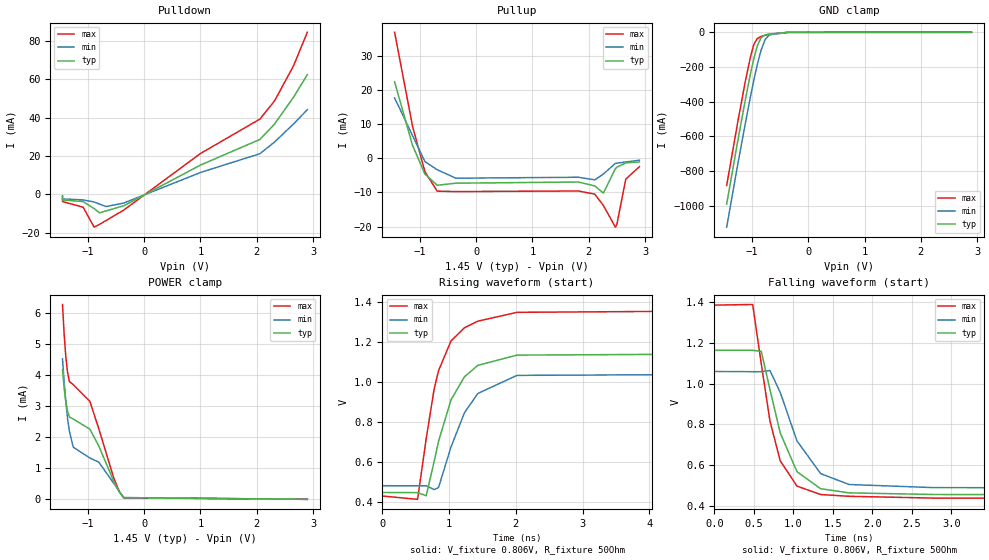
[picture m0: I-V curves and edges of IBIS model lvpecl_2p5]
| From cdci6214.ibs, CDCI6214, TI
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|   lvpecl_2p5 Model
[Model]   lvpecl_2p5
Model_type   3-state
Polarity   Non-Inverting
Vmeas = 0.8
Vref = 0.806
Cref = 2pF
Rref = 50
|   typ   min   max
C_comp   7.009E-12   6.878E-12   7.139E-12
|  Where Nom  PVT is Nominal Process, 1.45V,   32C
|   Fast PVT is Strong Process,  1.58V,  -35C
|   Slow PVT is Weak Process,   1.44V,  110C
[Voltage Range]   1.45   1.44   1.58
|Junction Temperature
[Temperature Range]   32   110   -35
[Pullup Reference]   1.45   1.44   1.58
[Pulldown Reference]   0   0   0
[Power Clamp Reference]   1.45   1.44   1.58
[GND Clamp Reference]   0   0   0
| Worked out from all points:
|   slope of the pulldown table from 0 to 0.217 V, typ, clamps not added: 62.6 ohm
|   falling waveform, V_fixture 0.806V, R_fixture 50Ohm: 20-80 % time 327ps typ, 389ps min, 271ps max; typ from 1.16 V to 0.45 V
|   rising waveform, V_fixture 0.806V, R_fixture 50Ohm: 20-80 % time 448ps typ, 476ps min, 393ps max; typ from 0.45 V to 1.16 V
[Pulldown]
|   Voltage   I(typ)   I(min)   I(max)
-1.45V    -1.314mA   -789.5uA   -2.171mA
-1.449V   -2.95mA    -2.415mA   -3.817mA
-1.084V   -3.837mA   -2.955mA   -6.743mA
-888.7mV  -7.444mA   -4.025mA   -17.16mA
-793mV    -9.683mA   -5.112mA   -15.72mA
-677.7mV  -8.701mA   -6.42mA    -13.72mA
-361.9mV  -6.005mA   -4.595mA   -8.255mA
1.001V    15.22mA    11.35mA    21.25mA
2.058V    28.62mA    21.16mA    39.22mA
2.317V    36.61mA    27.23mA    48.66mA
2.653V    50.57mA    36.64mA    66.89mA
2.9V      62.35mA    44.11mA    84.46mA
[GND Clamp]
|   Voltage   I(typ)   I(min)   I(max)
-1.45V    -991.9mA   -1.125A    -884.4mA
-1.257V   -634.1mA   -769.5mA   -524.8mA
-1.12V    -392.2mA   -528.3mA   -284.8mA
-1.027V   -239.2mA   -370.4mA   -141mA
-976.1mV  -163.7mA   -290.4mA   -80.3mA
-958.7mV  -140mA     -263.1mA   -64.73mA
-908.7mV  -81.15mA   -190.4mA   -37.15mA
-840.9mV  -31.85mA   -104.9mA   -24.07mA
-766.9mV  -14.5mA    -41.72mA   -17.04mA
-694.3mV  -9.682mA   -14.99mA   -11.52mA
-361.9mV  -149.9uA   -159.8uA   -129.2uA
2.9V      0A         0A         0A
[Pullup]
|   Voltage   I(typ)   I(min)   I(max)
-1.45V    22.34mA    17.65mA    36.85mA
-1.131V   3.741mA    6.605mA    9.345mA
-910.9mV  -4.646mA   -993uA     -3.94mA
-693.4mV  -7.912mA   -3.359mA   -9.648mA
-361.9mV  -7.312mA   -5.853mA   -9.76mA
1.814V    -6.966mA   -5.573mA   -9.59mA
2.106V    -8.113mA   -6.328mA   -10.51mA
2.259V    -10.21mA   -4.642mA   -13.81mA
2.473V    -3.066mA   -1.5mA     -20.18mA
2.499V    -2.647mA   -1.444mA   -19.43mA
2.657V    -1.358mA   -1.106mA   -6.125mA
2.9V      -1.084mA   -587.9uA   -2.485mA
[POWER Clamp]
|   Voltage   I(typ)   I(min)   I(max)
-1.45V    4.187mA    4.533mA    6.288mA
-1.42V    3.568mA    3.777mA    5.298mA
-1.392V   3.153mA    3.182mA    4.619mA
-1.36V    2.835mA    2.595mA    4.088mA
-1.327V   2.658mA    2.192mA    3.799mA
-1.26V    2.591mA    1.684mA    3.702mA
-964.8mV  2.266mA    1.335mA    3.166mA
-805.2mV  1.72mA     1.201mA    2.276mA
-544.2mV  601.4uA    526.1uA    717.1uA
-443.3mV  237.1uA    265uA      261uA
-362.4mV  56.49uA    55.63uA    50.14uA
2.9V      0A         0A         0A
[Ramp]
R_load = 50
|   typ   min   max
dV/dt_r   0.428357/4.47086e-10   0.345642/4.75639e-10   0.572244/3.92434e-10
dV/dt_f   0.428348/3.26946e-10   0.345628/3.88517e-10   0.572243/2.70273e-10
[Falling Waveform]
V_fixture = 0.806V
V_fixture_min = 0.771V
V_fixture_max = 0.908V
R_fixture = 50Ohm
C_fixture = 0F
|   Time   V(typ)   V(min)   V(max)
0s        1.164V     1.06V      1.386V
484ps     1.164V     1.059V     1.389V
592.9ps   1.159V     1.059V     1.098V
702.7ps   971.9mV    1.065V     817.1mV
833.2ps   758mV      957.1mV    621mV
1.045ns   567.9mV    718.9mV    497.2mV
1.345ns   484.2mV    558.4mV    455.8mV
1.705ns   463.9mV    505mV      447.1mV
2.782ns   455.9mV    489.6mV    438.2mV
20ns      449.8mV    483.5mV    432.2mV
[Rising Waveform]
V_fixture = 0.806V
V_fixture_min = 0.771V
V_fixture_max = 0.908V
R_fixture = 50Ohm
C_fixture = 0F
|   Time   V(typ)   V(min)   V(max)
0s        449.8mV    483.5mV    432.2mV
528ps     449.1mV    483.3mV    415.7mV
656.9ps   433.7mV    483.3mV    717.7mV
774.9ps   602.4mV    464mV      963mV
841.7ps   704.4mV    474.5mV    1.056V
1.028ns   910.3mV    675.5mV    1.204V
1.23ns    1.026V     846.8mV    1.27V
1.431ns   1.083V     943mV      1.303V
2.018ns   1.134V     1.033V     1.347V
20ns      1.164V     1.06V      1.386V
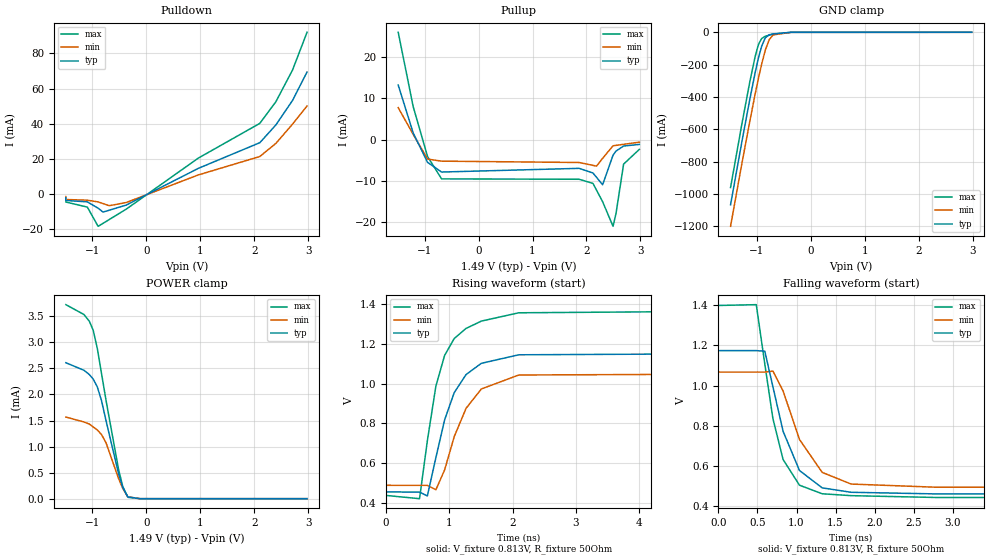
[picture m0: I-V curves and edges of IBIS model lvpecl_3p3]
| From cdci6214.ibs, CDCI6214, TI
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|   lvpecl_3p3 Model
[Model]   lvpecl_3p3
Model_type   3-state
Polarity   Non-Inverting
Vmeas = 0.8
Vref = 0.813
Cref = 2pF
Rref = 50
|   typ   min   max
C_comp   6.977E-12   6.849E-12   7.106E-12
|  Where Nom  PVT is Nominal Process, 1.49V,   32C
|   Fast PVT is Strong Process,  1.6V,   -35C
|   Slow PVT is Weak Process,   1.47V,   110C
[Voltage Range]   1.49   1.47   1.6
|Junction Temperature
[Temperature Range]   32   110   -35
[Pullup Reference]   1.49   1.47   1.6
[Pulldown Reference]   0   0   0
[Power Clamp Reference]   1.49   1.47   1.6
[GND Clamp Reference]   0   0   0
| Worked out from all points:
|   slope of the pulldown table from 0 to 0.224 V, typ, clamps not added: 62.6 ohm
|   POWER clamp passes 1 mA (typ) near -0.64 V on its own axis
|   falling waveform, V_fixture 0.813V, R_fixture 50Ohm: 20-80 % time 325ps typ, 387ps min, 269ps max; typ from 1.17 V to 0.454 V
|   rising waveform, V_fixture 0.813V, R_fixture 50Ohm: 20-80 % time 451ps typ, 475ps min, 408ps max; typ from 0.454 V to 1.17 V
[Pulldown]
|   Voltage   I(typ)   I(min)   I(max)
-1.49V    -1.863mA   -1.336mA   -2.74mA
-1.489V   -3.551mA   -3.013mA   -4.439mA
-1.092V   -4.332mA   -3.375mA   -7.319mA
-893.1mV  -7.944mA   -4.374mA   -18.23mA
-800.6mV  -10.14mA   -5.333mA   -16.53mA
-686.2mV  -9.083mA   -6.517mA   -14.38mA
-371.9mV  -6.17mA    -4.721mA   -8.489mA
965.1mV   14.71mA    10.98mA    20.54mA
2.105V    29.3mA     21.44mA    40.28mA
2.403V    39.4mA     28.91mA    52.61mA
2.713V    53.4mA     39.91mA    70.7mA
2.98V     69.46mA    50.13mA    92.05mA
[GND Clamp]
|   Voltage   I(typ)   I(min)   I(max)
-1.49V    -1.067A    -1.2A      -960.2mA
-1.281V   -678.5mA   -813.7mA   -569.3mA
-1.134V   -416.1mA   -552.4mA   -308.2mA
-1.035V   -251.3mA   -383.6mA   -151.8mA
-985.2mV  -176.5mA   -304.5mA   -89.58mA
-962.8mV  -145.5mA   -268.9mA   -68.11mA
-913.2mV  -85.78mA   -197.2mA   -38.72mA
-845.3mV  -33.88mA   -109.3mA   -24.59mA
-772mV    -15.15mA   -44.75mA   -17.49mA
-699.1mV  -10.08mA   -16.01mA   -11.85mA
-371.9mV  -193.4uA   -199.2uA   -173.8uA
2.98V     0A         0A         0A
[Pullup]
|   Voltage   I(typ)   I(min)   I(max)
-1.49V    13.26mA    7.762mA    26.11mA
-1.212V   1.586mA    1.253mA    7.988mA
-946.3mV  -5.545mA   -4.739mA   -4.117mA
-686.1mV  -7.902mA   -5.254mA   -9.571mA
1.864V    -7.004mA   -5.582mA   -9.661mA
2.12V     -8.136mA   -6.281mA   -10.67mA
2.186V    -9.191mA   -6.458mA   -12.31mA
2.299V    -11mA      -4.564mA   -15.12mA
2.492V    -3.805mA   -1.513mA   -21.11mA
2.547V    -2.804mA   -1.415mA   -18.02mA
2.688V    -1.572mA   -1.158mA   -5.97mA
2.98V     -1.181mA   -629.1uA   -2.384mA
[POWER Clamp]
|   Voltage   I(typ)   I(min)   I(max)
-1.49V    2.609mA    1.567mA    3.724mA
-1.154V   2.464mA    1.472mA    3.534mA
-1.055V   2.383mA    1.433mA    3.405mA
-983.8mV  2.296mA    1.377mA    3.234mA
-907mV    2.145mA    1.318mA    2.882mA
-829.2mV  1.881mA    1.231mA    2.403mA
-743.8mV  1.489mA    1.068mA    1.876mA
-514.5mV  484.1uA    389.3uA    568.2uA
-436.7mV  217.7uA    200.2uA    237.5uA
-342mV    33.77uA    35.93uA    26.82uA
-117.6mV  78.55nA    92.59nA    6.704nA
2.98V     0A         0A         0A
[Ramp]
R_load = 50
|   typ   min   max
dV/dt_r   0.431967/4.50585e-10   0.348109/4.74797e-10   0.577487/4.07151e-10
dV/dt_f   0.431962/3.24826e-10   0.348104/3.86465e-10   0.577487/2.69009e-10
[Falling Waveform]
V_fixture = 0.813V
V_fixture_min = 0.777V
V_fixture_max = 0.916V
R_fixture = 50Ohm
C_fixture = 0F
|   Time   V(typ)   V(min)   V(max)
0s        1.174V     1.067V     1.399V
484.5ps   1.174V     1.067V     1.403V
593.6ps   1.171V     1.067V     1.107V
697.7ps   993.5mV    1.072V     834.7mV
828.3ps   771.7mV    972.6mV    631mV
1.038ns   576.6mV    731.2mV    503.4mV
1.329ns   490mV      567.2mV    460.6mV
1.7ns     468mV      509mV      451.2mV
2.775ns   460mV      493.4mV    442.2mV
20ns      453.8mV    487.3mV    436.1mV
[Rising Waveform]
V_fixture = 0.813V
V_fixture_min = 0.777V
V_fixture_max = 0.916V
R_fixture = 50Ohm
C_fixture = 0F
|   Time   V(typ)   V(min)   V(max)
0s        453.8mV    487.3mV    436.1mV
528.3ps   453.2mV    487mV      419.8mV
652ps     433.7mV    487mV      712mV
786.7ps   626.7mV    464.8mV    987.6mV
925ps     817.3mV    564.6mV    1.143V
1.077ns   954.9mV    732.8mV    1.228V
1.264ns   1.046V     875.5mV    1.279V
1.506ns   1.103V     973.5mV    1.316V
2.099ns   1.146V     1.044V     1.358V
20ns      1.174V     1.067V     1.399V
